VERSION 5.8 ;
BUSBITCHARS "[]" ;
DIVIDERCHAR "/" ;
UNITS
    DATABASE MICRONS 1000 ;
END UNITS

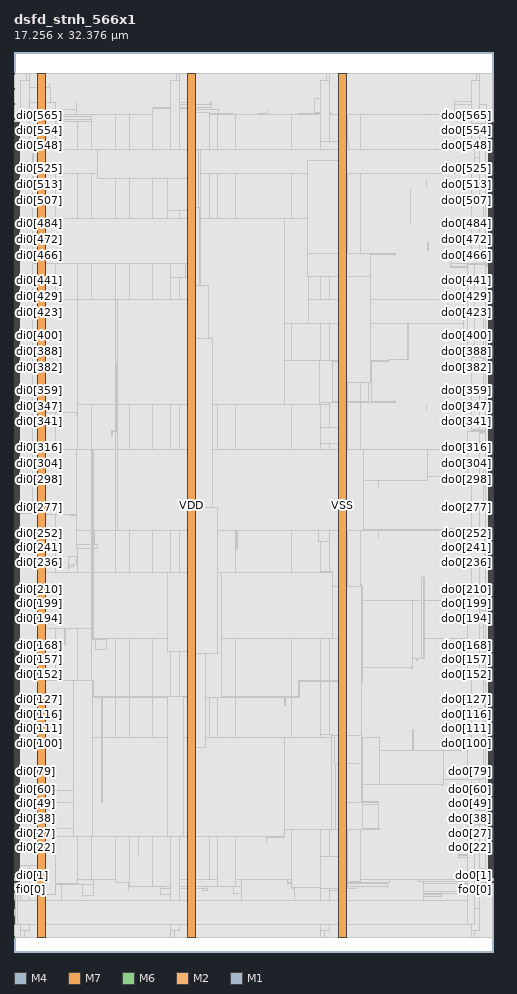
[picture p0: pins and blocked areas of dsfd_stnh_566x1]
MACRO dsfd_stnh_566x1
  FOREIGN dsfd_stnh_566x1 0 0 ;
  CLASS BLOCK ;
  SIZE 17.256 BY 32.376 ;
  PIN di0[0]
    DIRECTION INPUT ;
    USE SIGNAL ;
    PORT
      LAYER M4 ;
        RECT  0 2.688 0.192 2.712 ;
    END
  END di0[0]
  PIN di0[100]
    DIRECTION INPUT ;
    USE SIGNAL ;
    PORT
      LAYER M4 ;
        RECT  0 7.488 0.192 7.512 ;
    END
  END di0[100]
  PIN di0[101]
    DIRECTION INPUT ;
    USE SIGNAL ;
    PORT
      LAYER M4 ;
        RECT  0 7.536 0.192 7.56 ;
    END
  END di0[101]
  PIN di0[102]
    DIRECTION INPUT ;
    USE SIGNAL ;
    PORT
      LAYER M4 ;
        RECT  0 7.584 0.192 7.608 ;
    END
  END di0[102]
  PIN di0[103]
    DIRECTION INPUT ;
    USE SIGNAL ;
    PORT
      LAYER M4 ;
        RECT  0 7.632 0.192 7.656 ;
    END
  END di0[103]
  PIN di0[104]
    DIRECTION INPUT ;
    USE SIGNAL ;
    PORT
      LAYER M4 ;
        RECT  0 7.68 0.192 7.704 ;
    END
  END di0[104]
  PIN di0[105]
    DIRECTION INPUT ;
    USE SIGNAL ;
    PORT
      LAYER M4 ;
        RECT  0 7.728 0.192 7.752 ;
    END
  END di0[105]
  PIN di0[106]
    DIRECTION INPUT ;
    USE SIGNAL ;
    PORT
      LAYER M4 ;
        RECT  0 7.776 0.192 7.8 ;
    END
  END di0[106]
  PIN di0[107]
    DIRECTION INPUT ;
    USE SIGNAL ;
    PORT
      LAYER M4 ;
        RECT  0 7.824 0.192 7.848 ;
    END
  END di0[107]
  PIN di0[108]
    DIRECTION INPUT ;
    USE SIGNAL ;
    PORT
      LAYER M4 ;
        RECT  0 7.872 0.192 7.896 ;
    END
  END di0[108]
  PIN di0[109]
    DIRECTION INPUT ;
    USE SIGNAL ;
    PORT
      LAYER M4 ;
        RECT  0 7.92 0.192 7.944 ;
    END
  END di0[109]
  PIN di0[10]
    DIRECTION INPUT ;
    USE SIGNAL ;
    PORT
      LAYER M4 ;
        RECT  0 3.168 0.192 3.192 ;
    END
  END di0[10]
  PIN di0[110]
    DIRECTION INPUT ;
    USE SIGNAL ;
    PORT
      LAYER M4 ;
        RECT  0 7.968 0.192 7.992 ;
    END
  END di0[110]
  PIN di0[111]
    DIRECTION INPUT ;
    USE SIGNAL ;
    PORT
      LAYER M4 ;
        RECT  0 8.016 0.192 8.04 ;
    END
  END di0[111]
  PIN di0[112]
    DIRECTION INPUT ;
    USE SIGNAL ;
    PORT
      LAYER M4 ;
        RECT  0 8.064 0.192 8.088 ;
    END
  END di0[112]
  PIN di0[113]
    DIRECTION INPUT ;
    USE SIGNAL ;
    PORT
      LAYER M4 ;
        RECT  0 8.112 0.192 8.136 ;
    END
  END di0[113]
  PIN di0[114]
    DIRECTION INPUT ;
    USE SIGNAL ;
    PORT
      LAYER M4 ;
        RECT  0 8.16 0.192 8.184 ;
    END
  END di0[114]
  PIN di0[115]
    DIRECTION INPUT ;
    USE SIGNAL ;
    PORT
      LAYER M4 ;
        RECT  0 8.208 0.192 8.232 ;
    END
  END di0[115]
  PIN di0[116]
    DIRECTION INPUT ;
    USE SIGNAL ;
    PORT
      LAYER M4 ;
        RECT  0 8.256 0.192 8.28 ;
    END
  END di0[116]
  PIN di0[117]
    DIRECTION INPUT ;
    USE SIGNAL ;
    PORT
      LAYER M4 ;
        RECT  0 8.304 0.192 8.328 ;
    END
  END di0[117]
  PIN di0[118]
    DIRECTION INPUT ;
    USE SIGNAL ;
    PORT
      LAYER M4 ;
        RECT  0 8.352 0.192 8.376 ;
    END
  END di0[118]
  PIN di0[119]
    DIRECTION INPUT ;
    USE SIGNAL ;
    PORT
      LAYER M4 ;
        RECT  0 8.4 0.192 8.424 ;
    END
  END di0[119]
  PIN di0[11]
    DIRECTION INPUT ;
    USE SIGNAL ;
    PORT
      LAYER M4 ;
        RECT  0 3.216 0.192 3.24 ;
    END
  END di0[11]
  PIN di0[120]
    DIRECTION INPUT ;
    USE SIGNAL ;
    PORT
      LAYER M4 ;
        RECT  0 8.448 0.192 8.472 ;
    END
  END di0[120]
  PIN di0[121]
    DIRECTION INPUT ;
    USE SIGNAL ;
    PORT
      LAYER M4 ;
        RECT  0 8.496 0.192 8.52 ;
    END
  END di0[121]
  PIN di0[122]
    DIRECTION INPUT ;
    USE SIGNAL ;
    PORT
      LAYER M4 ;
        RECT  0 8.544 0.192 8.568 ;
    END
  END di0[122]
  PIN di0[123]
    DIRECTION INPUT ;
    USE SIGNAL ;
    PORT
      LAYER M4 ;
        RECT  0 8.592 0.192 8.616 ;
    END
  END di0[123]
  PIN di0[124]
    DIRECTION INPUT ;
    USE SIGNAL ;
    PORT
      LAYER M4 ;
        RECT  0 8.64 0.192 8.664 ;
    END
  END di0[124]
  PIN di0[125]
    DIRECTION INPUT ;
    USE SIGNAL ;
    PORT
      LAYER M4 ;
        RECT  0 8.688 0.192 8.712 ;
    END
  END di0[125]
  PIN di0[126]
    DIRECTION INPUT ;
    USE SIGNAL ;
    PORT
      LAYER M4 ;
        RECT  0 8.736 0.192 8.76 ;
    END
  END di0[126]
  PIN di0[127]
    DIRECTION INPUT ;
    USE SIGNAL ;
    PORT
      LAYER M4 ;
        RECT  0 8.784 0.192 8.808 ;
    END
  END di0[127]
  PIN di0[128]
    DIRECTION INPUT ;
    USE SIGNAL ;
    PORT
      LAYER M4 ;
        RECT  0 8.832 0.192 8.856 ;
    END
  END di0[128]
  PIN di0[129]
    DIRECTION INPUT ;
    USE SIGNAL ;
    PORT
      LAYER M4 ;
        RECT  0 8.88 0.192 8.904 ;
    END
  END di0[129]
  PIN di0[12]
    DIRECTION INPUT ;
    USE SIGNAL ;
    PORT
      LAYER M4 ;
        RECT  0 3.264 0.192 3.288 ;
    END
  END di0[12]
  PIN di0[130]
    DIRECTION INPUT ;
    USE SIGNAL ;
    PORT
      LAYER M4 ;
        RECT  0 8.928 0.192 8.952 ;
    END
  END di0[130]
  PIN di0[131]
    DIRECTION INPUT ;
    USE SIGNAL ;
    PORT
      LAYER M4 ;
        RECT  0 8.976 0.192 9 ;
    END
  END di0[131]
  PIN di0[132]
    DIRECTION INPUT ;
    USE SIGNAL ;
    PORT
      LAYER M4 ;
        RECT  0 9.024 0.192 9.048 ;
    END
  END di0[132]
  PIN di0[133]
    DIRECTION INPUT ;
    USE SIGNAL ;
    PORT
      LAYER M4 ;
        RECT  0 9.072 0.192 9.096 ;
    END
  END di0[133]
  PIN di0[134]
    DIRECTION INPUT ;
    USE SIGNAL ;
    PORT
      LAYER M4 ;
        RECT  0 9.12 0.192 9.144 ;
    END
  END di0[134]
  PIN di0[135]
    DIRECTION INPUT ;
    USE SIGNAL ;
    PORT
      LAYER M4 ;
        RECT  0 9.168 0.192 9.192 ;
    END
  END di0[135]
  PIN di0[136]
    DIRECTION INPUT ;
    USE SIGNAL ;
    PORT
      LAYER M4 ;
        RECT  0 9.216 0.192 9.24 ;
    END
  END di0[136]
  PIN di0[137]
    DIRECTION INPUT ;
    USE SIGNAL ;
    PORT
      LAYER M4 ;
        RECT  0 9.264 0.192 9.288 ;
    END
  END di0[137]
  PIN di0[138]
    DIRECTION INPUT ;
    USE SIGNAL ;
    PORT
      LAYER M4 ;
        RECT  0 9.312 0.192 9.336 ;
    END
  END di0[138]
  PIN di0[139]
    DIRECTION INPUT ;
    USE SIGNAL ;
    PORT
      LAYER M4 ;
        RECT  0 9.36 0.192 9.384 ;
    END
  END di0[139]
  PIN di0[13]
    DIRECTION INPUT ;
    USE SIGNAL ;
    PORT
      LAYER M4 ;
        RECT  0 3.312 0.192 3.336 ;
    END
  END di0[13]
  PIN di0[140]
    DIRECTION INPUT ;
    USE SIGNAL ;
    PORT
      LAYER M4 ;
        RECT  0 9.408 0.192 9.432 ;
    END
  END di0[140]
  PIN di0[141]
    DIRECTION INPUT ;
    USE SIGNAL ;
    PORT
      LAYER M4 ;
        RECT  0 9.456 0.192 9.48 ;
    END
  END di0[141]
  PIN di0[142]
    DIRECTION INPUT ;
    USE SIGNAL ;
    PORT
      LAYER M4 ;
        RECT  0 9.504 0.192 9.528 ;
    END
  END di0[142]
  PIN di0[143]
    DIRECTION INPUT ;
    USE SIGNAL ;
    PORT
      LAYER M4 ;
        RECT  0 9.552 0.192 9.576 ;
    END
  END di0[143]
  PIN di0[144]
    DIRECTION INPUT ;
    USE SIGNAL ;
    PORT
      LAYER M4 ;
        RECT  0 9.6 0.192 9.624 ;
    END
  END di0[144]
  PIN di0[145]
    DIRECTION INPUT ;
    USE SIGNAL ;
    PORT
      LAYER M4 ;
        RECT  0 9.648 0.192 9.672 ;
    END
  END di0[145]
  PIN di0[146]
    DIRECTION INPUT ;
    USE SIGNAL ;
    PORT
      LAYER M4 ;
        RECT  0 9.696 0.192 9.72 ;
    END
  END di0[146]
  PIN di0[147]
    DIRECTION INPUT ;
    USE SIGNAL ;
    PORT
      LAYER M4 ;
        RECT  0 9.744 0.192 9.768 ;
    END
  END di0[147]
  PIN di0[148]
    DIRECTION INPUT ;
    USE SIGNAL ;
    PORT
      LAYER M4 ;
        RECT  0 9.792 0.192 9.816 ;
    END
  END di0[148]
  PIN di0[149]
    DIRECTION INPUT ;
    USE SIGNAL ;
    PORT
      LAYER M4 ;
        RECT  0 9.84 0.192 9.864 ;
    END
  END di0[149]
  PIN di0[14]
    DIRECTION INPUT ;
    USE SIGNAL ;
    PORT
      LAYER M4 ;
        RECT  0 3.36 0.192 3.384 ;
    END
  END di0[14]
  PIN di0[150]
    DIRECTION INPUT ;
    USE SIGNAL ;
    PORT
      LAYER M4 ;
        RECT  0 9.888 0.192 9.912 ;
    END
  END di0[150]
  PIN di0[151]
    DIRECTION INPUT ;
    USE SIGNAL ;
    PORT
      LAYER M4 ;
        RECT  0 9.936 0.192 9.96 ;
    END
  END di0[151]
  PIN di0[152]
    DIRECTION INPUT ;
    USE SIGNAL ;
    PORT
      LAYER M4 ;
        RECT  0 9.984 0.192 10.008 ;
    END
  END di0[152]
  PIN di0[153]
    DIRECTION INPUT ;
    USE SIGNAL ;
    PORT
      LAYER M4 ;
        RECT  0 10.032 0.192 10.056 ;
    END
  END di0[153]
  PIN di0[154]
    DIRECTION INPUT ;
    USE SIGNAL ;
    PORT
      LAYER M4 ;
        RECT  0 10.08 0.192 10.104 ;
    END
  END di0[154]
  PIN di0[155]
    DIRECTION INPUT ;
    USE SIGNAL ;
    PORT
      LAYER M4 ;
        RECT  0 10.128 0.192 10.152 ;
    END
  END di0[155]
  PIN di0[156]
    DIRECTION INPUT ;
    USE SIGNAL ;
    PORT
      LAYER M4 ;
        RECT  0 10.176 0.192 10.2 ;
    END
  END di0[156]
  PIN di0[157]
    DIRECTION INPUT ;
    USE SIGNAL ;
    PORT
      LAYER M4 ;
        RECT  0 10.224 0.192 10.248 ;
    END
  END di0[157]
  PIN di0[158]
    DIRECTION INPUT ;
    USE SIGNAL ;
    PORT
      LAYER M4 ;
        RECT  0 10.272 0.192 10.296 ;
    END
  END di0[158]
  PIN di0[159]
    DIRECTION INPUT ;
    USE SIGNAL ;
    PORT
      LAYER M4 ;
        RECT  0 10.32 0.192 10.344 ;
    END
  END di0[159]
  PIN di0[15]
    DIRECTION INPUT ;
    USE SIGNAL ;
    PORT
      LAYER M4 ;
        RECT  0 3.408 0.192 3.432 ;
    END
  END di0[15]
  PIN di0[160]
    DIRECTION INPUT ;
    USE SIGNAL ;
    PORT
      LAYER M4 ;
        RECT  0 10.368 0.192 10.392 ;
    END
  END di0[160]
  PIN di0[161]
    DIRECTION INPUT ;
    USE SIGNAL ;
    PORT
      LAYER M4 ;
        RECT  0 10.416 0.192 10.44 ;
    END
  END di0[161]
  PIN di0[162]
    DIRECTION INPUT ;
    USE SIGNAL ;
    PORT
      LAYER M4 ;
        RECT  0 10.464 0.192 10.488 ;
    END
  END di0[162]
  PIN di0[163]
    DIRECTION INPUT ;
    USE SIGNAL ;
    PORT
      LAYER M4 ;
        RECT  0 10.512 0.192 10.536 ;
    END
  END di0[163]
  PIN di0[164]
    DIRECTION INPUT ;
    USE SIGNAL ;
    PORT
      LAYER M4 ;
        RECT  0 10.56 0.192 10.584 ;
    END
  END di0[164]
  PIN di0[165]
    DIRECTION INPUT ;
    USE SIGNAL ;
    PORT
      LAYER M4 ;
        RECT  0 10.608 0.192 10.632 ;
    END
  END di0[165]
  PIN di0[166]
    DIRECTION INPUT ;
    USE SIGNAL ;
    PORT
      LAYER M4 ;
        RECT  0 10.656 0.192 10.68 ;
    END
  END di0[166]
  PIN di0[167]
    DIRECTION INPUT ;
    USE SIGNAL ;
    PORT
      LAYER M4 ;
        RECT  0 10.704 0.192 10.728 ;
    END
  END di0[167]
  PIN di0[168]
    DIRECTION INPUT ;
    USE SIGNAL ;
    PORT
      LAYER M4 ;
        RECT  0 10.752 0.192 10.776 ;
    END
  END di0[168]
  PIN di0[169]
    DIRECTION INPUT ;
    USE SIGNAL ;
    PORT
      LAYER M4 ;
        RECT  0 10.8 0.192 10.824 ;
    END
  END di0[169]
  PIN di0[16]
    DIRECTION INPUT ;
    USE SIGNAL ;
    PORT
      LAYER M4 ;
        RECT  0 3.456 0.192 3.48 ;
    END
  END di0[16]
  PIN di0[170]
    DIRECTION INPUT ;
    USE SIGNAL ;
    PORT
      LAYER M4 ;
        RECT  0 10.848 0.192 10.872 ;
    END
  END di0[170]
  PIN di0[171]
    DIRECTION INPUT ;
    USE SIGNAL ;
    PORT
      LAYER M4 ;
        RECT  0 10.896 0.192 10.92 ;
    END
  END di0[171]
  PIN di0[172]
    DIRECTION INPUT ;
    USE SIGNAL ;
    PORT
      LAYER M4 ;
        RECT  0 10.944 0.192 10.968 ;
    END
  END di0[172]
  PIN di0[173]
    DIRECTION INPUT ;
    USE SIGNAL ;
    PORT
      LAYER M4 ;
        RECT  0 10.992 0.192 11.016 ;
    END
  END di0[173]
  PIN di0[174]
    DIRECTION INPUT ;
    USE SIGNAL ;
    PORT
      LAYER M4 ;
        RECT  0 11.04 0.192 11.064 ;
    END
  END di0[174]
  PIN di0[175]
    DIRECTION INPUT ;
    USE SIGNAL ;
    PORT
      LAYER M4 ;
        RECT  0 11.088 0.192 11.112 ;
    END
  END di0[175]
  PIN di0[176]
    DIRECTION INPUT ;
    USE SIGNAL ;
    PORT
      LAYER M4 ;
        RECT  0 11.136 0.192 11.16 ;
    END
  END di0[176]
  PIN di0[177]
    DIRECTION INPUT ;
    USE SIGNAL ;
    PORT
      LAYER M4 ;
        RECT  0 11.184 0.192 11.208 ;
    END
  END di0[177]
  PIN di0[178]
    DIRECTION INPUT ;
    USE SIGNAL ;
    PORT
      LAYER M4 ;
        RECT  0 11.232 0.192 11.256 ;
    END
  END di0[178]
  PIN di0[179]
    DIRECTION INPUT ;
    USE SIGNAL ;
    PORT
      LAYER M4 ;
        RECT  0 11.28 0.192 11.304 ;
    END
  END di0[179]
  PIN di0[17]
    DIRECTION INPUT ;
    USE SIGNAL ;
    PORT
      LAYER M4 ;
        RECT  0 3.504 0.192 3.528 ;
    END
  END di0[17]
  PIN di0[180]
    DIRECTION INPUT ;
    USE SIGNAL ;
    PORT
      LAYER M4 ;
        RECT  0 11.328 0.192 11.352 ;
    END
  END di0[180]
  PIN di0[181]
    DIRECTION INPUT ;
    USE SIGNAL ;
    PORT
      LAYER M4 ;
        RECT  0 11.376 0.192 11.4 ;
    END
  END di0[181]
  PIN di0[182]
    DIRECTION INPUT ;
    USE SIGNAL ;
    PORT
      LAYER M4 ;
        RECT  0 11.424 0.192 11.448 ;
    END
  END di0[182]
  PIN di0[183]
    DIRECTION INPUT ;
    USE SIGNAL ;
    PORT
      LAYER M4 ;
        RECT  0 11.472 0.192 11.496 ;
    END
  END di0[183]
  PIN di0[184]
    DIRECTION INPUT ;
    USE SIGNAL ;
    PORT
      LAYER M4 ;
        RECT  0 11.52 0.192 11.544 ;
    END
  END di0[184]
  PIN di0[185]
    DIRECTION INPUT ;
    USE SIGNAL ;
    PORT
      LAYER M4 ;
        RECT  0 11.568 0.192 11.592 ;
    END
  END di0[185]
  PIN di0[186]
    DIRECTION INPUT ;
    USE SIGNAL ;
    PORT
      LAYER M4 ;
        RECT  0 11.616 0.192 11.64 ;
    END
  END di0[186]
  PIN di0[187]
    DIRECTION INPUT ;
    USE SIGNAL ;
    PORT
      LAYER M4 ;
        RECT  0 11.664 0.192 11.688 ;
    END
  END di0[187]
  PIN di0[188]
    DIRECTION INPUT ;
    USE SIGNAL ;
    PORT
      LAYER M4 ;
        RECT  0 11.712 0.192 11.736 ;
    END
  END di0[188]
  PIN di0[189]
    DIRECTION INPUT ;
    USE SIGNAL ;
    PORT
      LAYER M4 ;
        RECT  0 11.76 0.192 11.784 ;
    END
  END di0[189]
  PIN di0[18]
    DIRECTION INPUT ;
    USE SIGNAL ;
    PORT
      LAYER M4 ;
        RECT  0 3.552 0.192 3.576 ;
    END
  END di0[18]
  PIN di0[190]
    DIRECTION INPUT ;
    USE SIGNAL ;
    PORT
      LAYER M4 ;
        RECT  0 11.808 0.192 11.832 ;
    END
  END di0[190]
  PIN di0[191]
    DIRECTION INPUT ;
    USE SIGNAL ;
    PORT
      LAYER M4 ;
        RECT  0 11.856 0.192 11.88 ;
    END
  END di0[191]
  PIN di0[192]
    DIRECTION INPUT ;
    USE SIGNAL ;
    PORT
      LAYER M4 ;
        RECT  0 11.904 0.192 11.928 ;
    END
  END di0[192]
  PIN di0[193]
    DIRECTION INPUT ;
    USE SIGNAL ;
    PORT
      LAYER M4 ;
        RECT  0 11.952 0.192 11.976 ;
    END
  END di0[193]
  PIN di0[194]
    DIRECTION INPUT ;
    USE SIGNAL ;
    PORT
      LAYER M4 ;
        RECT  0 12 0.192 12.024 ;
    END
  END di0[194]
  PIN di0[195]
    DIRECTION INPUT ;
    USE SIGNAL ;
    PORT
      LAYER M4 ;
        RECT  0 12.048 0.192 12.072 ;
    END
  END di0[195]
  PIN di0[196]
    DIRECTION INPUT ;
    USE SIGNAL ;
    PORT
      LAYER M4 ;
        RECT  0 12.096 0.192 12.12 ;
    END
  END di0[196]
  PIN di0[197]
    DIRECTION INPUT ;
    USE SIGNAL ;
    PORT
      LAYER M4 ;
        RECT  0 12.144 0.192 12.168 ;
    END
  END di0[197]
  PIN di0[198]
    DIRECTION INPUT ;
    USE SIGNAL ;
    PORT
      LAYER M4 ;
        RECT  0 12.192 0.192 12.216 ;
    END
  END di0[198]
  PIN di0[199]
    DIRECTION INPUT ;
    USE SIGNAL ;
    PORT
      LAYER M4 ;
        RECT  0 12.24 0.192 12.264 ;
    END
  END di0[199]
  PIN di0[19]
    DIRECTION INPUT ;
    USE SIGNAL ;
    PORT
      LAYER M4 ;
        RECT  0 3.6 0.192 3.624 ;
    END
  END di0[19]
  PIN di0[1]
    DIRECTION INPUT ;
    USE SIGNAL ;
    PORT
      LAYER M4 ;
        RECT  0 2.736 0.192 2.76 ;
    END
  END di0[1]
  PIN di0[200]
    DIRECTION INPUT ;
    USE SIGNAL ;
    PORT
      LAYER M4 ;
        RECT  0 12.288 0.192 12.312 ;
    END
  END di0[200]
  PIN di0[201]
    DIRECTION INPUT ;
    USE SIGNAL ;
    PORT
      LAYER M4 ;
        RECT  0 12.336 0.192 12.36 ;
    END
  END di0[201]
  PIN di0[202]
    DIRECTION INPUT ;
    USE SIGNAL ;
    PORT
      LAYER M4 ;
        RECT  0 12.384 0.192 12.408 ;
    END
  END di0[202]
  PIN di0[203]
    DIRECTION INPUT ;
    USE SIGNAL ;
    PORT
      LAYER M4 ;
        RECT  0 12.432 0.192 12.456 ;
    END
  END di0[203]
  PIN di0[204]
    DIRECTION INPUT ;
    USE SIGNAL ;
    PORT
      LAYER M4 ;
        RECT  0 12.48 0.192 12.504 ;
    END
  END di0[204]
  PIN di0[205]
    DIRECTION INPUT ;
    USE SIGNAL ;
    PORT
      LAYER M4 ;
        RECT  0 12.528 0.192 12.552 ;
    END
  END di0[205]
  PIN di0[206]
    DIRECTION INPUT ;
    USE SIGNAL ;
    PORT
      LAYER M4 ;
        RECT  0 12.576 0.192 12.6 ;
    END
  END di0[206]
  PIN di0[207]
    DIRECTION INPUT ;
    USE SIGNAL ;
    PORT
      LAYER M4 ;
        RECT  0 12.624 0.192 12.648 ;
    END
  END di0[207]
  PIN di0[208]
    DIRECTION INPUT ;
    USE SIGNAL ;
    PORT
      LAYER M4 ;
        RECT  0 12.672 0.192 12.696 ;
    END
  END di0[208]
  PIN di0[209]
    DIRECTION INPUT ;
    USE SIGNAL ;
    PORT
      LAYER M4 ;
        RECT  0 12.72 0.192 12.744 ;
    END
  END di0[209]
  PIN di0[20]
    DIRECTION INPUT ;
    USE SIGNAL ;
    PORT
      LAYER M4 ;
        RECT  0 3.648 0.192 3.672 ;
    END
  END di0[20]
  PIN di0[210]
    DIRECTION INPUT ;
    USE SIGNAL ;
    PORT
      LAYER M4 ;
        RECT  0 12.768 0.192 12.792 ;
    END
  END di0[210]
  PIN di0[211]
    DIRECTION INPUT ;
    USE SIGNAL ;
    PORT
      LAYER M4 ;
        RECT  0 12.816 0.192 12.84 ;
    END
  END di0[211]
  PIN di0[212]
    DIRECTION INPUT ;
    USE SIGNAL ;
    PORT
      LAYER M4 ;
        RECT  0 12.864 0.192 12.888 ;
    END
  END di0[212]
  PIN di0[213]
    DIRECTION INPUT ;
    USE SIGNAL ;
    PORT
      LAYER M4 ;
        RECT  0 12.912 0.192 12.936 ;
    END
  END di0[213]
  PIN di0[214]
    DIRECTION INPUT ;
    USE SIGNAL ;
    PORT
      LAYER M4 ;
        RECT  0 12.96 0.192 12.984 ;
    END
  END di0[214]
  PIN di0[215]
    DIRECTION INPUT ;
    USE SIGNAL ;
    PORT
      LAYER M4 ;
        RECT  0 13.008 0.192 13.032 ;
    END
  END di0[215]
  PIN di0[216]
    DIRECTION INPUT ;
    USE SIGNAL ;
    PORT
      LAYER M4 ;
        RECT  0 13.056 0.192 13.08 ;
    END
  END di0[216]
  PIN di0[217]
    DIRECTION INPUT ;
    USE SIGNAL ;
    PORT
      LAYER M4 ;
        RECT  0 13.104 0.192 13.128 ;
    END
  END di0[217]
  PIN di0[218]
    DIRECTION INPUT ;
    USE SIGNAL ;
    PORT
      LAYER M4 ;
        RECT  0 13.152 0.192 13.176 ;
    END
  END di0[218]
  PIN di0[219]
    DIRECTION INPUT ;
    USE SIGNAL ;
    PORT
      LAYER M4 ;
        RECT  0 13.2 0.192 13.224 ;
    END
  END di0[219]
  PIN di0[21]
    DIRECTION INPUT ;
    USE SIGNAL ;
    PORT
      LAYER M4 ;
        RECT  0 3.696 0.192 3.72 ;
    END
  END di0[21]
  PIN di0[220]
    DIRECTION INPUT ;
    USE SIGNAL ;
    PORT
      LAYER M4 ;
        RECT  0 13.248 0.192 13.272 ;
    END
  END di0[220]
  PIN di0[221]
    DIRECTION INPUT ;
    USE SIGNAL ;
    PORT
      LAYER M4 ;
        RECT  0 13.296 0.192 13.32 ;
    END
  END di0[221]
  PIN di0[222]
    DIRECTION INPUT ;
    USE SIGNAL ;
    PORT
      LAYER M4 ;
        RECT  0 13.344 0.192 13.368 ;
    END
  END di0[222]
  PIN di0[223]
    DIRECTION INPUT ;
    USE SIGNAL ;
    PORT
      LAYER M4 ;
        RECT  0 13.392 0.192 13.416 ;
    END
  END di0[223]
  PIN di0[224]
    DIRECTION INPUT ;
    USE SIGNAL ;
    PORT
      LAYER M4 ;
        RECT  0 13.44 0.192 13.464 ;
    END
  END di0[224]
  PIN di0[225]
    DIRECTION INPUT ;
    USE SIGNAL ;
    PORT
      LAYER M4 ;
        RECT  0 13.488 0.192 13.512 ;
    END
  END di0[225]
  PIN di0[226]
    DIRECTION INPUT ;
    USE SIGNAL ;
    PORT
      LAYER M4 ;
        RECT  0 13.536 0.192 13.56 ;
    END
  END di0[226]
  PIN di0[227]
    DIRECTION INPUT ;
    USE SIGNAL ;
    PORT
      LAYER M4 ;
        RECT  0 13.584 0.192 13.608 ;
    END
  END di0[227]
  PIN di0[228]
    DIRECTION INPUT ;
    USE SIGNAL ;
    PORT
      LAYER M4 ;
        RECT  0 13.632 0.192 13.656 ;
    END
  END di0[228]
  PIN di0[229]
    DIRECTION INPUT ;
    USE SIGNAL ;
    PORT
      LAYER M4 ;
        RECT  0 13.68 0.192 13.704 ;
    END
  END di0[229]
  PIN di0[22]
    DIRECTION INPUT ;
    USE SIGNAL ;
    PORT
      LAYER M4 ;
        RECT  0 3.744 0.192 3.768 ;
    END
  END di0[22]
  PIN di0[230]
    DIRECTION INPUT ;
    USE SIGNAL ;
    PORT
      LAYER M4 ;
        RECT  0 13.728 0.192 13.752 ;
    END
  END di0[230]
  PIN di0[231]
    DIRECTION INPUT ;
    USE SIGNAL ;
    PORT
      LAYER M4 ;
        RECT  0 13.776 0.192 13.8 ;
    END
  END di0[231]
  PIN di0[232]
    DIRECTION INPUT ;
    USE SIGNAL ;
    PORT
      LAYER M4 ;
        RECT  0 13.824 0.192 13.848 ;
    END
  END di0[232]
  PIN di0[233]
    DIRECTION INPUT ;
    USE SIGNAL ;
    PORT
      LAYER M4 ;
        RECT  0 13.872 0.192 13.896 ;
    END
  END di0[233]
  PIN di0[234]
    DIRECTION INPUT ;
    USE SIGNAL ;
    PORT
      LAYER M4 ;
        RECT  0 13.92 0.192 13.944 ;
    END
  END di0[234]
  PIN di0[235]
    DIRECTION INPUT ;
    USE SIGNAL ;
    PORT
      LAYER M4 ;
        RECT  0 13.968 0.192 13.992 ;
    END
  END di0[235]
  PIN di0[236]
    DIRECTION INPUT ;
    USE SIGNAL ;
    PORT
      LAYER M4 ;
        RECT  0 14.016 0.192 14.04 ;
    END
  END di0[236]
  PIN di0[237]
    DIRECTION INPUT ;
    USE SIGNAL ;
    PORT
      LAYER M4 ;
        RECT  0 14.064 0.192 14.088 ;
    END
  END di0[237]
  PIN di0[238]
    DIRECTION INPUT ;
    USE SIGNAL ;
    PORT
      LAYER M4 ;
        RECT  0 14.112 0.192 14.136 ;
    END
  END di0[238]
  PIN di0[239]
    DIRECTION INPUT ;
    USE SIGNAL ;
    PORT
      LAYER M4 ;
        RECT  0 14.16 0.192 14.184 ;
    END
  END di0[239]
  PIN di0[23]
    DIRECTION INPUT ;
    USE SIGNAL ;
    PORT
      LAYER M4 ;
        RECT  0 3.792 0.192 3.816 ;
    END
  END di0[23]
  PIN di0[240]
    DIRECTION INPUT ;
    USE SIGNAL ;
    PORT
      LAYER M4 ;
        RECT  0 14.208 0.192 14.232 ;
    END
  END di0[240]
  PIN di0[241]
    DIRECTION INPUT ;
    USE SIGNAL ;
    PORT
      LAYER M4 ;
        RECT  0 14.256 0.192 14.28 ;
    END
  END di0[241]
  PIN di0[242]
    DIRECTION INPUT ;
    USE SIGNAL ;
    PORT
      LAYER M4 ;
        RECT  0 14.304 0.192 14.328 ;
    END
  END di0[242]
  PIN di0[243]
    DIRECTION INPUT ;
    USE SIGNAL ;
    PORT
      LAYER M4 ;
        RECT  0 14.352 0.192 14.376 ;
    END
  END di0[243]
  PIN di0[244]
    DIRECTION INPUT ;
    USE SIGNAL ;
    PORT
      LAYER M4 ;
        RECT  0 14.4 0.192 14.424 ;
    END
  END di0[244]
  PIN di0[245]
    DIRECTION INPUT ;
    USE SIGNAL ;
    PORT
      LAYER M4 ;
        RECT  0 14.448 0.192 14.472 ;
    END
  END di0[245]
  PIN di0[246]
    DIRECTION INPUT ;
    USE SIGNAL ;
    PORT
      LAYER M4 ;
        RECT  0 14.496 0.192 14.52 ;
    END
  END di0[246]
  PIN di0[247]
    DIRECTION INPUT ;
    USE SIGNAL ;
    PORT
      LAYER M4 ;
        RECT  0 14.544 0.192 14.568 ;
    END
  END di0[247]
  PIN di0[248]
    DIRECTION INPUT ;
    USE SIGNAL ;
    PORT
      LAYER M4 ;
        RECT  0 14.592 0.192 14.616 ;
    END
  END di0[248]
  PIN di0[249]
    DIRECTION INPUT ;
    USE SIGNAL ;
    PORT
      LAYER M4 ;
        RECT  0 14.64 0.192 14.664 ;
    END
  END di0[249]
  PIN di0[24]
    DIRECTION INPUT ;
    USE SIGNAL ;
    PORT
      LAYER M4 ;
        RECT  0 3.84 0.192 3.864 ;
    END
  END di0[24]
  PIN di0[250]
    DIRECTION INPUT ;
    USE SIGNAL ;
    PORT
      LAYER M4 ;
        RECT  0 14.688 0.192 14.712 ;
    END
  END di0[250]
  PIN di0[251]
    DIRECTION INPUT ;
    USE SIGNAL ;
    PORT
      LAYER M4 ;
        RECT  0 14.736 0.192 14.76 ;
    END
  END di0[251]
  PIN di0[252]
    DIRECTION INPUT ;
    USE SIGNAL ;
    PORT
      LAYER M4 ;
        RECT  0 14.784 0.192 14.808 ;
    END
  END di0[252]
  PIN di0[253]
    DIRECTION INPUT ;
    USE SIGNAL ;
    PORT
      LAYER M4 ;
        RECT  0 14.832 0.192 14.856 ;
    END
  END di0[253]
  PIN di0[254]
    DIRECTION INPUT ;
    USE SIGNAL ;
    PORT
      LAYER M4 ;
        RECT  0 14.88 0.192 14.904 ;
    END
  END di0[254]
  PIN di0[255]
    DIRECTION INPUT ;
    USE SIGNAL ;
    PORT
      LAYER M4 ;
        RECT  0 14.928 0.192 14.952 ;
    END
  END di0[255]
  PIN di0[256]
    DIRECTION INPUT ;
    USE SIGNAL ;
    PORT
      LAYER M4 ;
        RECT  0 14.976 0.192 15 ;
    END
  END di0[256]
  PIN di0[257]
    DIRECTION INPUT ;
    USE SIGNAL ;
    PORT
      LAYER M4 ;
        RECT  0 15.024 0.192 15.048 ;
    END
  END di0[257]
  PIN di0[258]
    DIRECTION INPUT ;
    USE SIGNAL ;
    PORT
      LAYER M4 ;
        RECT  0 15.072 0.192 15.096 ;
    END
  END di0[258]
  PIN di0[259]
    DIRECTION INPUT ;
    USE SIGNAL ;
    PORT
      LAYER M4 ;
        RECT  0 15.12 0.192 15.144 ;
    END
  END di0[259]
  PIN di0[25]
    DIRECTION INPUT ;
    USE SIGNAL ;
    PORT
      LAYER M4 ;
        RECT  0 3.888 0.192 3.912 ;
    END
  END di0[25]
  PIN di0[260]
    DIRECTION INPUT ;
    USE SIGNAL ;
    PORT
      LAYER M4 ;
        RECT  0 15.168 0.192 15.192 ;
    END
  END di0[260]
  PIN di0[261]
    DIRECTION INPUT ;
    USE SIGNAL ;
    PORT
      LAYER M4 ;
        RECT  0 15.216 0.192 15.24 ;
    END
  END di0[261]
  PIN di0[262]
    DIRECTION INPUT ;
    USE SIGNAL ;
    PORT
      LAYER M4 ;
        RECT  0 15.264 0.192 15.288 ;
    END
  END di0[262]
  PIN di0[263]
    DIRECTION INPUT ;
    USE SIGNAL ;
    PORT
      LAYER M4 ;
        RECT  0 15.312 0.192 15.336 ;
    END
  END di0[263]
  PIN di0[264]
    DIRECTION INPUT ;
    USE SIGNAL ;
    PORT
      LAYER M4 ;
        RECT  0 15.36 0.192 15.384 ;
    END
  END di0[264]
  PIN di0[265]
    DIRECTION INPUT ;
    USE SIGNAL ;
    PORT
      LAYER M4 ;
        RECT  0 15.408 0.192 15.432 ;
    END
  END di0[265]
  PIN di0[266]
    DIRECTION INPUT ;
    USE SIGNAL ;
    PORT
      LAYER M4 ;
        RECT  0 15.456 0.192 15.48 ;
    END
  END di0[266]
  PIN di0[267]
    DIRECTION INPUT ;
    USE SIGNAL ;
    PORT
      LAYER M4 ;
        RECT  0 15.504 0.192 15.528 ;
    END
  END di0[267]
  PIN di0[268]
    DIRECTION INPUT ;
    USE SIGNAL ;
    PORT
      LAYER M4 ;
        RECT  0 15.552 0.192 15.576 ;
    END
  END di0[268]
  PIN di0[269]
    DIRECTION INPUT ;
    USE SIGNAL ;
    PORT
      LAYER M4 ;
        RECT  0 15.6 0.192 15.624 ;
    END
  END di0[269]
  PIN di0[26]
    DIRECTION INPUT ;
    USE SIGNAL ;
    PORT
      LAYER M4 ;
        RECT  0 3.936 0.192 3.96 ;
    END
  END di0[26]
  PIN di0[270]
    DIRECTION INPUT ;
    USE SIGNAL ;
    PORT
      LAYER M4 ;
        RECT  0 15.648 0.192 15.672 ;
    END
  END di0[270]
  PIN di0[271]
    DIRECTION INPUT ;
    USE SIGNAL ;
    PORT
      LAYER M4 ;
        RECT  0 15.696 0.192 15.72 ;
    END
  END di0[271]
  PIN di0[272]
    DIRECTION INPUT ;
    USE SIGNAL ;
    PORT
      LAYER M4 ;
        RECT  0 15.744 0.192 15.768 ;
    END
  END di0[272]
  PIN di0[273]
    DIRECTION INPUT ;
    USE SIGNAL ;
    PORT
      LAYER M4 ;
        RECT  0 15.792 0.192 15.816 ;
    END
  END di0[273]
  PIN di0[274]
    DIRECTION INPUT ;
    USE SIGNAL ;
    PORT
      LAYER M4 ;
        RECT  0 15.84 0.192 15.864 ;
    END
  END di0[274]
  PIN di0[275]
    DIRECTION INPUT ;
    USE SIGNAL ;
    PORT
      LAYER M4 ;
        RECT  0 15.888 0.192 15.912 ;
    END
  END di0[275]
  PIN di0[276]
    DIRECTION INPUT ;
    USE SIGNAL ;
    PORT
      LAYER M4 ;
        RECT  0 15.936 0.192 15.96 ;
    END
  END di0[276]
  PIN di0[277]
    DIRECTION INPUT ;
    USE SIGNAL ;
    PORT
      LAYER M4 ;
        RECT  0 15.984 0.192 16.008 ;
    END
  END di0[277]
  PIN di0[278]
    DIRECTION INPUT ;
    USE SIGNAL ;
    PORT
      LAYER M4 ;
        RECT  0 16.032 0.192 16.056 ;
    END
  END di0[278]
  PIN di0[279]
    DIRECTION INPUT ;
    USE SIGNAL ;
    PORT
      LAYER M4 ;
        RECT  0 16.08 0.192 16.104 ;
    END
  END di0[279]
  PIN di0[27]
    DIRECTION INPUT ;
    USE SIGNAL ;
    PORT
      LAYER M4 ;
        RECT  0 3.984 0.192 4.008 ;
    END
  END di0[27]
  PIN di0[280]
    DIRECTION INPUT ;
    USE SIGNAL ;
    PORT
      LAYER M4 ;
        RECT  0 16.128 0.192 16.152 ;
    END
  END di0[280]
  PIN di0[281]
    DIRECTION INPUT ;
    USE SIGNAL ;
    PORT
      LAYER M4 ;
        RECT  0 16.176 0.192 16.2 ;
    END
  END di0[281]
  PIN di0[282]
    DIRECTION INPUT ;
    USE SIGNAL ;
    PORT
      LAYER M4 ;
        RECT  0 16.224 0.192 16.248 ;
    END
  END di0[282]
  PIN di0[283]
    DIRECTION INPUT ;
    USE SIGNAL ;
    PORT
      LAYER M4 ;
        RECT  0 16.272 0.192 16.296 ;
    END
  END di0[283]
  PIN di0[284]
    DIRECTION INPUT ;
    USE SIGNAL ;
    PORT
      LAYER M4 ;
        RECT  0 16.32 0.192 16.344 ;
    END
  END di0[284]
  PIN di0[285]
    DIRECTION INPUT ;
    USE SIGNAL ;
    PORT
      LAYER M4 ;
        RECT  0 16.368 0.192 16.392 ;
    END
  END di0[285]
  PIN di0[286]
    DIRECTION INPUT ;
    USE SIGNAL ;
    PORT
      LAYER M4 ;
        RECT  0 16.416 0.192 16.44 ;
    END
  END di0[286]
  PIN di0[287]
    DIRECTION INPUT ;
    USE SIGNAL ;
    PORT
      LAYER M4 ;
        RECT  0 16.464 0.192 16.488 ;
    END
  END di0[287]
  PIN di0[288]
    DIRECTION INPUT ;
    USE SIGNAL ;
    PORT
      LAYER M4 ;
        RECT  0 16.512 0.192 16.536 ;
    END
  END di0[288]
  PIN di0[289]
    DIRECTION INPUT ;
    USE SIGNAL ;
    PORT
      LAYER M4 ;
        RECT  0 16.56 0.192 16.584 ;
    END
  END di0[289]
  PIN di0[28]
    DIRECTION INPUT ;
    USE SIGNAL ;
    PORT
      LAYER M4 ;
        RECT  0 4.032 0.192 4.056 ;
    END
  END di0[28]
  PIN di0[290]
    DIRECTION INPUT ;
    USE SIGNAL ;
    PORT
      LAYER M4 ;
        RECT  0 16.608 0.192 16.632 ;
    END
  END di0[290]
  PIN di0[291]
    DIRECTION INPUT ;
    USE SIGNAL ;
    PORT
      LAYER M4 ;
        RECT  0 16.656 0.192 16.68 ;
    END
  END di0[291]
  PIN di0[292]
    DIRECTION INPUT ;
    USE SIGNAL ;
    PORT
      LAYER M4 ;
        RECT  0 16.704 0.192 16.728 ;
    END
  END di0[292]
  PIN di0[293]
    DIRECTION INPUT ;
    USE SIGNAL ;
    PORT
      LAYER M4 ;
        RECT  0 16.752 0.192 16.776 ;
    END
  END di0[293]
  PIN di0[294]
    DIRECTION INPUT ;
    USE SIGNAL ;
    PORT
      LAYER M4 ;
        RECT  0 16.8 0.192 16.824 ;
    END
  END di0[294]
  PIN di0[295]
    DIRECTION INPUT ;
    USE SIGNAL ;
    PORT
      LAYER M4 ;
        RECT  0 16.848 0.192 16.872 ;
    END
  END di0[295]
  PIN di0[296]
    DIRECTION INPUT ;
    USE SIGNAL ;
    PORT
      LAYER M4 ;
        RECT  0 16.896 0.192 16.92 ;
    END
  END di0[296]
  PIN di0[297]
    DIRECTION INPUT ;
    USE SIGNAL ;
    PORT
      LAYER M4 ;
        RECT  0 16.944 0.192 16.968 ;
    END
  END di0[297]
  PIN di0[298]
    DIRECTION INPUT ;
    USE SIGNAL ;
    PORT
      LAYER M4 ;
        RECT  0 16.992 0.192 17.016 ;
    END
  END di0[298]
  PIN di0[299]
    DIRECTION INPUT ;
    USE SIGNAL ;
    PORT
      LAYER M4 ;
        RECT  0 17.04 0.192 17.064 ;
    END
  END di0[299]
  PIN di0[29]
    DIRECTION INPUT ;
    USE SIGNAL ;
    PORT
      LAYER M4 ;
        RECT  0 4.08 0.192 4.104 ;
    END
  END di0[29]
  PIN di0[2]
    DIRECTION INPUT ;
    USE SIGNAL ;
    PORT
      LAYER M4 ;
        RECT  0 2.784 0.192 2.808 ;
    END
  END di0[2]
  PIN di0[300]
    DIRECTION INPUT ;
    USE SIGNAL ;
    PORT
      LAYER M4 ;
        RECT  0 17.088 0.192 17.112 ;
    END
  END di0[300]
  PIN di0[301]
    DIRECTION INPUT ;
    USE SIGNAL ;
    PORT
      LAYER M4 ;
        RECT  0 17.136 0.192 17.16 ;
    END
  END di0[301]
  PIN di0[302]
    DIRECTION INPUT ;
    USE SIGNAL ;
    PORT
      LAYER M4 ;
        RECT  0 17.184 0.192 17.208 ;
    END
  END di0[302]
  PIN di0[303]
    DIRECTION INPUT ;
    USE SIGNAL ;
    PORT
      LAYER M4 ;
        RECT  0 17.232 0.192 17.256 ;
    END
  END di0[303]
  PIN di0[304]
    DIRECTION INPUT ;
    USE SIGNAL ;
    PORT
      LAYER M4 ;
        RECT  0 17.28 0.192 17.304 ;
    END
  END di0[304]
  PIN di0[305]
    DIRECTION INPUT ;
    USE SIGNAL ;
    PORT
      LAYER M4 ;
        RECT  0 17.328 0.192 17.352 ;
    END
  END di0[305]
  PIN di0[306]
    DIRECTION INPUT ;
    USE SIGNAL ;
    PORT
      LAYER M4 ;
        RECT  0 17.376 0.192 17.4 ;
    END
  END di0[306]
  PIN di0[307]
    DIRECTION INPUT ;
    USE SIGNAL ;
    PORT
      LAYER M4 ;
        RECT  0 17.424 0.192 17.448 ;
    END
  END di0[307]
  PIN di0[308]
    DIRECTION INPUT ;
    USE SIGNAL ;
    PORT
      LAYER M4 ;
        RECT  0 17.472 0.192 17.496 ;
    END
  END di0[308]
  PIN di0[309]
    DIRECTION INPUT ;
    USE SIGNAL ;
    PORT
      LAYER M4 ;
        RECT  0 17.52 0.192 17.544 ;
    END
  END di0[309]
  PIN di0[30]
    DIRECTION INPUT ;
    USE SIGNAL ;
    PORT
      LAYER M4 ;
        RECT  0 4.128 0.192 4.152 ;
    END
  END di0[30]
  PIN di0[310]
    DIRECTION INPUT ;
    USE SIGNAL ;
    PORT
      LAYER M4 ;
        RECT  0 17.568 0.192 17.592 ;
    END
  END di0[310]
  PIN di0[311]
    DIRECTION INPUT ;
    USE SIGNAL ;
    PORT
      LAYER M4 ;
        RECT  0 17.616 0.192 17.64 ;
    END
  END di0[311]
  PIN di0[312]
    DIRECTION INPUT ;
    USE SIGNAL ;
    PORT
      LAYER M4 ;
        RECT  0 17.664 0.192 17.688 ;
    END
  END di0[312]
  PIN di0[313]
    DIRECTION INPUT ;
    USE SIGNAL ;
    PORT
      LAYER M4 ;
        RECT  0 17.712 0.192 17.736 ;
    END
  END di0[313]
  PIN di0[314]
    DIRECTION INPUT ;
    USE SIGNAL ;
    PORT
      LAYER M4 ;
        RECT  0 17.76 0.192 17.784 ;
    END
  END di0[314]
  PIN di0[315]
    DIRECTION INPUT ;
    USE SIGNAL ;
    PORT
      LAYER M4 ;
        RECT  0 17.808 0.192 17.832 ;
    END
  END di0[315]
  PIN di0[316]
    DIRECTION INPUT ;
    USE SIGNAL ;
    PORT
      LAYER M4 ;
        RECT  0 17.856 0.192 17.88 ;
    END
  END di0[316]
  PIN di0[317]
    DIRECTION INPUT ;
    USE SIGNAL ;
    PORT
      LAYER M4 ;
        RECT  0 17.904 0.192 17.928 ;
    END
  END di0[317]
  PIN di0[318]
    DIRECTION INPUT ;
    USE SIGNAL ;
    PORT
      LAYER M4 ;
        RECT  0 17.952 0.192 17.976 ;
    END
  END di0[318]
  PIN di0[319]
    DIRECTION INPUT ;
    USE SIGNAL ;
    PORT
      LAYER M4 ;
        RECT  0 18 0.192 18.024 ;
    END
  END di0[319]
  PIN di0[31]
    DIRECTION INPUT ;
    USE SIGNAL ;
    PORT
      LAYER M4 ;
        RECT  0 4.176 0.192 4.2 ;
    END
  END di0[31]
  PIN di0[320]
    DIRECTION INPUT ;
    USE SIGNAL ;
    PORT
      LAYER M4 ;
        RECT  0 18.048 0.192 18.072 ;
    END
  END di0[320]
  PIN di0[321]
    DIRECTION INPUT ;
    USE SIGNAL ;
    PORT
      LAYER M4 ;
        RECT  0 18.096 0.192 18.12 ;
    END
  END di0[321]
  PIN di0[322]
    DIRECTION INPUT ;
    USE SIGNAL ;
    PORT
      LAYER M4 ;
        RECT  0 18.144 0.192 18.168 ;
    END
  END di0[322]
  PIN di0[323]
    DIRECTION INPUT ;
    USE SIGNAL ;
    PORT
      LAYER M4 ;
        RECT  0 18.192 0.192 18.216 ;
    END
  END di0[323]
  PIN di0[324]
    DIRECTION INPUT ;
    USE SIGNAL ;
    PORT
      LAYER M4 ;
        RECT  0 18.24 0.192 18.264 ;
    END
  END di0[324]
  PIN di0[325]
    DIRECTION INPUT ;
    USE SIGNAL ;
    PORT
      LAYER M4 ;
        RECT  0 18.288 0.192 18.312 ;
    END
  END di0[325]
  PIN di0[326]
    DIRECTION INPUT ;
    USE SIGNAL ;
    PORT
      LAYER M4 ;
        RECT  0 18.336 0.192 18.36 ;
    END
  END di0[326]
  PIN di0[327]
    DIRECTION INPUT ;
    USE SIGNAL ;
    PORT
      LAYER M4 ;
        RECT  0 18.384 0.192 18.408 ;
    END
  END di0[327]
  PIN di0[328]
    DIRECTION INPUT ;
    USE SIGNAL ;
    PORT
      LAYER M4 ;
        RECT  0 18.432 0.192 18.456 ;
    END
  END di0[328]
  PIN di0[329]
    DIRECTION INPUT ;
    USE SIGNAL ;
    PORT
      LAYER M4 ;
        RECT  0 18.48 0.192 18.504 ;
    END
  END di0[329]
  PIN di0[32]
    DIRECTION INPUT ;
    USE SIGNAL ;
    PORT
      LAYER M4 ;
        RECT  0 4.224 0.192 4.248 ;
    END
  END di0[32]
  PIN di0[330]
    DIRECTION INPUT ;
    USE SIGNAL ;
    PORT
      LAYER M4 ;
        RECT  0 18.528 0.192 18.552 ;
    END
  END di0[330]
  PIN di0[331]
    DIRECTION INPUT ;
    USE SIGNAL ;
    PORT
      LAYER M4 ;
        RECT  0 18.576 0.192 18.6 ;
    END
  END di0[331]
  PIN di0[332]
    DIRECTION INPUT ;
    USE SIGNAL ;
    PORT
      LAYER M4 ;
        RECT  0 18.624 0.192 18.648 ;
    END
  END di0[332]
  PIN di0[333]
    DIRECTION INPUT ;
    USE SIGNAL ;
    PORT
      LAYER M4 ;
        RECT  0 18.672 0.192 18.696 ;
    END
  END di0[333]
  PIN di0[334]
    DIRECTION INPUT ;
    USE SIGNAL ;
    PORT
      LAYER M4 ;
        RECT  0 18.72 0.192 18.744 ;
    END
  END di0[334]
  PIN di0[335]
    DIRECTION INPUT ;
    USE SIGNAL ;
    PORT
      LAYER M4 ;
        RECT  0 18.768 0.192 18.792 ;
    END
  END di0[335]
  PIN di0[336]
    DIRECTION INPUT ;
    USE SIGNAL ;
    PORT
      LAYER M4 ;
        RECT  0 18.816 0.192 18.84 ;
    END
  END di0[336]
  PIN di0[337]
    DIRECTION INPUT ;
    USE SIGNAL ;
    PORT
      LAYER M4 ;
        RECT  0 18.864 0.192 18.888 ;
    END
  END di0[337]
  PIN di0[338]
    DIRECTION INPUT ;
    USE SIGNAL ;
    PORT
      LAYER M4 ;
        RECT  0 18.912 0.192 18.936 ;
    END
  END di0[338]
  PIN di0[339]
    DIRECTION INPUT ;
    USE SIGNAL ;
    PORT
      LAYER M4 ;
        RECT  0 18.96 0.192 18.984 ;
    END
  END di0[339]
  PIN di0[33]
    DIRECTION INPUT ;
    USE SIGNAL ;
    PORT
      LAYER M4 ;
        RECT  0 4.272 0.192 4.296 ;
    END
  END di0[33]
  PIN di0[340]
    DIRECTION INPUT ;
    USE SIGNAL ;
    PORT
      LAYER M4 ;
        RECT  0 19.008 0.192 19.032 ;
    END
  END di0[340]
  PIN di0[341]
    DIRECTION INPUT ;
    USE SIGNAL ;
    PORT
      LAYER M4 ;
        RECT  0 19.056 0.192 19.08 ;
    END
  END di0[341]
  PIN di0[342]
    DIRECTION INPUT ;
    USE SIGNAL ;
    PORT
      LAYER M4 ;
        RECT  0 19.104 0.192 19.128 ;
    END
  END di0[342]
  PIN di0[343]
    DIRECTION INPUT ;
    USE SIGNAL ;
    PORT
      LAYER M4 ;
        RECT  0 19.152 0.192 19.176 ;
    END
  END di0[343]
  PIN di0[344]
    DIRECTION INPUT ;
    USE SIGNAL ;
    PORT
      LAYER M4 ;
        RECT  0 19.2 0.192 19.224 ;
    END
  END di0[344]
  PIN di0[345]
    DIRECTION INPUT ;
    USE SIGNAL ;
    PORT
      LAYER M4 ;
        RECT  0 19.248 0.192 19.272 ;
    END
  END di0[345]
  PIN di0[346]
    DIRECTION INPUT ;
    USE SIGNAL ;
    PORT
      LAYER M4 ;
        RECT  0 19.296 0.192 19.32 ;
    END
  END di0[346]
  PIN di0[347]
    DIRECTION INPUT ;
    USE SIGNAL ;
    PORT
      LAYER M4 ;
        RECT  0 19.344 0.192 19.368 ;
    END
  END di0[347]
  PIN di0[348]
    DIRECTION INPUT ;
    USE SIGNAL ;
    PORT
      LAYER M4 ;
        RECT  0 19.392 0.192 19.416 ;
    END
  END di0[348]
  PIN di0[349]
    DIRECTION INPUT ;
    USE SIGNAL ;
    PORT
      LAYER M4 ;
        RECT  0 19.44 0.192 19.464 ;
    END
  END di0[349]
  PIN di0[34]
    DIRECTION INPUT ;
    USE SIGNAL ;
    PORT
      LAYER M4 ;
        RECT  0 4.32 0.192 4.344 ;
    END
  END di0[34]
  PIN di0[350]
    DIRECTION INPUT ;
    USE SIGNAL ;
    PORT
      LAYER M4 ;
        RECT  0 19.488 0.192 19.512 ;
    END
  END di0[350]
  PIN di0[351]
    DIRECTION INPUT ;
    USE SIGNAL ;
    PORT
      LAYER M4 ;
        RECT  0 19.536 0.192 19.56 ;
    END
  END di0[351]
  PIN di0[352]
    DIRECTION INPUT ;
    USE SIGNAL ;
    PORT
      LAYER M4 ;
        RECT  0 19.584 0.192 19.608 ;
    END
  END di0[352]
  PIN di0[353]
    DIRECTION INPUT ;
    USE SIGNAL ;
    PORT
      LAYER M4 ;
        RECT  0 19.632 0.192 19.656 ;
    END
  END di0[353]
  PIN di0[354]
    DIRECTION INPUT ;
    USE SIGNAL ;
    PORT
      LAYER M4 ;
        RECT  0 19.68 0.192 19.704 ;
    END
  END di0[354]
  PIN di0[355]
    DIRECTION INPUT ;
    USE SIGNAL ;
    PORT
      LAYER M4 ;
        RECT  0 19.728 0.192 19.752 ;
    END
  END di0[355]
  PIN di0[356]
    DIRECTION INPUT ;
    USE SIGNAL ;
    PORT
      LAYER M4 ;
        RECT  0 19.776 0.192 19.8 ;
    END
  END di0[356]
  PIN di0[357]
    DIRECTION INPUT ;
    USE SIGNAL ;
    PORT
      LAYER M4 ;
        RECT  0 19.824 0.192 19.848 ;
    END
  END di0[357]
  PIN di0[358]
    DIRECTION INPUT ;
    USE SIGNAL ;
    PORT
      LAYER M4 ;
        RECT  0 19.872 0.192 19.896 ;
    END
  END di0[358]
  PIN di0[359]
    DIRECTION INPUT ;
    USE SIGNAL ;
    PORT
      LAYER M4 ;
        RECT  0 19.92 0.192 19.944 ;
    END
  END di0[359]
  PIN di0[35]
    DIRECTION INPUT ;
    USE SIGNAL ;
    PORT
      LAYER M4 ;
        RECT  0 4.368 0.192 4.392 ;
    END
  END di0[35]
  PIN di0[360]
    DIRECTION INPUT ;
    USE SIGNAL ;
    PORT
      LAYER M4 ;
        RECT  0 19.968 0.192 19.992 ;
    END
  END di0[360]
  PIN di0[361]
    DIRECTION INPUT ;
    USE SIGNAL ;
    PORT
      LAYER M4 ;
        RECT  0 20.016 0.192 20.04 ;
    END
  END di0[361]
  PIN di0[362]
    DIRECTION INPUT ;
    USE SIGNAL ;
    PORT
      LAYER M4 ;
        RECT  0 20.064 0.192 20.088 ;
    END
  END di0[362]
  PIN di0[363]
    DIRECTION INPUT ;
    USE SIGNAL ;
    PORT
      LAYER M4 ;
        RECT  0 20.112 0.192 20.136 ;
    END
  END di0[363]
  PIN di0[364]
    DIRECTION INPUT ;
    USE SIGNAL ;
    PORT
      LAYER M4 ;
        RECT  0 20.16 0.192 20.184 ;
    END
  END di0[364]
  PIN di0[365]
    DIRECTION INPUT ;
    USE SIGNAL ;
    PORT
      LAYER M4 ;
        RECT  0 20.208 0.192 20.232 ;
    END
  END di0[365]
  PIN di0[366]
    DIRECTION INPUT ;
    USE SIGNAL ;
    PORT
      LAYER M4 ;
        RECT  0 20.256 0.192 20.28 ;
    END
  END di0[366]
  PIN di0[367]
    DIRECTION INPUT ;
    USE SIGNAL ;
    PORT
      LAYER M4 ;
        RECT  0 20.304 0.192 20.328 ;
    END
  END di0[367]
  PIN di0[368]
    DIRECTION INPUT ;
    USE SIGNAL ;
    PORT
      LAYER M4 ;
        RECT  0 20.352 0.192 20.376 ;
    END
  END di0[368]
  PIN di0[369]
    DIRECTION INPUT ;
    USE SIGNAL ;
    PORT
      LAYER M4 ;
        RECT  0 20.4 0.192 20.424 ;
    END
  END di0[369]
  PIN di0[36]
    DIRECTION INPUT ;
    USE SIGNAL ;
    PORT
      LAYER M4 ;
        RECT  0 4.416 0.192 4.44 ;
    END
  END di0[36]
  PIN di0[370]
    DIRECTION INPUT ;
    USE SIGNAL ;
    PORT
      LAYER M4 ;
        RECT  0 20.448 0.192 20.472 ;
    END
  END di0[370]
  PIN di0[371]
    DIRECTION INPUT ;
    USE SIGNAL ;
    PORT
      LAYER M4 ;
        RECT  0 20.496 0.192 20.52 ;
    END
  END di0[371]
  PIN di0[372]
    DIRECTION INPUT ;
    USE SIGNAL ;
    PORT
      LAYER M4 ;
        RECT  0 20.544 0.192 20.568 ;
    END
  END di0[372]
  PIN di0[373]
    DIRECTION INPUT ;
    USE SIGNAL ;
    PORT
      LAYER M4 ;
        RECT  0 20.592 0.192 20.616 ;
    END
  END di0[373]
  PIN di0[374]
    DIRECTION INPUT ;
    USE SIGNAL ;
    PORT
      LAYER M4 ;
        RECT  0 20.64 0.192 20.664 ;
    END
  END di0[374]
  PIN di0[375]
    DIRECTION INPUT ;
    USE SIGNAL ;
    PORT
      LAYER M4 ;
        RECT  0 20.688 0.192 20.712 ;
    END
  END di0[375]
  PIN di0[376]
    DIRECTION INPUT ;
    USE SIGNAL ;
    PORT
      LAYER M4 ;
        RECT  0 20.736 0.192 20.76 ;
    END
  END di0[376]
  PIN di0[377]
    DIRECTION INPUT ;
    USE SIGNAL ;
    PORT
      LAYER M4 ;
        RECT  0 20.784 0.192 20.808 ;
    END
  END di0[377]
  PIN di0[378]
    DIRECTION INPUT ;
    USE SIGNAL ;
    PORT
      LAYER M4 ;
        RECT  0 20.832 0.192 20.856 ;
    END
  END di0[378]
  PIN di0[379]
    DIRECTION INPUT ;
    USE SIGNAL ;
    PORT
      LAYER M4 ;
        RECT  0 20.88 0.192 20.904 ;
    END
  END di0[379]
  PIN di0[37]
    DIRECTION INPUT ;
    USE SIGNAL ;
    PORT
      LAYER M4 ;
        RECT  0 4.464 0.192 4.488 ;
    END
  END di0[37]
  PIN di0[380]
    DIRECTION INPUT ;
    USE SIGNAL ;
    PORT
      LAYER M4 ;
        RECT  0 20.928 0.192 20.952 ;
    END
  END di0[380]
  PIN di0[381]
    DIRECTION INPUT ;
    USE SIGNAL ;
    PORT
      LAYER M4 ;
        RECT  0 20.976 0.192 21 ;
    END
  END di0[381]
  PIN di0[382]
    DIRECTION INPUT ;
    USE SIGNAL ;
    PORT
      LAYER M4 ;
        RECT  0 21.024 0.192 21.048 ;
    END
  END di0[382]
  PIN di0[383]
    DIRECTION INPUT ;
    USE SIGNAL ;
    PORT
      LAYER M4 ;
        RECT  0 21.072 0.192 21.096 ;
    END
  END di0[383]
  PIN di0[384]
    DIRECTION INPUT ;
    USE SIGNAL ;
    PORT
      LAYER M4 ;
        RECT  0 21.12 0.192 21.144 ;
    END
  END di0[384]
  PIN di0[385]
    DIRECTION INPUT ;
    USE SIGNAL ;
    PORT
      LAYER M4 ;
        RECT  0 21.168 0.192 21.192 ;
    END
  END di0[385]
  PIN di0[386]
    DIRECTION INPUT ;
    USE SIGNAL ;
    PORT
      LAYER M4 ;
        RECT  0 21.216 0.192 21.24 ;
    END
  END di0[386]
  PIN di0[387]
    DIRECTION INPUT ;
    USE SIGNAL ;
    PORT
      LAYER M4 ;
        RECT  0 21.264 0.192 21.288 ;
    END
  END di0[387]
  PIN di0[388]
    DIRECTION INPUT ;
    USE SIGNAL ;
    PORT
      LAYER M4 ;
        RECT  0 21.312 0.192 21.336 ;
    END
  END di0[388]
  PIN di0[389]
    DIRECTION INPUT ;
    USE SIGNAL ;
    PORT
      LAYER M4 ;
        RECT  0 21.36 0.192 21.384 ;
    END
  END di0[389]
  PIN di0[38]
    DIRECTION INPUT ;
    USE SIGNAL ;
    PORT
      LAYER M4 ;
        RECT  0 4.512 0.192 4.536 ;
    END
  END di0[38]
  PIN di0[390]
    DIRECTION INPUT ;
    USE SIGNAL ;
    PORT
      LAYER M4 ;
        RECT  0 21.408 0.192 21.432 ;
    END
  END di0[390]
  PIN di0[391]
    DIRECTION INPUT ;
    USE SIGNAL ;
    PORT
      LAYER M4 ;
        RECT  0 21.456 0.192 21.48 ;
    END
  END di0[391]
  PIN di0[392]
    DIRECTION INPUT ;
    USE SIGNAL ;
    PORT
      LAYER M4 ;
        RECT  0 21.504 0.192 21.528 ;
    END
  END di0[392]
  PIN di0[393]
    DIRECTION INPUT ;
    USE SIGNAL ;
    PORT
      LAYER M4 ;
        RECT  0 21.552 0.192 21.576 ;
    END
  END di0[393]
  PIN di0[394]
    DIRECTION INPUT ;
    USE SIGNAL ;
    PORT
      LAYER M4 ;
        RECT  0 21.6 0.192 21.624 ;
    END
  END di0[394]
  PIN di0[395]
    DIRECTION INPUT ;
    USE SIGNAL ;
    PORT
      LAYER M4 ;
        RECT  0 21.648 0.192 21.672 ;
    END
  END di0[395]
  PIN di0[396]
    DIRECTION INPUT ;
    USE SIGNAL ;
    PORT
      LAYER M4 ;
        RECT  0 21.696 0.192 21.72 ;
    END
  END di0[396]
  PIN di0[397]
    DIRECTION INPUT ;
    USE SIGNAL ;
    PORT
      LAYER M4 ;
        RECT  0 21.744 0.192 21.768 ;
    END
  END di0[397]
  PIN di0[398]
    DIRECTION INPUT ;
    USE SIGNAL ;
    PORT
      LAYER M4 ;
        RECT  0 21.792 0.192 21.816 ;
    END
  END di0[398]
  PIN di0[399]
    DIRECTION INPUT ;
    USE SIGNAL ;
    PORT
      LAYER M4 ;
        RECT  0 21.84 0.192 21.864 ;
    END
  END di0[399]
  PIN di0[39]
    DIRECTION INPUT ;
    USE SIGNAL ;
    PORT
      LAYER M4 ;
        RECT  0 4.56 0.192 4.584 ;
    END
  END di0[39]
  PIN di0[3]
    DIRECTION INPUT ;
    USE SIGNAL ;
    PORT
      LAYER M4 ;
        RECT  0 2.832 0.192 2.856 ;
    END
  END di0[3]
  PIN di0[400]
    DIRECTION INPUT ;
    USE SIGNAL ;
    PORT
      LAYER M4 ;
        RECT  0 21.888 0.192 21.912 ;
    END
  END di0[400]
  PIN di0[401]
    DIRECTION INPUT ;
    USE SIGNAL ;
    PORT
      LAYER M4 ;
        RECT  0 21.936 0.192 21.96 ;
    END
  END di0[401]
  PIN di0[402]
    DIRECTION INPUT ;
    USE SIGNAL ;
    PORT
      LAYER M4 ;
        RECT  0 21.984 0.192 22.008 ;
    END
  END di0[402]
  PIN di0[403]
    DIRECTION INPUT ;
    USE SIGNAL ;
    PORT
      LAYER M4 ;
        RECT  0 22.032 0.192 22.056 ;
    END
  END di0[403]
  PIN di0[404]
    DIRECTION INPUT ;
    USE SIGNAL ;
    PORT
      LAYER M4 ;
        RECT  0 22.08 0.192 22.104 ;
    END
  END di0[404]
  PIN di0[405]
    DIRECTION INPUT ;
    USE SIGNAL ;
    PORT
      LAYER M4 ;
        RECT  0 22.128 0.192 22.152 ;
    END
  END di0[405]
  PIN di0[406]
    DIRECTION INPUT ;
    USE SIGNAL ;
    PORT
      LAYER M4 ;
        RECT  0 22.176 0.192 22.2 ;
    END
  END di0[406]
  PIN di0[407]
    DIRECTION INPUT ;
    USE SIGNAL ;
    PORT
      LAYER M4 ;
        RECT  0 22.224 0.192 22.248 ;
    END
  END di0[407]
  PIN di0[408]
    DIRECTION INPUT ;
    USE SIGNAL ;
    PORT
      LAYER M4 ;
        RECT  0 22.272 0.192 22.296 ;
    END
  END di0[408]
  PIN di0[409]
    DIRECTION INPUT ;
    USE SIGNAL ;
    PORT
      LAYER M4 ;
        RECT  0 22.32 0.192 22.344 ;
    END
  END di0[409]
  PIN di0[40]
    DIRECTION INPUT ;
    USE SIGNAL ;
    PORT
      LAYER M4 ;
        RECT  0 4.608 0.192 4.632 ;
    END
  END di0[40]
  PIN di0[410]
    DIRECTION INPUT ;
    USE SIGNAL ;
    PORT
      LAYER M4 ;
        RECT  0 22.368 0.192 22.392 ;
    END
  END di0[410]
  PIN di0[411]
    DIRECTION INPUT ;
    USE SIGNAL ;
    PORT
      LAYER M4 ;
        RECT  0 22.416 0.192 22.44 ;
    END
  END di0[411]
  PIN di0[412]
    DIRECTION INPUT ;
    USE SIGNAL ;
    PORT
      LAYER M4 ;
        RECT  0 22.464 0.192 22.488 ;
    END
  END di0[412]
  PIN di0[413]
    DIRECTION INPUT ;
    USE SIGNAL ;
    PORT
      LAYER M4 ;
        RECT  0 22.512 0.192 22.536 ;
    END
  END di0[413]
  PIN di0[414]
    DIRECTION INPUT ;
    USE SIGNAL ;
    PORT
      LAYER M4 ;
        RECT  0 22.56 0.192 22.584 ;
    END
  END di0[414]
  PIN di0[415]
    DIRECTION INPUT ;
    USE SIGNAL ;
    PORT
      LAYER M4 ;
        RECT  0 22.608 0.192 22.632 ;
    END
  END di0[415]
  PIN di0[416]
    DIRECTION INPUT ;
    USE SIGNAL ;
    PORT
      LAYER M4 ;
        RECT  0 22.656 0.192 22.68 ;
    END
  END di0[416]
  PIN di0[417]
    DIRECTION INPUT ;
    USE SIGNAL ;
    PORT
      LAYER M4 ;
        RECT  0 22.704 0.192 22.728 ;
    END
  END di0[417]
  PIN di0[418]
    DIRECTION INPUT ;
    USE SIGNAL ;
    PORT
      LAYER M4 ;
        RECT  0 22.752 0.192 22.776 ;
    END
  END di0[418]
  PIN di0[419]
    DIRECTION INPUT ;
    USE SIGNAL ;
    PORT
      LAYER M4 ;
        RECT  0 22.8 0.192 22.824 ;
    END
  END di0[419]
  PIN di0[41]
    DIRECTION INPUT ;
    USE SIGNAL ;
    PORT
      LAYER M4 ;
        RECT  0 4.656 0.192 4.68 ;
    END
  END di0[41]
  PIN di0[420]
    DIRECTION INPUT ;
    USE SIGNAL ;
    PORT
      LAYER M4 ;
        RECT  0 22.848 0.192 22.872 ;
    END
  END di0[420]
  PIN di0[421]
    DIRECTION INPUT ;
    USE SIGNAL ;
    PORT
      LAYER M4 ;
        RECT  0 22.896 0.192 22.92 ;
    END
  END di0[421]
  PIN di0[422]
    DIRECTION INPUT ;
    USE SIGNAL ;
    PORT
      LAYER M4 ;
        RECT  0 22.944 0.192 22.968 ;
    END
  END di0[422]
  PIN di0[423]
    DIRECTION INPUT ;
    USE SIGNAL ;
    PORT
      LAYER M4 ;
        RECT  0 22.992 0.192 23.016 ;
    END
  END di0[423]
  PIN di0[424]
    DIRECTION INPUT ;
    USE SIGNAL ;
    PORT
      LAYER M4 ;
        RECT  0 23.04 0.192 23.064 ;
    END
  END di0[424]
  PIN di0[425]
    DIRECTION INPUT ;
    USE SIGNAL ;
    PORT
      LAYER M4 ;
        RECT  0 23.088 0.192 23.112 ;
    END
  END di0[425]
  PIN di0[426]
    DIRECTION INPUT ;
    USE SIGNAL ;
    PORT
      LAYER M4 ;
        RECT  0 23.136 0.192 23.16 ;
    END
  END di0[426]
  PIN di0[427]
    DIRECTION INPUT ;
    USE SIGNAL ;
    PORT
      LAYER M4 ;
        RECT  0 23.184 0.192 23.208 ;
    END
  END di0[427]
  PIN di0[428]
    DIRECTION INPUT ;
    USE SIGNAL ;
    PORT
      LAYER M4 ;
        RECT  0 23.232 0.192 23.256 ;
    END
  END di0[428]
  PIN di0[429]
    DIRECTION INPUT ;
    USE SIGNAL ;
    PORT
      LAYER M4 ;
        RECT  0 23.28 0.192 23.304 ;
    END
  END di0[429]
  PIN di0[42]
    DIRECTION INPUT ;
    USE SIGNAL ;
    PORT
      LAYER M4 ;
        RECT  0 4.704 0.192 4.728 ;
    END
  END di0[42]
  PIN di0[430]
    DIRECTION INPUT ;
    USE SIGNAL ;
    PORT
      LAYER M4 ;
        RECT  0 23.328 0.192 23.352 ;
    END
  END di0[430]
  PIN di0[431]
    DIRECTION INPUT ;
    USE SIGNAL ;
    PORT
      LAYER M4 ;
        RECT  0 23.376 0.192 23.4 ;
    END
  END di0[431]
  PIN di0[432]
    DIRECTION INPUT ;
    USE SIGNAL ;
    PORT
      LAYER M4 ;
        RECT  0 23.424 0.192 23.448 ;
    END
  END di0[432]
  PIN di0[433]
    DIRECTION INPUT ;
    USE SIGNAL ;
    PORT
      LAYER M4 ;
        RECT  0 23.472 0.192 23.496 ;
    END
  END di0[433]
  PIN di0[434]
    DIRECTION INPUT ;
    USE SIGNAL ;
    PORT
      LAYER M4 ;
        RECT  0 23.52 0.192 23.544 ;
    END
  END di0[434]
  PIN di0[435]
    DIRECTION INPUT ;
    USE SIGNAL ;
    PORT
      LAYER M4 ;
        RECT  0 23.568 0.192 23.592 ;
    END
  END di0[435]
  PIN di0[436]
    DIRECTION INPUT ;
    USE SIGNAL ;
    PORT
      LAYER M4 ;
        RECT  0 23.616 0.192 23.64 ;
    END
  END di0[436]
  PIN di0[437]
    DIRECTION INPUT ;
    USE SIGNAL ;
    PORT
      LAYER M4 ;
        RECT  0 23.664 0.192 23.688 ;
    END
  END di0[437]
  PIN di0[438]
    DIRECTION INPUT ;
    USE SIGNAL ;
    PORT
      LAYER M4 ;
        RECT  0 23.712 0.192 23.736 ;
    END
  END di0[438]
  PIN di0[439]
    DIRECTION INPUT ;
    USE SIGNAL ;
    PORT
      LAYER M4 ;
        RECT  0 23.76 0.192 23.784 ;
    END
  END di0[439]
  PIN di0[43]
    DIRECTION INPUT ;
    USE SIGNAL ;
    PORT
      LAYER M4 ;
        RECT  0 4.752 0.192 4.776 ;
    END
  END di0[43]
  PIN di0[440]
    DIRECTION INPUT ;
    USE SIGNAL ;
    PORT
      LAYER M4 ;
        RECT  0 23.808 0.192 23.832 ;
    END
  END di0[440]
  PIN di0[441]
    DIRECTION INPUT ;
    USE SIGNAL ;
    PORT
      LAYER M4 ;
        RECT  0 23.856 0.192 23.88 ;
    END
  END di0[441]
  PIN di0[442]
    DIRECTION INPUT ;
    USE SIGNAL ;
    PORT
      LAYER M4 ;
        RECT  0 23.904 0.192 23.928 ;
    END
  END di0[442]
  PIN di0[443]
    DIRECTION INPUT ;
    USE SIGNAL ;
    PORT
      LAYER M4 ;
        RECT  0 23.952 0.192 23.976 ;
    END
  END di0[443]
  PIN di0[444]
    DIRECTION INPUT ;
    USE SIGNAL ;
    PORT
      LAYER M4 ;
        RECT  0 24 0.192 24.024 ;
    END
  END di0[444]
  PIN di0[445]
    DIRECTION INPUT ;
    USE SIGNAL ;
    PORT
      LAYER M4 ;
        RECT  0 24.048 0.192 24.072 ;
    END
  END di0[445]
  PIN di0[446]
    DIRECTION INPUT ;
    USE SIGNAL ;
    PORT
      LAYER M4 ;
        RECT  0 24.096 0.192 24.12 ;
    END
  END di0[446]
  PIN di0[447]
    DIRECTION INPUT ;
    USE SIGNAL ;
    PORT
      LAYER M4 ;
        RECT  0 24.144 0.192 24.168 ;
    END
  END di0[447]
  PIN di0[448]
    DIRECTION INPUT ;
    USE SIGNAL ;
    PORT
      LAYER M4 ;
        RECT  0 24.192 0.192 24.216 ;
    END
  END di0[448]
  PIN di0[449]
    DIRECTION INPUT ;
    USE SIGNAL ;
    PORT
      LAYER M4 ;
        RECT  0 24.24 0.192 24.264 ;
    END
  END di0[449]
  PIN di0[44]
    DIRECTION INPUT ;
    USE SIGNAL ;
    PORT
      LAYER M4 ;
        RECT  0 4.8 0.192 4.824 ;
    END
  END di0[44]
  PIN di0[450]
    DIRECTION INPUT ;
    USE SIGNAL ;
    PORT
      LAYER M4 ;
        RECT  0 24.288 0.192 24.312 ;
    END
  END di0[450]
  PIN di0[451]
    DIRECTION INPUT ;
    USE SIGNAL ;
    PORT
      LAYER M4 ;
        RECT  0 24.336 0.192 24.36 ;
    END
  END di0[451]
  PIN di0[452]
    DIRECTION INPUT ;
    USE SIGNAL ;
    PORT
      LAYER M4 ;
        RECT  0 24.384 0.192 24.408 ;
    END
  END di0[452]
  PIN di0[453]
    DIRECTION INPUT ;
    USE SIGNAL ;
    PORT
      LAYER M4 ;
        RECT  0 24.432 0.192 24.456 ;
    END
  END di0[453]
  PIN di0[454]
    DIRECTION INPUT ;
    USE SIGNAL ;
    PORT
      LAYER M4 ;
        RECT  0 24.48 0.192 24.504 ;
    END
  END di0[454]
  PIN di0[455]
    DIRECTION INPUT ;
    USE SIGNAL ;
    PORT
      LAYER M4 ;
        RECT  0 24.528 0.192 24.552 ;
    END
  END di0[455]
  PIN di0[456]
    DIRECTION INPUT ;
    USE SIGNAL ;
    PORT
      LAYER M4 ;
        RECT  0 24.576 0.192 24.6 ;
    END
  END di0[456]
  PIN di0[457]
    DIRECTION INPUT ;
    USE SIGNAL ;
    PORT
      LAYER M4 ;
        RECT  0 24.624 0.192 24.648 ;
    END
  END di0[457]
  PIN di0[458]
    DIRECTION INPUT ;
    USE SIGNAL ;
    PORT
      LAYER M4 ;
        RECT  0 24.672 0.192 24.696 ;
    END
  END di0[458]
  PIN di0[459]
    DIRECTION INPUT ;
    USE SIGNAL ;
    PORT
      LAYER M4 ;
        RECT  0 24.72 0.192 24.744 ;
    END
  END di0[459]
  PIN di0[45]
    DIRECTION INPUT ;
    USE SIGNAL ;
    PORT
      LAYER M4 ;
        RECT  0 4.848 0.192 4.872 ;
    END
  END di0[45]
  PIN di0[460]
    DIRECTION INPUT ;
    USE SIGNAL ;
    PORT
      LAYER M4 ;
        RECT  0 24.768 0.192 24.792 ;
    END
  END di0[460]
  PIN di0[461]
    DIRECTION INPUT ;
    USE SIGNAL ;
    PORT
      LAYER M4 ;
        RECT  0 24.816 0.192 24.84 ;
    END
  END di0[461]
  PIN di0[462]
    DIRECTION INPUT ;
    USE SIGNAL ;
    PORT
      LAYER M4 ;
        RECT  0 24.864 0.192 24.888 ;
    END
  END di0[462]
  PIN di0[463]
    DIRECTION INPUT ;
    USE SIGNAL ;
    PORT
      LAYER M4 ;
        RECT  0 24.912 0.192 24.936 ;
    END
  END di0[463]
  PIN di0[464]
    DIRECTION INPUT ;
    USE SIGNAL ;
    PORT
      LAYER M4 ;
        RECT  0 24.96 0.192 24.984 ;
    END
  END di0[464]
  PIN di0[465]
    DIRECTION INPUT ;
    USE SIGNAL ;
    PORT
      LAYER M4 ;
        RECT  0 25.008 0.192 25.032 ;
    END
  END di0[465]
  PIN di0[466]
    DIRECTION INPUT ;
    USE SIGNAL ;
    PORT
      LAYER M4 ;
        RECT  0 25.056 0.192 25.08 ;
    END
  END di0[466]
  PIN di0[467]
    DIRECTION INPUT ;
    USE SIGNAL ;
    PORT
      LAYER M4 ;
        RECT  0 25.104 0.192 25.128 ;
    END
  END di0[467]
  PIN di0[468]
    DIRECTION INPUT ;
    USE SIGNAL ;
    PORT
      LAYER M4 ;
        RECT  0 25.152 0.192 25.176 ;
    END
  END di0[468]
  PIN di0[469]
    DIRECTION INPUT ;
    USE SIGNAL ;
    PORT
      LAYER M4 ;
        RECT  0 25.2 0.192 25.224 ;
    END
  END di0[469]
  PIN di0[46]
    DIRECTION INPUT ;
    USE SIGNAL ;
    PORT
      LAYER M4 ;
        RECT  0 4.896 0.192 4.92 ;
    END
  END di0[46]
  PIN di0[470]
    DIRECTION INPUT ;
    USE SIGNAL ;
    PORT
      LAYER M4 ;
        RECT  0 25.248 0.192 25.272 ;
    END
  END di0[470]
  PIN di0[471]
    DIRECTION INPUT ;
    USE SIGNAL ;
    PORT
      LAYER M4 ;
        RECT  0 25.296 0.192 25.32 ;
    END
  END di0[471]
  PIN di0[472]
    DIRECTION INPUT ;
    USE SIGNAL ;
    PORT
      LAYER M4 ;
        RECT  0 25.344 0.192 25.368 ;
    END
  END di0[472]
  PIN di0[473]
    DIRECTION INPUT ;
    USE SIGNAL ;
    PORT
      LAYER M4 ;
        RECT  0 25.392 0.192 25.416 ;
    END
  END di0[473]
  PIN di0[474]
    DIRECTION INPUT ;
    USE SIGNAL ;
    PORT
      LAYER M4 ;
        RECT  0 25.44 0.192 25.464 ;
    END
  END di0[474]
  PIN di0[475]
    DIRECTION INPUT ;
    USE SIGNAL ;
    PORT
      LAYER M4 ;
        RECT  0 25.488 0.192 25.512 ;
    END
  END di0[475]
  PIN di0[476]
    DIRECTION INPUT ;
    USE SIGNAL ;
    PORT
      LAYER M4 ;
        RECT  0 25.536 0.192 25.56 ;
    END
  END di0[476]
  PIN di0[477]
    DIRECTION INPUT ;
    USE SIGNAL ;
    PORT
      LAYER M4 ;
        RECT  0 25.584 0.192 25.608 ;
    END
  END di0[477]
  PIN di0[478]
    DIRECTION INPUT ;
    USE SIGNAL ;
    PORT
      LAYER M4 ;
        RECT  0 25.632 0.192 25.656 ;
    END
  END di0[478]
  PIN di0[479]
    DIRECTION INPUT ;
    USE SIGNAL ;
    PORT
      LAYER M4 ;
        RECT  0 25.68 0.192 25.704 ;
    END
  END di0[479]
  PIN di0[47]
    DIRECTION INPUT ;
    USE SIGNAL ;
    PORT
      LAYER M4 ;
        RECT  0 4.944 0.192 4.968 ;
    END
  END di0[47]
  PIN di0[480]
    DIRECTION INPUT ;
    USE SIGNAL ;
    PORT
      LAYER M4 ;
        RECT  0 25.728 0.192 25.752 ;
    END
  END di0[480]
  PIN di0[481]
    DIRECTION INPUT ;
    USE SIGNAL ;
    PORT
      LAYER M4 ;
        RECT  0 25.776 0.192 25.8 ;
    END
  END di0[481]
  PIN di0[482]
    DIRECTION INPUT ;
    USE SIGNAL ;
    PORT
      LAYER M4 ;
        RECT  0 25.824 0.192 25.848 ;
    END
  END di0[482]
  PIN di0[483]
    DIRECTION INPUT ;
    USE SIGNAL ;
    PORT
      LAYER M4 ;
        RECT  0 25.872 0.192 25.896 ;
    END
  END di0[483]
  PIN di0[484]
    DIRECTION INPUT ;
    USE SIGNAL ;
    PORT
      LAYER M4 ;
        RECT  0 25.92 0.192 25.944 ;
    END
  END di0[484]
  PIN di0[485]
    DIRECTION INPUT ;
    USE SIGNAL ;
    PORT
      LAYER M4 ;
        RECT  0 25.968 0.192 25.992 ;
    END
  END di0[485]
  PIN di0[486]
    DIRECTION INPUT ;
    USE SIGNAL ;
    PORT
      LAYER M4 ;
        RECT  0 26.016 0.192 26.04 ;
    END
  END di0[486]
  PIN di0[487]
    DIRECTION INPUT ;
    USE SIGNAL ;
    PORT
      LAYER M4 ;
        RECT  0 26.064 0.192 26.088 ;
    END
  END di0[487]
  PIN di0[488]
    DIRECTION INPUT ;
    USE SIGNAL ;
    PORT
      LAYER M4 ;
        RECT  0 26.112 0.192 26.136 ;
    END
  END di0[488]
  PIN di0[489]
    DIRECTION INPUT ;
    USE SIGNAL ;
    PORT
      LAYER M4 ;
        RECT  0 26.16 0.192 26.184 ;
    END
  END di0[489]
  PIN di0[48]
    DIRECTION INPUT ;
    USE SIGNAL ;
    PORT
      LAYER M4 ;
        RECT  0 4.992 0.192 5.016 ;
    END
  END di0[48]
  PIN di0[490]
    DIRECTION INPUT ;
    USE SIGNAL ;
    PORT
      LAYER M4 ;
        RECT  0 26.208 0.192 26.232 ;
    END
  END di0[490]
  PIN di0[491]
    DIRECTION INPUT ;
    USE SIGNAL ;
    PORT
      LAYER M4 ;
        RECT  0 26.256 0.192 26.28 ;
    END
  END di0[491]
  PIN di0[492]
    DIRECTION INPUT ;
    USE SIGNAL ;
    PORT
      LAYER M4 ;
        RECT  0 26.304 0.192 26.328 ;
    END
  END di0[492]
  PIN di0[493]
    DIRECTION INPUT ;
    USE SIGNAL ;
    PORT
      LAYER M4 ;
        RECT  0 26.352 0.192 26.376 ;
    END
  END di0[493]
  PIN di0[494]
    DIRECTION INPUT ;
    USE SIGNAL ;
    PORT
      LAYER M4 ;
        RECT  0 26.4 0.192 26.424 ;
    END
  END di0[494]
  PIN di0[495]
    DIRECTION INPUT ;
    USE SIGNAL ;
    PORT
      LAYER M4 ;
        RECT  0 26.448 0.192 26.472 ;
    END
  END di0[495]
  PIN di0[496]
    DIRECTION INPUT ;
    USE SIGNAL ;
    PORT
      LAYER M4 ;
        RECT  0 26.496 0.192 26.52 ;
    END
  END di0[496]
  PIN di0[497]
    DIRECTION INPUT ;
    USE SIGNAL ;
    PORT
      LAYER M4 ;
        RECT  0 26.544 0.192 26.568 ;
    END
  END di0[497]
  PIN di0[498]
    DIRECTION INPUT ;
    USE SIGNAL ;
    PORT
      LAYER M4 ;
        RECT  0 26.592 0.192 26.616 ;
    END
  END di0[498]
  PIN di0[499]
    DIRECTION INPUT ;
    USE SIGNAL ;
    PORT
      LAYER M4 ;
        RECT  0 26.64 0.192 26.664 ;
    END
  END di0[499]
  PIN di0[49]
    DIRECTION INPUT ;
    USE SIGNAL ;
    PORT
      LAYER M4 ;
        RECT  0 5.04 0.192 5.064 ;
    END
  END di0[49]
  PIN di0[4]
    DIRECTION INPUT ;
    USE SIGNAL ;
    PORT
      LAYER M4 ;
        RECT  0 2.88 0.192 2.904 ;
    END
  END di0[4]
  PIN di0[500]
    DIRECTION INPUT ;
    USE SIGNAL ;
    PORT
      LAYER M4 ;
        RECT  0 26.688 0.192 26.712 ;
    END
  END di0[500]
  PIN di0[501]
    DIRECTION INPUT ;
    USE SIGNAL ;
    PORT
      LAYER M4 ;
        RECT  0 26.736 0.192 26.76 ;
    END
  END di0[501]
  PIN di0[502]
    DIRECTION INPUT ;
    USE SIGNAL ;
    PORT
      LAYER M4 ;
        RECT  0 26.784 0.192 26.808 ;
    END
  END di0[502]
  PIN di0[503]
    DIRECTION INPUT ;
    USE SIGNAL ;
    PORT
      LAYER M4 ;
        RECT  0 26.832 0.192 26.856 ;
    END
  END di0[503]
  PIN di0[504]
    DIRECTION INPUT ;
    USE SIGNAL ;
    PORT
      LAYER M4 ;
        RECT  0 26.88 0.192 26.904 ;
    END
  END di0[504]
  PIN di0[505]
    DIRECTION INPUT ;
    USE SIGNAL ;
    PORT
      LAYER M4 ;
        RECT  0 26.928 0.192 26.952 ;
    END
  END di0[505]
  PIN di0[506]
    DIRECTION INPUT ;
    USE SIGNAL ;
    PORT
      LAYER M4 ;
        RECT  0 26.976 0.192 27 ;
    END
  END di0[506]
  PIN di0[507]
    DIRECTION INPUT ;
    USE SIGNAL ;
    PORT
      LAYER M4 ;
        RECT  0 27.024 0.192 27.048 ;
    END
  END di0[507]
  PIN di0[508]
    DIRECTION INPUT ;
    USE SIGNAL ;
    PORT
      LAYER M4 ;
        RECT  0 27.072 0.192 27.096 ;
    END
  END di0[508]
  PIN di0[509]
    DIRECTION INPUT ;
    USE SIGNAL ;
    PORT
      LAYER M4 ;
        RECT  0 27.12 0.192 27.144 ;
    END
  END di0[509]
  PIN di0[50]
    DIRECTION INPUT ;
    USE SIGNAL ;
    PORT
      LAYER M4 ;
        RECT  0 5.088 0.192 5.112 ;
    END
  END di0[50]
  PIN di0[510]
    DIRECTION INPUT ;
    USE SIGNAL ;
    PORT
      LAYER M4 ;
        RECT  0 27.168 0.192 27.192 ;
    END
  END di0[510]
  PIN di0[511]
    DIRECTION INPUT ;
    USE SIGNAL ;
    PORT
      LAYER M4 ;
        RECT  0 27.216 0.192 27.24 ;
    END
  END di0[511]
  PIN di0[512]
    DIRECTION INPUT ;
    USE SIGNAL ;
    PORT
      LAYER M4 ;
        RECT  0 27.264 0.192 27.288 ;
    END
  END di0[512]
  PIN di0[513]
    DIRECTION INPUT ;
    USE SIGNAL ;
    PORT
      LAYER M4 ;
        RECT  0 27.312 0.192 27.336 ;
    END
  END di0[513]
  PIN di0[514]
    DIRECTION INPUT ;
    USE SIGNAL ;
    PORT
      LAYER M4 ;
        RECT  0 27.36 0.192 27.384 ;
    END
  END di0[514]
  PIN di0[515]
    DIRECTION INPUT ;
    USE SIGNAL ;
    PORT
      LAYER M4 ;
        RECT  0 27.408 0.192 27.432 ;
    END
  END di0[515]
  PIN di0[516]
    DIRECTION INPUT ;
    USE SIGNAL ;
    PORT
      LAYER M4 ;
        RECT  0 27.456 0.192 27.48 ;
    END
  END di0[516]
  PIN di0[517]
    DIRECTION INPUT ;
    USE SIGNAL ;
    PORT
      LAYER M4 ;
        RECT  0 27.504 0.192 27.528 ;
    END
  END di0[517]
  PIN di0[518]
    DIRECTION INPUT ;
    USE SIGNAL ;
    PORT
      LAYER M4 ;
        RECT  0 27.552 0.192 27.576 ;
    END
  END di0[518]
  PIN di0[519]
    DIRECTION INPUT ;
    USE SIGNAL ;
    PORT
      LAYER M4 ;
        RECT  0 27.6 0.192 27.624 ;
    END
  END di0[519]
  PIN di0[51]
    DIRECTION INPUT ;
    USE SIGNAL ;
    PORT
      LAYER M4 ;
        RECT  0 5.136 0.192 5.16 ;
    END
  END di0[51]
  PIN di0[520]
    DIRECTION INPUT ;
    USE SIGNAL ;
    PORT
      LAYER M4 ;
        RECT  0 27.648 0.192 27.672 ;
    END
  END di0[520]
  PIN di0[521]
    DIRECTION INPUT ;
    USE SIGNAL ;
    PORT
      LAYER M4 ;
        RECT  0 27.696 0.192 27.72 ;
    END
  END di0[521]
  PIN di0[522]
    DIRECTION INPUT ;
    USE SIGNAL ;
    PORT
      LAYER M4 ;
        RECT  0 27.744 0.192 27.768 ;
    END
  END di0[522]
  PIN di0[523]
    DIRECTION INPUT ;
    USE SIGNAL ;
    PORT
      LAYER M4 ;
        RECT  0 27.792 0.192 27.816 ;
    END
  END di0[523]
  PIN di0[524]
    DIRECTION INPUT ;
    USE SIGNAL ;
    PORT
      LAYER M4 ;
        RECT  0 27.84 0.192 27.864 ;
    END
  END di0[524]
  PIN di0[525]
    DIRECTION INPUT ;
    USE SIGNAL ;
    PORT
      LAYER M4 ;
        RECT  0 27.888 0.192 27.912 ;
    END
  END di0[525]
  PIN di0[526]
    DIRECTION INPUT ;
    USE SIGNAL ;
    PORT
      LAYER M4 ;
        RECT  0 27.936 0.192 27.96 ;
    END
  END di0[526]
  PIN di0[527]
    DIRECTION INPUT ;
    USE SIGNAL ;
    PORT
      LAYER M4 ;
        RECT  0 27.984 0.192 28.008 ;
    END
  END di0[527]
  PIN di0[528]
    DIRECTION INPUT ;
    USE SIGNAL ;
    PORT
      LAYER M4 ;
        RECT  0 28.032 0.192 28.056 ;
    END
  END di0[528]
  PIN di0[529]
    DIRECTION INPUT ;
    USE SIGNAL ;
    PORT
      LAYER M4 ;
        RECT  0 28.08 0.192 28.104 ;
    END
  END di0[529]
  PIN di0[52]
    DIRECTION INPUT ;
    USE SIGNAL ;
    PORT
      LAYER M4 ;
        RECT  0 5.184 0.192 5.208 ;
    END
  END di0[52]
  PIN di0[530]
    DIRECTION INPUT ;
    USE SIGNAL ;
    PORT
      LAYER M4 ;
        RECT  0 28.128 0.192 28.152 ;
    END
  END di0[530]
  PIN di0[531]
    DIRECTION INPUT ;
    USE SIGNAL ;
    PORT
      LAYER M4 ;
        RECT  0 28.176 0.192 28.2 ;
    END
  END di0[531]
  PIN di0[532]
    DIRECTION INPUT ;
    USE SIGNAL ;
    PORT
      LAYER M4 ;
        RECT  0 28.224 0.192 28.248 ;
    END
  END di0[532]
  PIN di0[533]
    DIRECTION INPUT ;
    USE SIGNAL ;
    PORT
      LAYER M4 ;
        RECT  0 28.272 0.192 28.296 ;
    END
  END di0[533]
  PIN di0[534]
    DIRECTION INPUT ;
    USE SIGNAL ;
    PORT
      LAYER M4 ;
        RECT  0 28.32 0.192 28.344 ;
    END
  END di0[534]
  PIN di0[535]
    DIRECTION INPUT ;
    USE SIGNAL ;
    PORT
      LAYER M4 ;
        RECT  0 28.368 0.192 28.392 ;
    END
  END di0[535]
  PIN di0[536]
    DIRECTION INPUT ;
    USE SIGNAL ;
    PORT
      LAYER M4 ;
        RECT  0 28.416 0.192 28.44 ;
    END
  END di0[536]
  PIN di0[537]
    DIRECTION INPUT ;
    USE SIGNAL ;
    PORT
      LAYER M4 ;
        RECT  0 28.464 0.192 28.488 ;
    END
  END di0[537]
  PIN di0[538]
    DIRECTION INPUT ;
    USE SIGNAL ;
    PORT
      LAYER M4 ;
        RECT  0 28.512 0.192 28.536 ;
    END
  END di0[538]
  PIN di0[539]
    DIRECTION INPUT ;
    USE SIGNAL ;
    PORT
      LAYER M4 ;
        RECT  0 28.56 0.192 28.584 ;
    END
  END di0[539]
  PIN di0[53]
    DIRECTION INPUT ;
    USE SIGNAL ;
    PORT
      LAYER M4 ;
        RECT  0 5.232 0.192 5.256 ;
    END
  END di0[53]
  PIN di0[540]
    DIRECTION INPUT ;
    USE SIGNAL ;
    PORT
      LAYER M4 ;
        RECT  0 28.608 0.192 28.632 ;
    END
  END di0[540]
  PIN di0[541]
    DIRECTION INPUT ;
    USE SIGNAL ;
    PORT
      LAYER M4 ;
        RECT  0 28.656 0.192 28.68 ;
    END
  END di0[541]
  PIN di0[542]
    DIRECTION INPUT ;
    USE SIGNAL ;
    PORT
      LAYER M4 ;
        RECT  0 28.704 0.192 28.728 ;
    END
  END di0[542]
  PIN di0[543]
    DIRECTION INPUT ;
    USE SIGNAL ;
    PORT
      LAYER M4 ;
        RECT  0 28.752 0.192 28.776 ;
    END
  END di0[543]
  PIN di0[544]
    DIRECTION INPUT ;
    USE SIGNAL ;
    PORT
      LAYER M4 ;
        RECT  0 28.8 0.192 28.824 ;
    END
  END di0[544]
  PIN di0[545]
    DIRECTION INPUT ;
    USE SIGNAL ;
    PORT
      LAYER M4 ;
        RECT  0 28.848 0.192 28.872 ;
    END
  END di0[545]
  PIN di0[546]
    DIRECTION INPUT ;
    USE SIGNAL ;
    PORT
      LAYER M4 ;
        RECT  0 28.896 0.192 28.92 ;
    END
  END di0[546]
  PIN di0[547]
    DIRECTION INPUT ;
    USE SIGNAL ;
    PORT
      LAYER M4 ;
        RECT  0 28.944 0.192 28.968 ;
    END
  END di0[547]
  PIN di0[548]
    DIRECTION INPUT ;
    USE SIGNAL ;
    PORT
      LAYER M4 ;
        RECT  0 28.992 0.192 29.016 ;
    END
  END di0[548]
  PIN di0[549]
    DIRECTION INPUT ;
    USE SIGNAL ;
    PORT
      LAYER M4 ;
        RECT  0 29.04 0.192 29.064 ;
    END
  END di0[549]
  PIN di0[54]
    DIRECTION INPUT ;
    USE SIGNAL ;
    PORT
      LAYER M4 ;
        RECT  0 5.28 0.192 5.304 ;
    END
  END di0[54]
  PIN di0[550]
    DIRECTION INPUT ;
    USE SIGNAL ;
    PORT
      LAYER M4 ;
        RECT  0 29.088 0.192 29.112 ;
    END
  END di0[550]
  PIN di0[551]
    DIRECTION INPUT ;
    USE SIGNAL ;
    PORT
      LAYER M4 ;
        RECT  0 29.136 0.192 29.16 ;
    END
  END di0[551]
  PIN di0[552]
    DIRECTION INPUT ;
    USE SIGNAL ;
    PORT
      LAYER M4 ;
        RECT  0 29.184 0.192 29.208 ;
    END
  END di0[552]
  PIN di0[553]
    DIRECTION INPUT ;
    USE SIGNAL ;
    PORT
      LAYER M4 ;
        RECT  0 29.232 0.192 29.256 ;
    END
  END di0[553]
  PIN di0[554]
    DIRECTION INPUT ;
    USE SIGNAL ;
    PORT
      LAYER M4 ;
        RECT  0 29.28 0.192 29.304 ;
    END
  END di0[554]
  PIN di0[555]
    DIRECTION INPUT ;
    USE SIGNAL ;
    PORT
      LAYER M4 ;
        RECT  0 29.328 0.192 29.352 ;
    END
  END di0[555]
  PIN di0[556]
    DIRECTION INPUT ;
    USE SIGNAL ;
    PORT
      LAYER M4 ;
        RECT  0 29.376 0.192 29.4 ;
    END
  END di0[556]
  PIN di0[557]
    DIRECTION INPUT ;
    USE SIGNAL ;
    PORT
      LAYER M4 ;
        RECT  0 29.424 0.192 29.448 ;
    END
  END di0[557]
  PIN di0[558]
    DIRECTION INPUT ;
    USE SIGNAL ;
    PORT
      LAYER M4 ;
        RECT  0 29.472 0.192 29.496 ;
    END
  END di0[558]
  PIN di0[559]
    DIRECTION INPUT ;
    USE SIGNAL ;
    PORT
      LAYER M4 ;
        RECT  0 29.52 0.192 29.544 ;
    END
  END di0[559]
  PIN di0[55]
    DIRECTION INPUT ;
    USE SIGNAL ;
    PORT
      LAYER M4 ;
        RECT  0 5.328 0.192 5.352 ;
    END
  END di0[55]
  PIN di0[560]
    DIRECTION INPUT ;
    USE SIGNAL ;
    PORT
      LAYER M4 ;
        RECT  0 29.568 0.192 29.592 ;
    END
  END di0[560]
  PIN di0[561]
    DIRECTION INPUT ;
    USE SIGNAL ;
    PORT
      LAYER M4 ;
        RECT  0 29.616 0.192 29.64 ;
    END
  END di0[561]
  PIN di0[562]
    DIRECTION INPUT ;
    USE SIGNAL ;
    PORT
      LAYER M4 ;
        RECT  0 29.664 0.192 29.688 ;
    END
  END di0[562]
  PIN di0[563]
    DIRECTION INPUT ;
    USE SIGNAL ;
    PORT
      LAYER M4 ;
        RECT  0 29.712 0.192 29.736 ;
    END
  END di0[563]
  PIN di0[564]
    DIRECTION INPUT ;
    USE SIGNAL ;
    PORT
      LAYER M4 ;
        RECT  0 29.76 0.192 29.784 ;
    END
  END di0[564]
  PIN di0[565]
    DIRECTION INPUT ;
    USE SIGNAL ;
    PORT
      LAYER M4 ;
        RECT  0 29.808 0.192 29.832 ;
    END
  END di0[565]
  PIN di0[56]
    DIRECTION INPUT ;
    USE SIGNAL ;
    PORT
      LAYER M4 ;
        RECT  0 5.376 0.192 5.4 ;
    END
  END di0[56]
  PIN di0[57]
    DIRECTION INPUT ;
    USE SIGNAL ;
    PORT
      LAYER M4 ;
        RECT  0 5.424 0.192 5.448 ;
    END
  END di0[57]
  PIN di0[58]
    DIRECTION INPUT ;
    USE SIGNAL ;
    PORT
      LAYER M4 ;
        RECT  0 5.472 0.192 5.496 ;
    END
  END di0[58]
  PIN di0[59]
    DIRECTION INPUT ;
    USE SIGNAL ;
    PORT
      LAYER M4 ;
        RECT  0 5.52 0.192 5.544 ;
    END
  END di0[59]
  PIN di0[5]
    DIRECTION INPUT ;
    USE SIGNAL ;
    PORT
      LAYER M4 ;
        RECT  0 2.928 0.192 2.952 ;
    END
  END di0[5]
  PIN di0[60]
    DIRECTION INPUT ;
    USE SIGNAL ;
    PORT
      LAYER M4 ;
        RECT  0 5.568 0.192 5.592 ;
    END
  END di0[60]
  PIN di0[61]
    DIRECTION INPUT ;
    USE SIGNAL ;
    PORT
      LAYER M4 ;
        RECT  0 5.616 0.192 5.64 ;
    END
  END di0[61]
  PIN di0[62]
    DIRECTION INPUT ;
    USE SIGNAL ;
    PORT
      LAYER M4 ;
        RECT  0 5.664 0.192 5.688 ;
    END
  END di0[62]
  PIN di0[63]
    DIRECTION INPUT ;
    USE SIGNAL ;
    PORT
      LAYER M4 ;
        RECT  0 5.712 0.192 5.736 ;
    END
  END di0[63]
  PIN di0[64]
    DIRECTION INPUT ;
    USE SIGNAL ;
    PORT
      LAYER M4 ;
        RECT  0 5.76 0.192 5.784 ;
    END
  END di0[64]
  PIN di0[65]
    DIRECTION INPUT ;
    USE SIGNAL ;
    PORT
      LAYER M4 ;
        RECT  0 5.808 0.192 5.832 ;
    END
  END di0[65]
  PIN di0[66]
    DIRECTION INPUT ;
    USE SIGNAL ;
    PORT
      LAYER M4 ;
        RECT  0 5.856 0.192 5.88 ;
    END
  END di0[66]
  PIN di0[67]
    DIRECTION INPUT ;
    USE SIGNAL ;
    PORT
      LAYER M4 ;
        RECT  0 5.904 0.192 5.928 ;
    END
  END di0[67]
  PIN di0[68]
    DIRECTION INPUT ;
    USE SIGNAL ;
    PORT
      LAYER M4 ;
        RECT  0 5.952 0.192 5.976 ;
    END
  END di0[68]
  PIN di0[69]
    DIRECTION INPUT ;
    USE SIGNAL ;
    PORT
      LAYER M4 ;
        RECT  0 6 0.192 6.024 ;
    END
  END di0[69]
  PIN di0[6]
    DIRECTION INPUT ;
    USE SIGNAL ;
    PORT
      LAYER M4 ;
        RECT  0 2.976 0.192 3 ;
    END
  END di0[6]
  PIN di0[70]
    DIRECTION INPUT ;
    USE SIGNAL ;
    PORT
      LAYER M4 ;
        RECT  0 6.048 0.192 6.072 ;
    END
  END di0[70]
  PIN di0[71]
    DIRECTION INPUT ;
    USE SIGNAL ;
    PORT
      LAYER M4 ;
        RECT  0 6.096 0.192 6.12 ;
    END
  END di0[71]
  PIN di0[72]
    DIRECTION INPUT ;
    USE SIGNAL ;
    PORT
      LAYER M4 ;
        RECT  0 6.144 0.192 6.168 ;
    END
  END di0[72]
  PIN di0[73]
    DIRECTION INPUT ;
    USE SIGNAL ;
    PORT
      LAYER M4 ;
        RECT  0 6.192 0.192 6.216 ;
    END
  END di0[73]
  PIN di0[74]
    DIRECTION INPUT ;
    USE SIGNAL ;
    PORT
      LAYER M4 ;
        RECT  0 6.24 0.192 6.264 ;
    END
  END di0[74]
  PIN di0[75]
    DIRECTION INPUT ;
    USE SIGNAL ;
    PORT
      LAYER M4 ;
        RECT  0 6.288 0.192 6.312 ;
    END
  END di0[75]
  PIN di0[76]
    DIRECTION INPUT ;
    USE SIGNAL ;
    PORT
      LAYER M4 ;
        RECT  0 6.336 0.192 6.36 ;
    END
  END di0[76]
  PIN di0[77]
    DIRECTION INPUT ;
    USE SIGNAL ;
    PORT
      LAYER M4 ;
        RECT  0 6.384 0.192 6.408 ;
    END
  END di0[77]
  PIN di0[78]
    DIRECTION INPUT ;
    USE SIGNAL ;
    PORT
      LAYER M4 ;
        RECT  0 6.432 0.192 6.456 ;
    END
  END di0[78]
  PIN di0[79]
    DIRECTION INPUT ;
    USE SIGNAL ;
    PORT
      LAYER M4 ;
        RECT  0 6.48 0.192 6.504 ;
    END
  END di0[79]
  PIN di0[7]
    DIRECTION INPUT ;
    USE SIGNAL ;
    PORT
      LAYER M4 ;
        RECT  0 3.024 0.192 3.048 ;
    END
  END di0[7]
  PIN di0[80]
    DIRECTION INPUT ;
    USE SIGNAL ;
    PORT
      LAYER M4 ;
        RECT  0 6.528 0.192 6.552 ;
    END
  END di0[80]
  PIN di0[81]
    DIRECTION INPUT ;
    USE SIGNAL ;
    PORT
      LAYER M4 ;
        RECT  0 6.576 0.192 6.6 ;
    END
  END di0[81]
  PIN di0[82]
    DIRECTION INPUT ;
    USE SIGNAL ;
    PORT
      LAYER M4 ;
        RECT  0 6.624 0.192 6.648 ;
    END
  END di0[82]
  PIN di0[83]
    DIRECTION INPUT ;
    USE SIGNAL ;
    PORT
      LAYER M4 ;
        RECT  0 6.672 0.192 6.696 ;
    END
  END di0[83]
  PIN di0[84]
    DIRECTION INPUT ;
    USE SIGNAL ;
    PORT
      LAYER M4 ;
        RECT  0 6.72 0.192 6.744 ;
    END
  END di0[84]
  PIN di0[85]
    DIRECTION INPUT ;
    USE SIGNAL ;
    PORT
      LAYER M4 ;
        RECT  0 6.768 0.192 6.792 ;
    END
  END di0[85]
  PIN di0[86]
    DIRECTION INPUT ;
    USE SIGNAL ;
    PORT
      LAYER M4 ;
        RECT  0 6.816 0.192 6.84 ;
    END
  END di0[86]
  PIN di0[87]
    DIRECTION INPUT ;
    USE SIGNAL ;
    PORT
      LAYER M4 ;
        RECT  0 6.864 0.192 6.888 ;
    END
  END di0[87]
  PIN di0[88]
    DIRECTION INPUT ;
    USE SIGNAL ;
    PORT
      LAYER M4 ;
        RECT  0 6.912 0.192 6.936 ;
    END
  END di0[88]
  PIN di0[89]
    DIRECTION INPUT ;
    USE SIGNAL ;
    PORT
      LAYER M4 ;
        RECT  0 6.96 0.192 6.984 ;
    END
  END di0[89]
  PIN di0[8]
    DIRECTION INPUT ;
    USE SIGNAL ;
    PORT
      LAYER M4 ;
        RECT  0 3.072 0.192 3.096 ;
    END
  END di0[8]
  PIN di0[90]
    DIRECTION INPUT ;
    USE SIGNAL ;
    PORT
      LAYER M4 ;
        RECT  0 7.008 0.192 7.032 ;
    END
  END di0[90]
  PIN di0[91]
    DIRECTION INPUT ;
    USE SIGNAL ;
    PORT
      LAYER M4 ;
        RECT  0 7.056 0.192 7.08 ;
    END
  END di0[91]
  PIN di0[92]
    DIRECTION INPUT ;
    USE SIGNAL ;
    PORT
      LAYER M4 ;
        RECT  0 7.104 0.192 7.128 ;
    END
  END di0[92]
  PIN di0[93]
    DIRECTION INPUT ;
    USE SIGNAL ;
    PORT
      LAYER M4 ;
        RECT  0 7.152 0.192 7.176 ;
    END
  END di0[93]
  PIN di0[94]
    DIRECTION INPUT ;
    USE SIGNAL ;
    PORT
      LAYER M4 ;
        RECT  0 7.2 0.192 7.224 ;
    END
  END di0[94]
  PIN di0[95]
    DIRECTION INPUT ;
    USE SIGNAL ;
    PORT
      LAYER M4 ;
        RECT  0 7.248 0.192 7.272 ;
    END
  END di0[95]
  PIN di0[96]
    DIRECTION INPUT ;
    USE SIGNAL ;
    PORT
      LAYER M4 ;
        RECT  0 7.296 0.192 7.32 ;
    END
  END di0[96]
  PIN di0[97]
    DIRECTION INPUT ;
    USE SIGNAL ;
    PORT
      LAYER M4 ;
        RECT  0 7.344 0.192 7.368 ;
    END
  END di0[97]
  PIN di0[98]
    DIRECTION INPUT ;
    USE SIGNAL ;
    PORT
      LAYER M4 ;
        RECT  0 7.392 0.192 7.416 ;
    END
  END di0[98]
  PIN di0[99]
    DIRECTION INPUT ;
    USE SIGNAL ;
    PORT
      LAYER M4 ;
        RECT  0 7.44 0.192 7.464 ;
    END
  END di0[99]
  PIN di0[9]
    DIRECTION INPUT ;
    USE SIGNAL ;
    PORT
      LAYER M4 ;
        RECT  0 3.12 0.192 3.144 ;
    END
  END di0[9]
  PIN do0[0]
    DIRECTION OUTPUT ;
    USE SIGNAL ;
    PORT
      LAYER M4 ;
        RECT  17.064 2.688 17.256 2.712 ;
    END
  END do0[0]
  PIN do0[100]
    DIRECTION OUTPUT ;
    USE SIGNAL ;
    PORT
      LAYER M4 ;
        RECT  17.064 7.488 17.256 7.512 ;
    END
  END do0[100]
  PIN do0[101]
    DIRECTION OUTPUT ;
    USE SIGNAL ;
    PORT
      LAYER M4 ;
        RECT  17.064 7.536 17.256 7.56 ;
    END
  END do0[101]
  PIN do0[102]
    DIRECTION OUTPUT ;
    USE SIGNAL ;
    PORT
      LAYER M4 ;
        RECT  17.064 7.584 17.256 7.608 ;
    END
  END do0[102]
  PIN do0[103]
    DIRECTION OUTPUT ;
    USE SIGNAL ;
    PORT
      LAYER M4 ;
        RECT  17.064 7.632 17.256 7.656 ;
    END
  END do0[103]
  PIN do0[104]
    DIRECTION OUTPUT ;
    USE SIGNAL ;
    PORT
      LAYER M4 ;
        RECT  17.064 7.68 17.256 7.704 ;
    END
  END do0[104]
  PIN do0[105]
    DIRECTION OUTPUT ;
    USE SIGNAL ;
    PORT
      LAYER M4 ;
        RECT  17.064 7.728 17.256 7.752 ;
    END
  END do0[105]
  PIN do0[106]
    DIRECTION OUTPUT ;
    USE SIGNAL ;
    PORT
      LAYER M4 ;
        RECT  17.064 7.776 17.256 7.8 ;
    END
  END do0[106]
  PIN do0[107]
    DIRECTION OUTPUT ;
    USE SIGNAL ;
    PORT
      LAYER M4 ;
        RECT  17.064 7.824 17.256 7.848 ;
    END
  END do0[107]
  PIN do0[108]
    DIRECTION OUTPUT ;
    USE SIGNAL ;
    PORT
      LAYER M4 ;
        RECT  17.064 7.872 17.256 7.896 ;
    END
  END do0[108]
  PIN do0[109]
    DIRECTION OUTPUT ;
    USE SIGNAL ;
    PORT
      LAYER M4 ;
        RECT  17.064 7.92 17.256 7.944 ;
    END
  END do0[109]
  PIN do0[10]
    DIRECTION OUTPUT ;
    USE SIGNAL ;
    PORT
      LAYER M4 ;
        RECT  17.064 3.168 17.256 3.192 ;
    END
  END do0[10]
  PIN do0[110]
    DIRECTION OUTPUT ;
    USE SIGNAL ;
    PORT
      LAYER M4 ;
        RECT  17.064 7.968 17.256 7.992 ;
    END
  END do0[110]
  PIN do0[111]
    DIRECTION OUTPUT ;
    USE SIGNAL ;
    PORT
      LAYER M4 ;
        RECT  17.064 8.016 17.256 8.04 ;
    END
  END do0[111]
  PIN do0[112]
    DIRECTION OUTPUT ;
    USE SIGNAL ;
    PORT
      LAYER M4 ;
        RECT  17.064 8.064 17.256 8.088 ;
    END
  END do0[112]
  PIN do0[113]
    DIRECTION OUTPUT ;
    USE SIGNAL ;
    PORT
      LAYER M4 ;
        RECT  17.064 8.112 17.256 8.136 ;
    END
  END do0[113]
  PIN do0[114]
    DIRECTION OUTPUT ;
    USE SIGNAL ;
    PORT
      LAYER M4 ;
        RECT  17.064 8.16 17.256 8.184 ;
    END
  END do0[114]
  PIN do0[115]
    DIRECTION OUTPUT ;
    USE SIGNAL ;
    PORT
      LAYER M4 ;
        RECT  17.064 8.208 17.256 8.232 ;
    END
  END do0[115]
  PIN do0[116]
    DIRECTION OUTPUT ;
    USE SIGNAL ;
    PORT
      LAYER M4 ;
        RECT  17.064 8.256 17.256 8.28 ;
    END
  END do0[116]
  PIN do0[117]
    DIRECTION OUTPUT ;
    USE SIGNAL ;
    PORT
      LAYER M4 ;
        RECT  17.064 8.304 17.256 8.328 ;
    END
  END do0[117]
  PIN do0[118]
    DIRECTION OUTPUT ;
    USE SIGNAL ;
    PORT
      LAYER M4 ;
        RECT  17.064 8.352 17.256 8.376 ;
    END
  END do0[118]
  PIN do0[119]
    DIRECTION OUTPUT ;
    USE SIGNAL ;
    PORT
      LAYER M4 ;
        RECT  17.064 8.4 17.256 8.424 ;
    END
  END do0[119]
  PIN do0[11]
    DIRECTION OUTPUT ;
    USE SIGNAL ;
    PORT
      LAYER M4 ;
        RECT  17.064 3.216 17.256 3.24 ;
    END
  END do0[11]
  PIN do0[120]
    DIRECTION OUTPUT ;
    USE SIGNAL ;
    PORT
      LAYER M4 ;
        RECT  17.064 8.448 17.256 8.472 ;
    END
  END do0[120]
  PIN do0[121]
    DIRECTION OUTPUT ;
    USE SIGNAL ;
    PORT
      LAYER M4 ;
        RECT  17.064 8.496 17.256 8.52 ;
    END
  END do0[121]
  PIN do0[122]
    DIRECTION OUTPUT ;
    USE SIGNAL ;
    PORT
      LAYER M4 ;
        RECT  17.064 8.544 17.256 8.568 ;
    END
  END do0[122]
  PIN do0[123]
    DIRECTION OUTPUT ;
    USE SIGNAL ;
    PORT
      LAYER M4 ;
        RECT  17.064 8.592 17.256 8.616 ;
    END
  END do0[123]
  PIN do0[124]
    DIRECTION OUTPUT ;
    USE SIGNAL ;
    PORT
      LAYER M4 ;
        RECT  17.064 8.64 17.256 8.664 ;
    END
  END do0[124]
  PIN do0[125]
    DIRECTION OUTPUT ;
    USE SIGNAL ;
    PORT
      LAYER M4 ;
        RECT  17.064 8.688 17.256 8.712 ;
    END
  END do0[125]
  PIN do0[126]
    DIRECTION OUTPUT ;
    USE SIGNAL ;
    PORT
      LAYER M4 ;
        RECT  17.064 8.736 17.256 8.76 ;
    END
  END do0[126]
  PIN do0[127]
    DIRECTION OUTPUT ;
    USE SIGNAL ;
    PORT
      LAYER M4 ;
        RECT  17.064 8.784 17.256 8.808 ;
    END
  END do0[127]
  PIN do0[128]
    DIRECTION OUTPUT ;
    USE SIGNAL ;
    PORT
      LAYER M4 ;
        RECT  17.064 8.832 17.256 8.856 ;
    END
  END do0[128]
  PIN do0[129]
    DIRECTION OUTPUT ;
    USE SIGNAL ;
    PORT
      LAYER M4 ;
        RECT  17.064 8.88 17.256 8.904 ;
    END
  END do0[129]
  PIN do0[12]
    DIRECTION OUTPUT ;
    USE SIGNAL ;
    PORT
      LAYER M4 ;
        RECT  17.064 3.264 17.256 3.288 ;
    END
  END do0[12]
  PIN do0[130]
    DIRECTION OUTPUT ;
    USE SIGNAL ;
    PORT
      LAYER M4 ;
        RECT  17.064 8.928 17.256 8.952 ;
    END
  END do0[130]
  PIN do0[131]
    DIRECTION OUTPUT ;
    USE SIGNAL ;
    PORT
      LAYER M4 ;
        RECT  17.064 8.976 17.256 9 ;
    END
  END do0[131]
  PIN do0[132]
    DIRECTION OUTPUT ;
    USE SIGNAL ;
    PORT
      LAYER M4 ;
        RECT  17.064 9.024 17.256 9.048 ;
    END
  END do0[132]
  PIN do0[133]
    DIRECTION OUTPUT ;
    USE SIGNAL ;
    PORT
      LAYER M4 ;
        RECT  17.064 9.072 17.256 9.096 ;
    END
  END do0[133]
  PIN do0[134]
    DIRECTION OUTPUT ;
    USE SIGNAL ;
    PORT
      LAYER M4 ;
        RECT  17.064 9.12 17.256 9.144 ;
    END
  END do0[134]
  PIN do0[135]
    DIRECTION OUTPUT ;
    USE SIGNAL ;
    PORT
      LAYER M4 ;
        RECT  17.064 9.168 17.256 9.192 ;
    END
  END do0[135]
  PIN do0[136]
    DIRECTION OUTPUT ;
    USE SIGNAL ;
    PORT
      LAYER M4 ;
        RECT  17.064 9.216 17.256 9.24 ;
    END
  END do0[136]
  PIN do0[137]
    DIRECTION OUTPUT ;
    USE SIGNAL ;
    PORT
      LAYER M4 ;
        RECT  17.064 9.264 17.256 9.288 ;
    END
  END do0[137]
  PIN do0[138]
    DIRECTION OUTPUT ;
    USE SIGNAL ;
    PORT
      LAYER M4 ;
        RECT  17.064 9.312 17.256 9.336 ;
    END
  END do0[138]
  PIN do0[139]
    DIRECTION OUTPUT ;
    USE SIGNAL ;
    PORT
      LAYER M4 ;
        RECT  17.064 9.36 17.256 9.384 ;
    END
  END do0[139]
  PIN do0[13]
    DIRECTION OUTPUT ;
    USE SIGNAL ;
    PORT
      LAYER M4 ;
        RECT  17.064 3.312 17.256 3.336 ;
    END
  END do0[13]
  PIN do0[140]
    DIRECTION OUTPUT ;
    USE SIGNAL ;
    PORT
      LAYER M4 ;
        RECT  17.064 9.408 17.256 9.432 ;
    END
  END do0[140]
  PIN do0[141]
    DIRECTION OUTPUT ;
    USE SIGNAL ;
    PORT
      LAYER M4 ;
        RECT  17.064 9.456 17.256 9.48 ;
    END
  END do0[141]
  PIN do0[142]
    DIRECTION OUTPUT ;
    USE SIGNAL ;
    PORT
      LAYER M4 ;
        RECT  17.064 9.504 17.256 9.528 ;
    END
  END do0[142]
  PIN do0[143]
    DIRECTION OUTPUT ;
    USE SIGNAL ;
    PORT
      LAYER M4 ;
        RECT  17.064 9.552 17.256 9.576 ;
    END
  END do0[143]
  PIN do0[144]
    DIRECTION OUTPUT ;
    USE SIGNAL ;
    PORT
      LAYER M4 ;
        RECT  17.064 9.6 17.256 9.624 ;
    END
  END do0[144]
  PIN do0[145]
    DIRECTION OUTPUT ;
    USE SIGNAL ;
    PORT
      LAYER M4 ;
        RECT  17.064 9.648 17.256 9.672 ;
    END
  END do0[145]
  PIN do0[146]
    DIRECTION OUTPUT ;
    USE SIGNAL ;
    PORT
      LAYER M4 ;
        RECT  17.064 9.696 17.256 9.72 ;
    END
  END do0[146]
  PIN do0[147]
    DIRECTION OUTPUT ;
    USE SIGNAL ;
    PORT
      LAYER M4 ;
        RECT  17.064 9.744 17.256 9.768 ;
    END
  END do0[147]
  PIN do0[148]
    DIRECTION OUTPUT ;
    USE SIGNAL ;
    PORT
      LAYER M4 ;
        RECT  17.064 9.792 17.256 9.816 ;
    END
  END do0[148]
  PIN do0[149]
    DIRECTION OUTPUT ;
    USE SIGNAL ;
    PORT
      LAYER M4 ;
        RECT  17.064 9.84 17.256 9.864 ;
    END
  END do0[149]
  PIN do0[14]
    DIRECTION OUTPUT ;
    USE SIGNAL ;
    PORT
      LAYER M4 ;
        RECT  17.064 3.36 17.256 3.384 ;
    END
  END do0[14]
  PIN do0[150]
    DIRECTION OUTPUT ;
    USE SIGNAL ;
    PORT
      LAYER M4 ;
        RECT  17.064 9.888 17.256 9.912 ;
    END
  END do0[150]
  PIN do0[151]
    DIRECTION OUTPUT ;
    USE SIGNAL ;
    PORT
      LAYER M4 ;
        RECT  17.064 9.936 17.256 9.96 ;
    END
  END do0[151]
  PIN do0[152]
    DIRECTION OUTPUT ;
    USE SIGNAL ;
    PORT
      LAYER M4 ;
        RECT  17.064 9.984 17.256 10.008 ;
    END
  END do0[152]
  PIN do0[153]
    DIRECTION OUTPUT ;
    USE SIGNAL ;
    PORT
      LAYER M4 ;
        RECT  17.064 10.032 17.256 10.056 ;
    END
  END do0[153]
  PIN do0[154]
    DIRECTION OUTPUT ;
    USE SIGNAL ;
    PORT
      LAYER M4 ;
        RECT  17.064 10.08 17.256 10.104 ;
    END
  END do0[154]
  PIN do0[155]
    DIRECTION OUTPUT ;
    USE SIGNAL ;
    PORT
      LAYER M4 ;
        RECT  17.064 10.128 17.256 10.152 ;
    END
  END do0[155]
  PIN do0[156]
    DIRECTION OUTPUT ;
    USE SIGNAL ;
    PORT
      LAYER M4 ;
        RECT  17.064 10.176 17.256 10.2 ;
    END
  END do0[156]
  PIN do0[157]
    DIRECTION OUTPUT ;
    USE SIGNAL ;
    PORT
      LAYER M4 ;
        RECT  17.064 10.224 17.256 10.248 ;
    END
  END do0[157]
  PIN do0[158]
    DIRECTION OUTPUT ;
    USE SIGNAL ;
    PORT
      LAYER M4 ;
        RECT  17.064 10.272 17.256 10.296 ;
    END
  END do0[158]
  PIN do0[159]
    DIRECTION OUTPUT ;
    USE SIGNAL ;
    PORT
      LAYER M4 ;
        RECT  17.064 10.32 17.256 10.344 ;
    END
  END do0[159]
  PIN do0[15]
    DIRECTION OUTPUT ;
    USE SIGNAL ;
    PORT
      LAYER M4 ;
        RECT  17.064 3.408 17.256 3.432 ;
    END
  END do0[15]
  PIN do0[160]
    DIRECTION OUTPUT ;
    USE SIGNAL ;
    PORT
      LAYER M4 ;
        RECT  17.064 10.368 17.256 10.392 ;
    END
  END do0[160]
  PIN do0[161]
    DIRECTION OUTPUT ;
    USE SIGNAL ;
    PORT
      LAYER M4 ;
        RECT  17.064 10.416 17.256 10.44 ;
    END
  END do0[161]
  PIN do0[162]
    DIRECTION OUTPUT ;
    USE SIGNAL ;
    PORT
      LAYER M4 ;
        RECT  17.064 10.464 17.256 10.488 ;
    END
  END do0[162]
  PIN do0[163]
    DIRECTION OUTPUT ;
    USE SIGNAL ;
    PORT
      LAYER M4 ;
        RECT  17.064 10.512 17.256 10.536 ;
    END
  END do0[163]
  PIN do0[164]
    DIRECTION OUTPUT ;
    USE SIGNAL ;
    PORT
      LAYER M4 ;
        RECT  17.064 10.56 17.256 10.584 ;
    END
  END do0[164]
  PIN do0[165]
    DIRECTION OUTPUT ;
    USE SIGNAL ;
    PORT
      LAYER M4 ;
        RECT  17.064 10.608 17.256 10.632 ;
    END
  END do0[165]
  PIN do0[166]
    DIRECTION OUTPUT ;
    USE SIGNAL ;
    PORT
      LAYER M4 ;
        RECT  17.064 10.656 17.256 10.68 ;
    END
  END do0[166]
  PIN do0[167]
    DIRECTION OUTPUT ;
    USE SIGNAL ;
    PORT
      LAYER M4 ;
        RECT  17.064 10.704 17.256 10.728 ;
    END
  END do0[167]
  PIN do0[168]
    DIRECTION OUTPUT ;
    USE SIGNAL ;
    PORT
      LAYER M4 ;
        RECT  17.064 10.752 17.256 10.776 ;
    END
  END do0[168]
  PIN do0[169]
    DIRECTION OUTPUT ;
    USE SIGNAL ;
    PORT
      LAYER M4 ;
        RECT  17.064 10.8 17.256 10.824 ;
    END
  END do0[169]
  PIN do0[16]
    DIRECTION OUTPUT ;
    USE SIGNAL ;
    PORT
      LAYER M4 ;
        RECT  17.064 3.456 17.256 3.48 ;
    END
  END do0[16]
  PIN do0[170]
    DIRECTION OUTPUT ;
    USE SIGNAL ;
    PORT
      LAYER M4 ;
        RECT  17.064 10.848 17.256 10.872 ;
    END
  END do0[170]
  PIN do0[171]
    DIRECTION OUTPUT ;
    USE SIGNAL ;
    PORT
      LAYER M4 ;
        RECT  17.064 10.896 17.256 10.92 ;
    END
  END do0[171]
  PIN do0[172]
    DIRECTION OUTPUT ;
    USE SIGNAL ;
    PORT
      LAYER M4 ;
        RECT  17.064 10.944 17.256 10.968 ;
    END
  END do0[172]
  PIN do0[173]
    DIRECTION OUTPUT ;
    USE SIGNAL ;
    PORT
      LAYER M4 ;
        RECT  17.064 10.992 17.256 11.016 ;
    END
  END do0[173]
  PIN do0[174]
    DIRECTION OUTPUT ;
    USE SIGNAL ;
    PORT
      LAYER M4 ;
        RECT  17.064 11.04 17.256 11.064 ;
    END
  END do0[174]
  PIN do0[175]
    DIRECTION OUTPUT ;
    USE SIGNAL ;
    PORT
      LAYER M4 ;
        RECT  17.064 11.088 17.256 11.112 ;
    END
  END do0[175]
  PIN do0[176]
    DIRECTION OUTPUT ;
    USE SIGNAL ;
    PORT
      LAYER M4 ;
        RECT  17.064 11.136 17.256 11.16 ;
    END
  END do0[176]
  PIN do0[177]
    DIRECTION OUTPUT ;
    USE SIGNAL ;
    PORT
      LAYER M4 ;
        RECT  17.064 11.184 17.256 11.208 ;
    END
  END do0[177]
  PIN do0[178]
    DIRECTION OUTPUT ;
    USE SIGNAL ;
    PORT
      LAYER M4 ;
        RECT  17.064 11.232 17.256 11.256 ;
    END
  END do0[178]
  PIN do0[179]
    DIRECTION OUTPUT ;
    USE SIGNAL ;
    PORT
      LAYER M4 ;
        RECT  17.064 11.28 17.256 11.304 ;
    END
  END do0[179]
  PIN do0[17]
    DIRECTION OUTPUT ;
    USE SIGNAL ;
    PORT
      LAYER M4 ;
        RECT  17.064 3.504 17.256 3.528 ;
    END
  END do0[17]
  PIN do0[180]
    DIRECTION OUTPUT ;
    USE SIGNAL ;
    PORT
      LAYER M4 ;
        RECT  17.064 11.328 17.256 11.352 ;
    END
  END do0[180]
  PIN do0[181]
    DIRECTION OUTPUT ;
    USE SIGNAL ;
    PORT
      LAYER M4 ;
        RECT  17.064 11.376 17.256 11.4 ;
    END
  END do0[181]
  PIN do0[182]
    DIRECTION OUTPUT ;
    USE SIGNAL ;
    PORT
      LAYER M4 ;
        RECT  17.064 11.424 17.256 11.448 ;
    END
  END do0[182]
  PIN do0[183]
    DIRECTION OUTPUT ;
    USE SIGNAL ;
    PORT
      LAYER M4 ;
        RECT  17.064 11.472 17.256 11.496 ;
    END
  END do0[183]
  PIN do0[184]
    DIRECTION OUTPUT ;
    USE SIGNAL ;
    PORT
      LAYER M4 ;
        RECT  17.064 11.52 17.256 11.544 ;
    END
  END do0[184]
  PIN do0[185]
    DIRECTION OUTPUT ;
    USE SIGNAL ;
    PORT
      LAYER M4 ;
        RECT  17.064 11.568 17.256 11.592 ;
    END
  END do0[185]
  PIN do0[186]
    DIRECTION OUTPUT ;
    USE SIGNAL ;
    PORT
      LAYER M4 ;
        RECT  17.064 11.616 17.256 11.64 ;
    END
  END do0[186]
  PIN do0[187]
    DIRECTION OUTPUT ;
    USE SIGNAL ;
    PORT
      LAYER M4 ;
        RECT  17.064 11.664 17.256 11.688 ;
    END
  END do0[187]
  PIN do0[188]
    DIRECTION OUTPUT ;
    USE SIGNAL ;
    PORT
      LAYER M4 ;
        RECT  17.064 11.712 17.256 11.736 ;
    END
  END do0[188]
  PIN do0[189]
    DIRECTION OUTPUT ;
    USE SIGNAL ;
    PORT
      LAYER M4 ;
        RECT  17.064 11.76 17.256 11.784 ;
    END
  END do0[189]
  PIN do0[18]
    DIRECTION OUTPUT ;
    USE SIGNAL ;
    PORT
      LAYER M4 ;
        RECT  17.064 3.552 17.256 3.576 ;
    END
  END do0[18]
  PIN do0[190]
    DIRECTION OUTPUT ;
    USE SIGNAL ;
    PORT
      LAYER M4 ;
        RECT  17.064 11.808 17.256 11.832 ;
    END
  END do0[190]
  PIN do0[191]
    DIRECTION OUTPUT ;
    USE SIGNAL ;
    PORT
      LAYER M4 ;
        RECT  17.064 11.856 17.256 11.88 ;
    END
  END do0[191]
  PIN do0[192]
    DIRECTION OUTPUT ;
    USE SIGNAL ;
    PORT
      LAYER M4 ;
        RECT  17.064 11.904 17.256 11.928 ;
    END
  END do0[192]
  PIN do0[193]
    DIRECTION OUTPUT ;
    USE SIGNAL ;
    PORT
      LAYER M4 ;
        RECT  17.064 11.952 17.256 11.976 ;
    END
  END do0[193]
  PIN do0[194]
    DIRECTION OUTPUT ;
    USE SIGNAL ;
    PORT
      LAYER M4 ;
        RECT  17.064 12 17.256 12.024 ;
    END
  END do0[194]
  PIN do0[195]
    DIRECTION OUTPUT ;
    USE SIGNAL ;
    PORT
      LAYER M4 ;
        RECT  17.064 12.048 17.256 12.072 ;
    END
  END do0[195]
  PIN do0[196]
    DIRECTION OUTPUT ;
    USE SIGNAL ;
    PORT
      LAYER M4 ;
        RECT  17.064 12.096 17.256 12.12 ;
    END
  END do0[196]
  PIN do0[197]
    DIRECTION OUTPUT ;
    USE SIGNAL ;
    PORT
      LAYER M4 ;
        RECT  17.064 12.144 17.256 12.168 ;
    END
  END do0[197]
  PIN do0[198]
    DIRECTION OUTPUT ;
    USE SIGNAL ;
    PORT
      LAYER M4 ;
        RECT  17.064 12.192 17.256 12.216 ;
    END
  END do0[198]
  PIN do0[199]
    DIRECTION OUTPUT ;
    USE SIGNAL ;
    PORT
      LAYER M4 ;
        RECT  17.064 12.24 17.256 12.264 ;
    END
  END do0[199]
  PIN do0[19]
    DIRECTION OUTPUT ;
    USE SIGNAL ;
    PORT
      LAYER M4 ;
        RECT  17.064 3.6 17.256 3.624 ;
    END
  END do0[19]
  PIN do0[1]
    DIRECTION OUTPUT ;
    USE SIGNAL ;
    PORT
      LAYER M4 ;
        RECT  17.064 2.736 17.256 2.76 ;
    END
  END do0[1]
  PIN do0[200]
    DIRECTION OUTPUT ;
    USE SIGNAL ;
    PORT
      LAYER M4 ;
        RECT  17.064 12.288 17.256 12.312 ;
    END
  END do0[200]
  PIN do0[201]
    DIRECTION OUTPUT ;
    USE SIGNAL ;
    PORT
      LAYER M4 ;
        RECT  17.064 12.336 17.256 12.36 ;
    END
  END do0[201]
  PIN do0[202]
    DIRECTION OUTPUT ;
    USE SIGNAL ;
    PORT
      LAYER M4 ;
        RECT  17.064 12.384 17.256 12.408 ;
    END
  END do0[202]
  PIN do0[203]
    DIRECTION OUTPUT ;
    USE SIGNAL ;
    PORT
      LAYER M4 ;
        RECT  17.064 12.432 17.256 12.456 ;
    END
  END do0[203]
  PIN do0[204]
    DIRECTION OUTPUT ;
    USE SIGNAL ;
    PORT
      LAYER M4 ;
        RECT  17.064 12.48 17.256 12.504 ;
    END
  END do0[204]
  PIN do0[205]
    DIRECTION OUTPUT ;
    USE SIGNAL ;
    PORT
      LAYER M4 ;
        RECT  17.064 12.528 17.256 12.552 ;
    END
  END do0[205]
  PIN do0[206]
    DIRECTION OUTPUT ;
    USE SIGNAL ;
    PORT
      LAYER M4 ;
        RECT  17.064 12.576 17.256 12.6 ;
    END
  END do0[206]
  PIN do0[207]
    DIRECTION OUTPUT ;
    USE SIGNAL ;
    PORT
      LAYER M4 ;
        RECT  17.064 12.624 17.256 12.648 ;
    END
  END do0[207]
  PIN do0[208]
    DIRECTION OUTPUT ;
    USE SIGNAL ;
    PORT
      LAYER M4 ;
        RECT  17.064 12.672 17.256 12.696 ;
    END
  END do0[208]
  PIN do0[209]
    DIRECTION OUTPUT ;
    USE SIGNAL ;
    PORT
      LAYER M4 ;
        RECT  17.064 12.72 17.256 12.744 ;
    END
  END do0[209]
  PIN do0[20]
    DIRECTION OUTPUT ;
    USE SIGNAL ;
    PORT
      LAYER M4 ;
        RECT  17.064 3.648 17.256 3.672 ;
    END
  END do0[20]
  PIN do0[210]
    DIRECTION OUTPUT ;
    USE SIGNAL ;
    PORT
      LAYER M4 ;
        RECT  17.064 12.768 17.256 12.792 ;
    END
  END do0[210]
  PIN do0[211]
    DIRECTION OUTPUT ;
    USE SIGNAL ;
    PORT
      LAYER M4 ;
        RECT  17.064 12.816 17.256 12.84 ;
    END
  END do0[211]
  PIN do0[212]
    DIRECTION OUTPUT ;
    USE SIGNAL ;
    PORT
      LAYER M4 ;
        RECT  17.064 12.864 17.256 12.888 ;
    END
  END do0[212]
  PIN do0[213]
    DIRECTION OUTPUT ;
    USE SIGNAL ;
    PORT
      LAYER M4 ;
        RECT  17.064 12.912 17.256 12.936 ;
    END
  END do0[213]
  PIN do0[214]
    DIRECTION OUTPUT ;
    USE SIGNAL ;
    PORT
      LAYER M4 ;
        RECT  17.064 12.96 17.256 12.984 ;
    END
  END do0[214]
  PIN do0[215]
    DIRECTION OUTPUT ;
    USE SIGNAL ;
    PORT
      LAYER M4 ;
        RECT  17.064 13.008 17.256 13.032 ;
    END
  END do0[215]
  PIN do0[216]
    DIRECTION OUTPUT ;
    USE SIGNAL ;
    PORT
      LAYER M4 ;
        RECT  17.064 13.056 17.256 13.08 ;
    END
  END do0[216]
  PIN do0[217]
    DIRECTION OUTPUT ;
    USE SIGNAL ;
    PORT
      LAYER M4 ;
        RECT  17.064 13.104 17.256 13.128 ;
    END
  END do0[217]
  PIN do0[218]
    DIRECTION OUTPUT ;
    USE SIGNAL ;
    PORT
      LAYER M4 ;
        RECT  17.064 13.152 17.256 13.176 ;
    END
  END do0[218]
  PIN do0[219]
    DIRECTION OUTPUT ;
    USE SIGNAL ;
    PORT
      LAYER M4 ;
        RECT  17.064 13.2 17.256 13.224 ;
    END
  END do0[219]
  PIN do0[21]
    DIRECTION OUTPUT ;
    USE SIGNAL ;
    PORT
      LAYER M4 ;
        RECT  17.064 3.696 17.256 3.72 ;
    END
  END do0[21]
  PIN do0[220]
    DIRECTION OUTPUT ;
    USE SIGNAL ;
    PORT
      LAYER M4 ;
        RECT  17.064 13.248 17.256 13.272 ;
    END
  END do0[220]
  PIN do0[221]
    DIRECTION OUTPUT ;
    USE SIGNAL ;
    PORT
      LAYER M4 ;
        RECT  17.064 13.296 17.256 13.32 ;
    END
  END do0[221]
  PIN do0[222]
    DIRECTION OUTPUT ;
    USE SIGNAL ;
    PORT
      LAYER M4 ;
        RECT  17.064 13.344 17.256 13.368 ;
    END
  END do0[222]
  PIN do0[223]
    DIRECTION OUTPUT ;
    USE SIGNAL ;
    PORT
      LAYER M4 ;
        RECT  17.064 13.392 17.256 13.416 ;
    END
  END do0[223]
  PIN do0[224]
    DIRECTION OUTPUT ;
    USE SIGNAL ;
    PORT
      LAYER M4 ;
        RECT  17.064 13.44 17.256 13.464 ;
    END
  END do0[224]
  PIN do0[225]
    DIRECTION OUTPUT ;
    USE SIGNAL ;
    PORT
      LAYER M4 ;
        RECT  17.064 13.488 17.256 13.512 ;
    END
  END do0[225]
  PIN do0[226]
    DIRECTION OUTPUT ;
    USE SIGNAL ;
    PORT
      LAYER M4 ;
        RECT  17.064 13.536 17.256 13.56 ;
    END
  END do0[226]
  PIN do0[227]
    DIRECTION OUTPUT ;
    USE SIGNAL ;
    PORT
      LAYER M4 ;
        RECT  17.064 13.584 17.256 13.608 ;
    END
  END do0[227]
  PIN do0[228]
    DIRECTION OUTPUT ;
    USE SIGNAL ;
    PORT
      LAYER M4 ;
        RECT  17.064 13.632 17.256 13.656 ;
    END
  END do0[228]
  PIN do0[229]
    DIRECTION OUTPUT ;
    USE SIGNAL ;
    PORT
      LAYER M4 ;
        RECT  17.064 13.68 17.256 13.704 ;
    END
  END do0[229]
  PIN do0[22]
    DIRECTION OUTPUT ;
    USE SIGNAL ;
    PORT
      LAYER M4 ;
        RECT  17.064 3.744 17.256 3.768 ;
    END
  END do0[22]
  PIN do0[230]
    DIRECTION OUTPUT ;
    USE SIGNAL ;
    PORT
      LAYER M4 ;
        RECT  17.064 13.728 17.256 13.752 ;
    END
  END do0[230]
  PIN do0[231]
    DIRECTION OUTPUT ;
    USE SIGNAL ;
    PORT
      LAYER M4 ;
        RECT  17.064 13.776 17.256 13.8 ;
    END
  END do0[231]
  PIN do0[232]
    DIRECTION OUTPUT ;
    USE SIGNAL ;
    PORT
      LAYER M4 ;
        RECT  17.064 13.824 17.256 13.848 ;
    END
  END do0[232]
  PIN do0[233]
    DIRECTION OUTPUT ;
    USE SIGNAL ;
    PORT
      LAYER M4 ;
        RECT  17.064 13.872 17.256 13.896 ;
    END
  END do0[233]
  PIN do0[234]
    DIRECTION OUTPUT ;
    USE SIGNAL ;
    PORT
      LAYER M4 ;
        RECT  17.064 13.92 17.256 13.944 ;
    END
  END do0[234]
  PIN do0[235]
    DIRECTION OUTPUT ;
    USE SIGNAL ;
    PORT
      LAYER M4 ;
        RECT  17.064 13.968 17.256 13.992 ;
    END
  END do0[235]
  PIN do0[236]
    DIRECTION OUTPUT ;
    USE SIGNAL ;
    PORT
      LAYER M4 ;
        RECT  17.064 14.016 17.256 14.04 ;
    END
  END do0[236]
  PIN do0[237]
    DIRECTION OUTPUT ;
    USE SIGNAL ;
    PORT
      LAYER M4 ;
        RECT  17.064 14.064 17.256 14.088 ;
    END
  END do0[237]
  PIN do0[238]
    DIRECTION OUTPUT ;
    USE SIGNAL ;
    PORT
      LAYER M4 ;
        RECT  17.064 14.112 17.256 14.136 ;
    END
  END do0[238]
  PIN do0[239]
    DIRECTION OUTPUT ;
    USE SIGNAL ;
    PORT
      LAYER M4 ;
        RECT  17.064 14.16 17.256 14.184 ;
    END
  END do0[239]
  PIN do0[23]
    DIRECTION OUTPUT ;
    USE SIGNAL ;
    PORT
      LAYER M4 ;
        RECT  17.064 3.792 17.256 3.816 ;
    END
  END do0[23]
  PIN do0[240]
    DIRECTION OUTPUT ;
    USE SIGNAL ;
    PORT
      LAYER M4 ;
        RECT  17.064 14.208 17.256 14.232 ;
    END
  END do0[240]
  PIN do0[241]
    DIRECTION OUTPUT ;
    USE SIGNAL ;
    PORT
      LAYER M4 ;
        RECT  17.064 14.256 17.256 14.28 ;
    END
  END do0[241]
  PIN do0[242]
    DIRECTION OUTPUT ;
    USE SIGNAL ;
    PORT
      LAYER M4 ;
        RECT  17.064 14.304 17.256 14.328 ;
    END
  END do0[242]
  PIN do0[243]
    DIRECTION OUTPUT ;
    USE SIGNAL ;
    PORT
      LAYER M4 ;
        RECT  17.064 14.352 17.256 14.376 ;
    END
  END do0[243]
  PIN do0[244]
    DIRECTION OUTPUT ;
    USE SIGNAL ;
    PORT
      LAYER M4 ;
        RECT  17.064 14.4 17.256 14.424 ;
    END
  END do0[244]
  PIN do0[245]
    DIRECTION OUTPUT ;
    USE SIGNAL ;
    PORT
      LAYER M4 ;
        RECT  17.064 14.448 17.256 14.472 ;
    END
  END do0[245]
  PIN do0[246]
    DIRECTION OUTPUT ;
    USE SIGNAL ;
    PORT
      LAYER M4 ;
        RECT  17.064 14.496 17.256 14.52 ;
    END
  END do0[246]
  PIN do0[247]
    DIRECTION OUTPUT ;
    USE SIGNAL ;
    PORT
      LAYER M4 ;
        RECT  17.064 14.544 17.256 14.568 ;
    END
  END do0[247]
  PIN do0[248]
    DIRECTION OUTPUT ;
    USE SIGNAL ;
    PORT
      LAYER M4 ;
        RECT  17.064 14.592 17.256 14.616 ;
    END
  END do0[248]
  PIN do0[249]
    DIRECTION OUTPUT ;
    USE SIGNAL ;
    PORT
      LAYER M4 ;
        RECT  17.064 14.64 17.256 14.664 ;
    END
  END do0[249]
  PIN do0[24]
    DIRECTION OUTPUT ;
    USE SIGNAL ;
    PORT
      LAYER M4 ;
        RECT  17.064 3.84 17.256 3.864 ;
    END
  END do0[24]
  PIN do0[250]
    DIRECTION OUTPUT ;
    USE SIGNAL ;
    PORT
      LAYER M4 ;
        RECT  17.064 14.688 17.256 14.712 ;
    END
  END do0[250]
  PIN do0[251]
    DIRECTION OUTPUT ;
    USE SIGNAL ;
    PORT
      LAYER M4 ;
        RECT  17.064 14.736 17.256 14.76 ;
    END
  END do0[251]
  PIN do0[252]
    DIRECTION OUTPUT ;
    USE SIGNAL ;
    PORT
      LAYER M4 ;
        RECT  17.064 14.784 17.256 14.808 ;
    END
  END do0[252]
  PIN do0[253]
    DIRECTION OUTPUT ;
    USE SIGNAL ;
    PORT
      LAYER M4 ;
        RECT  17.064 14.832 17.256 14.856 ;
    END
  END do0[253]
  PIN do0[254]
    DIRECTION OUTPUT ;
    USE SIGNAL ;
    PORT
      LAYER M4 ;
        RECT  17.064 14.88 17.256 14.904 ;
    END
  END do0[254]
  PIN do0[255]
    DIRECTION OUTPUT ;
    USE SIGNAL ;
    PORT
      LAYER M4 ;
        RECT  17.064 14.928 17.256 14.952 ;
    END
  END do0[255]
  PIN do0[256]
    DIRECTION OUTPUT ;
    USE SIGNAL ;
    PORT
      LAYER M4 ;
        RECT  17.064 14.976 17.256 15 ;
    END
  END do0[256]
  PIN do0[257]
    DIRECTION OUTPUT ;
    USE SIGNAL ;
    PORT
      LAYER M4 ;
        RECT  17.064 15.024 17.256 15.048 ;
    END
  END do0[257]
  PIN do0[258]
    DIRECTION OUTPUT ;
    USE SIGNAL ;
    PORT
      LAYER M4 ;
        RECT  17.064 15.072 17.256 15.096 ;
    END
  END do0[258]
  PIN do0[259]
    DIRECTION OUTPUT ;
    USE SIGNAL ;
    PORT
      LAYER M4 ;
        RECT  17.064 15.12 17.256 15.144 ;
    END
  END do0[259]
  PIN do0[25]
    DIRECTION OUTPUT ;
    USE SIGNAL ;
    PORT
      LAYER M4 ;
        RECT  17.064 3.888 17.256 3.912 ;
    END
  END do0[25]
  PIN do0[260]
    DIRECTION OUTPUT ;
    USE SIGNAL ;
    PORT
      LAYER M4 ;
        RECT  17.064 15.168 17.256 15.192 ;
    END
  END do0[260]
  PIN do0[261]
    DIRECTION OUTPUT ;
    USE SIGNAL ;
    PORT
      LAYER M4 ;
        RECT  17.064 15.216 17.256 15.24 ;
    END
  END do0[261]
  PIN do0[262]
    DIRECTION OUTPUT ;
    USE SIGNAL ;
    PORT
      LAYER M4 ;
        RECT  17.064 15.264 17.256 15.288 ;
    END
  END do0[262]
  PIN do0[263]
    DIRECTION OUTPUT ;
    USE SIGNAL ;
    PORT
      LAYER M4 ;
        RECT  17.064 15.312 17.256 15.336 ;
    END
  END do0[263]
  PIN do0[264]
    DIRECTION OUTPUT ;
    USE SIGNAL ;
    PORT
      LAYER M4 ;
        RECT  17.064 15.36 17.256 15.384 ;
    END
  END do0[264]
  PIN do0[265]
    DIRECTION OUTPUT ;
    USE SIGNAL ;
    PORT
      LAYER M4 ;
        RECT  17.064 15.408 17.256 15.432 ;
    END
  END do0[265]
  PIN do0[266]
    DIRECTION OUTPUT ;
    USE SIGNAL ;
    PORT
      LAYER M4 ;
        RECT  17.064 15.456 17.256 15.48 ;
    END
  END do0[266]
  PIN do0[267]
    DIRECTION OUTPUT ;
    USE SIGNAL ;
    PORT
      LAYER M4 ;
        RECT  17.064 15.504 17.256 15.528 ;
    END
  END do0[267]
  PIN do0[268]
    DIRECTION OUTPUT ;
    USE SIGNAL ;
    PORT
      LAYER M4 ;
        RECT  17.064 15.552 17.256 15.576 ;
    END
  END do0[268]
  PIN do0[269]
    DIRECTION OUTPUT ;
    USE SIGNAL ;
    PORT
      LAYER M4 ;
        RECT  17.064 15.6 17.256 15.624 ;
    END
  END do0[269]
  PIN do0[26]
    DIRECTION OUTPUT ;
    USE SIGNAL ;
    PORT
      LAYER M4 ;
        RECT  17.064 3.936 17.256 3.96 ;
    END
  END do0[26]
  PIN do0[270]
    DIRECTION OUTPUT ;
    USE SIGNAL ;
    PORT
      LAYER M4 ;
        RECT  17.064 15.648 17.256 15.672 ;
    END
  END do0[270]
  PIN do0[271]
    DIRECTION OUTPUT ;
    USE SIGNAL ;
    PORT
      LAYER M4 ;
        RECT  17.064 15.696 17.256 15.72 ;
    END
  END do0[271]
  PIN do0[272]
    DIRECTION OUTPUT ;
    USE SIGNAL ;
    PORT
      LAYER M4 ;
        RECT  17.064 15.744 17.256 15.768 ;
    END
  END do0[272]
  PIN do0[273]
    DIRECTION OUTPUT ;
    USE SIGNAL ;
    PORT
      LAYER M4 ;
        RECT  17.064 15.792 17.256 15.816 ;
    END
  END do0[273]
  PIN do0[274]
    DIRECTION OUTPUT ;
    USE SIGNAL ;
    PORT
      LAYER M4 ;
        RECT  17.064 15.84 17.256 15.864 ;
    END
  END do0[274]
  PIN do0[275]
    DIRECTION OUTPUT ;
    USE SIGNAL ;
    PORT
      LAYER M4 ;
        RECT  17.064 15.888 17.256 15.912 ;
    END
  END do0[275]
  PIN do0[276]
    DIRECTION OUTPUT ;
    USE SIGNAL ;
    PORT
      LAYER M4 ;
        RECT  17.064 15.936 17.256 15.96 ;
    END
  END do0[276]
  PIN do0[277]
    DIRECTION OUTPUT ;
    USE SIGNAL ;
    PORT
      LAYER M4 ;
        RECT  17.064 15.984 17.256 16.008 ;
    END
  END do0[277]
  PIN do0[278]
    DIRECTION OUTPUT ;
    USE SIGNAL ;
    PORT
      LAYER M4 ;
        RECT  17.064 16.032 17.256 16.056 ;
    END
  END do0[278]
  PIN do0[279]
    DIRECTION OUTPUT ;
    USE SIGNAL ;
    PORT
      LAYER M4 ;
        RECT  17.064 16.08 17.256 16.104 ;
    END
  END do0[279]
  PIN do0[27]
    DIRECTION OUTPUT ;
    USE SIGNAL ;
    PORT
      LAYER M4 ;
        RECT  17.064 3.984 17.256 4.008 ;
    END
  END do0[27]
  PIN do0[280]
    DIRECTION OUTPUT ;
    USE SIGNAL ;
    PORT
      LAYER M4 ;
        RECT  17.064 16.128 17.256 16.152 ;
    END
  END do0[280]
  PIN do0[281]
    DIRECTION OUTPUT ;
    USE SIGNAL ;
    PORT
      LAYER M4 ;
        RECT  17.064 16.176 17.256 16.2 ;
    END
  END do0[281]
  PIN do0[282]
    DIRECTION OUTPUT ;
    USE SIGNAL ;
    PORT
      LAYER M4 ;
        RECT  17.064 16.224 17.256 16.248 ;
    END
  END do0[282]
  PIN do0[283]
    DIRECTION OUTPUT ;
    USE SIGNAL ;
    PORT
      LAYER M4 ;
        RECT  17.064 16.272 17.256 16.296 ;
    END
  END do0[283]
  PIN do0[284]
    DIRECTION OUTPUT ;
    USE SIGNAL ;
    PORT
      LAYER M4 ;
        RECT  17.064 16.32 17.256 16.344 ;
    END
  END do0[284]
  PIN do0[285]
    DIRECTION OUTPUT ;
    USE SIGNAL ;
    PORT
      LAYER M4 ;
        RECT  17.064 16.368 17.256 16.392 ;
    END
  END do0[285]
  PIN do0[286]
    DIRECTION OUTPUT ;
    USE SIGNAL ;
    PORT
      LAYER M4 ;
        RECT  17.064 16.416 17.256 16.44 ;
    END
  END do0[286]
  PIN do0[287]
    DIRECTION OUTPUT ;
    USE SIGNAL ;
    PORT
      LAYER M4 ;
        RECT  17.064 16.464 17.256 16.488 ;
    END
  END do0[287]
  PIN do0[288]
    DIRECTION OUTPUT ;
    USE SIGNAL ;
    PORT
      LAYER M4 ;
        RECT  17.064 16.512 17.256 16.536 ;
    END
  END do0[288]
  PIN do0[289]
    DIRECTION OUTPUT ;
    USE SIGNAL ;
    PORT
      LAYER M4 ;
        RECT  17.064 16.56 17.256 16.584 ;
    END
  END do0[289]
  PIN do0[28]
    DIRECTION OUTPUT ;
    USE SIGNAL ;
    PORT
      LAYER M4 ;
        RECT  17.064 4.032 17.256 4.056 ;
    END
  END do0[28]
  PIN do0[290]
    DIRECTION OUTPUT ;
    USE SIGNAL ;
    PORT
      LAYER M4 ;
        RECT  17.064 16.608 17.256 16.632 ;
    END
  END do0[290]
  PIN do0[291]
    DIRECTION OUTPUT ;
    USE SIGNAL ;
    PORT
      LAYER M4 ;
        RECT  17.064 16.656 17.256 16.68 ;
    END
  END do0[291]
  PIN do0[292]
    DIRECTION OUTPUT ;
    USE SIGNAL ;
    PORT
      LAYER M4 ;
        RECT  17.064 16.704 17.256 16.728 ;
    END
  END do0[292]
  PIN do0[293]
    DIRECTION OUTPUT ;
    USE SIGNAL ;
    PORT
      LAYER M4 ;
        RECT  17.064 16.752 17.256 16.776 ;
    END
  END do0[293]
  PIN do0[294]
    DIRECTION OUTPUT ;
    USE SIGNAL ;
    PORT
      LAYER M4 ;
        RECT  17.064 16.8 17.256 16.824 ;
    END
  END do0[294]
  PIN do0[295]
    DIRECTION OUTPUT ;
    USE SIGNAL ;
    PORT
      LAYER M4 ;
        RECT  17.064 16.848 17.256 16.872 ;
    END
  END do0[295]
  PIN do0[296]
    DIRECTION OUTPUT ;
    USE SIGNAL ;
    PORT
      LAYER M4 ;
        RECT  17.064 16.896 17.256 16.92 ;
    END
  END do0[296]
  PIN do0[297]
    DIRECTION OUTPUT ;
    USE SIGNAL ;
    PORT
      LAYER M4 ;
        RECT  17.064 16.944 17.256 16.968 ;
    END
  END do0[297]
  PIN do0[298]
    DIRECTION OUTPUT ;
    USE SIGNAL ;
    PORT
      LAYER M4 ;
        RECT  17.064 16.992 17.256 17.016 ;
    END
  END do0[298]
  PIN do0[299]
    DIRECTION OUTPUT ;
    USE SIGNAL ;
    PORT
      LAYER M4 ;
        RECT  17.064 17.04 17.256 17.064 ;
    END
  END do0[299]
  PIN do0[29]
    DIRECTION OUTPUT ;
    USE SIGNAL ;
    PORT
      LAYER M4 ;
        RECT  17.064 4.08 17.256 4.104 ;
    END
  END do0[29]
  PIN do0[2]
    DIRECTION OUTPUT ;
    USE SIGNAL ;
    PORT
      LAYER M4 ;
        RECT  17.064 2.784 17.256 2.808 ;
    END
  END do0[2]
  PIN do0[300]
    DIRECTION OUTPUT ;
    USE SIGNAL ;
    PORT
      LAYER M4 ;
        RECT  17.064 17.088 17.256 17.112 ;
    END
  END do0[300]
  PIN do0[301]
    DIRECTION OUTPUT ;
    USE SIGNAL ;
    PORT
      LAYER M4 ;
        RECT  17.064 17.136 17.256 17.16 ;
    END
  END do0[301]
  PIN do0[302]
    DIRECTION OUTPUT ;
    USE SIGNAL ;
    PORT
      LAYER M4 ;
        RECT  17.064 17.184 17.256 17.208 ;
    END
  END do0[302]
  PIN do0[303]
    DIRECTION OUTPUT ;
    USE SIGNAL ;
    PORT
      LAYER M4 ;
        RECT  17.064 17.232 17.256 17.256 ;
    END
  END do0[303]
  PIN do0[304]
    DIRECTION OUTPUT ;
    USE SIGNAL ;
    PORT
      LAYER M4 ;
        RECT  17.064 17.28 17.256 17.304 ;
    END
  END do0[304]
  PIN do0[305]
    DIRECTION OUTPUT ;
    USE SIGNAL ;
    PORT
      LAYER M4 ;
        RECT  17.064 17.328 17.256 17.352 ;
    END
  END do0[305]
  PIN do0[306]
    DIRECTION OUTPUT ;
    USE SIGNAL ;
    PORT
      LAYER M4 ;
        RECT  17.064 17.376 17.256 17.4 ;
    END
  END do0[306]
  PIN do0[307]
    DIRECTION OUTPUT ;
    USE SIGNAL ;
    PORT
      LAYER M4 ;
        RECT  17.064 17.424 17.256 17.448 ;
    END
  END do0[307]
  PIN do0[308]
    DIRECTION OUTPUT ;
    USE SIGNAL ;
    PORT
      LAYER M4 ;
        RECT  17.064 17.472 17.256 17.496 ;
    END
  END do0[308]
  PIN do0[309]
    DIRECTION OUTPUT ;
    USE SIGNAL ;
    PORT
      LAYER M4 ;
        RECT  17.064 17.52 17.256 17.544 ;
    END
  END do0[309]
  PIN do0[30]
    DIRECTION OUTPUT ;
    USE SIGNAL ;
    PORT
      LAYER M4 ;
        RECT  17.064 4.128 17.256 4.152 ;
    END
  END do0[30]
  PIN do0[310]
    DIRECTION OUTPUT ;
    USE SIGNAL ;
    PORT
      LAYER M4 ;
        RECT  17.064 17.568 17.256 17.592 ;
    END
  END do0[310]
  PIN do0[311]
    DIRECTION OUTPUT ;
    USE SIGNAL ;
    PORT
      LAYER M4 ;
        RECT  17.064 17.616 17.256 17.64 ;
    END
  END do0[311]
  PIN do0[312]
    DIRECTION OUTPUT ;
    USE SIGNAL ;
    PORT
      LAYER M4 ;
        RECT  17.064 17.664 17.256 17.688 ;
    END
  END do0[312]
  PIN do0[313]
    DIRECTION OUTPUT ;
    USE SIGNAL ;
    PORT
      LAYER M4 ;
        RECT  17.064 17.712 17.256 17.736 ;
    END
  END do0[313]
  PIN do0[314]
    DIRECTION OUTPUT ;
    USE SIGNAL ;
    PORT
      LAYER M4 ;
        RECT  17.064 17.76 17.256 17.784 ;
    END
  END do0[314]
  PIN do0[315]
    DIRECTION OUTPUT ;
    USE SIGNAL ;
    PORT
      LAYER M4 ;
        RECT  17.064 17.808 17.256 17.832 ;
    END
  END do0[315]
  PIN do0[316]
    DIRECTION OUTPUT ;
    USE SIGNAL ;
    PORT
      LAYER M4 ;
        RECT  17.064 17.856 17.256 17.88 ;
    END
  END do0[316]
  PIN do0[317]
    DIRECTION OUTPUT ;
    USE SIGNAL ;
    PORT
      LAYER M4 ;
        RECT  17.064 17.904 17.256 17.928 ;
    END
  END do0[317]
  PIN do0[318]
    DIRECTION OUTPUT ;
    USE SIGNAL ;
    PORT
      LAYER M4 ;
        RECT  17.064 17.952 17.256 17.976 ;
    END
  END do0[318]
  PIN do0[319]
    DIRECTION OUTPUT ;
    USE SIGNAL ;
    PORT
      LAYER M4 ;
        RECT  17.064 18 17.256 18.024 ;
    END
  END do0[319]
  PIN do0[31]
    DIRECTION OUTPUT ;
    USE SIGNAL ;
    PORT
      LAYER M4 ;
        RECT  17.064 4.176 17.256 4.2 ;
    END
  END do0[31]
  PIN do0[320]
    DIRECTION OUTPUT ;
    USE SIGNAL ;
    PORT
      LAYER M4 ;
        RECT  17.064 18.048 17.256 18.072 ;
    END
  END do0[320]
  PIN do0[321]
    DIRECTION OUTPUT ;
    USE SIGNAL ;
    PORT
      LAYER M4 ;
        RECT  17.064 18.096 17.256 18.12 ;
    END
  END do0[321]
  PIN do0[322]
    DIRECTION OUTPUT ;
    USE SIGNAL ;
    PORT
      LAYER M4 ;
        RECT  17.064 18.144 17.256 18.168 ;
    END
  END do0[322]
  PIN do0[323]
    DIRECTION OUTPUT ;
    USE SIGNAL ;
    PORT
      LAYER M4 ;
        RECT  17.064 18.192 17.256 18.216 ;
    END
  END do0[323]
  PIN do0[324]
    DIRECTION OUTPUT ;
    USE SIGNAL ;
    PORT
      LAYER M4 ;
        RECT  17.064 18.24 17.256 18.264 ;
    END
  END do0[324]
  PIN do0[325]
    DIRECTION OUTPUT ;
    USE SIGNAL ;
    PORT
      LAYER M4 ;
        RECT  17.064 18.288 17.256 18.312 ;
    END
  END do0[325]
  PIN do0[326]
    DIRECTION OUTPUT ;
    USE SIGNAL ;
    PORT
      LAYER M4 ;
        RECT  17.064 18.336 17.256 18.36 ;
    END
  END do0[326]
  PIN do0[327]
    DIRECTION OUTPUT ;
    USE SIGNAL ;
    PORT
      LAYER M4 ;
        RECT  17.064 18.384 17.256 18.408 ;
    END
  END do0[327]
  PIN do0[328]
    DIRECTION OUTPUT ;
    USE SIGNAL ;
    PORT
      LAYER M4 ;
        RECT  17.064 18.432 17.256 18.456 ;
    END
  END do0[328]
  PIN do0[329]
    DIRECTION OUTPUT ;
    USE SIGNAL ;
    PORT
      LAYER M4 ;
        RECT  17.064 18.48 17.256 18.504 ;
    END
  END do0[329]
  PIN do0[32]
    DIRECTION OUTPUT ;
    USE SIGNAL ;
    PORT
      LAYER M4 ;
        RECT  17.064 4.224 17.256 4.248 ;
    END
  END do0[32]
  PIN do0[330]
    DIRECTION OUTPUT ;
    USE SIGNAL ;
    PORT
      LAYER M4 ;
        RECT  17.064 18.528 17.256 18.552 ;
    END
  END do0[330]
  PIN do0[331]
    DIRECTION OUTPUT ;
    USE SIGNAL ;
    PORT
      LAYER M4 ;
        RECT  17.064 18.576 17.256 18.6 ;
    END
  END do0[331]
  PIN do0[332]
    DIRECTION OUTPUT ;
    USE SIGNAL ;
    PORT
      LAYER M4 ;
        RECT  17.064 18.624 17.256 18.648 ;
    END
  END do0[332]
  PIN do0[333]
    DIRECTION OUTPUT ;
    USE SIGNAL ;
    PORT
      LAYER M4 ;
        RECT  17.064 18.672 17.256 18.696 ;
    END
  END do0[333]
  PIN do0[334]
    DIRECTION OUTPUT ;
    USE SIGNAL ;
    PORT
      LAYER M4 ;
        RECT  17.064 18.72 17.256 18.744 ;
    END
  END do0[334]
  PIN do0[335]
    DIRECTION OUTPUT ;
    USE SIGNAL ;
    PORT
      LAYER M4 ;
        RECT  17.064 18.768 17.256 18.792 ;
    END
  END do0[335]
  PIN do0[336]
    DIRECTION OUTPUT ;
    USE SIGNAL ;
    PORT
      LAYER M4 ;
        RECT  17.064 18.816 17.256 18.84 ;
    END
  END do0[336]
  PIN do0[337]
    DIRECTION OUTPUT ;
    USE SIGNAL ;
    PORT
      LAYER M4 ;
        RECT  17.064 18.864 17.256 18.888 ;
    END
  END do0[337]
  PIN do0[338]
    DIRECTION OUTPUT ;
    USE SIGNAL ;
    PORT
      LAYER M4 ;
        RECT  17.064 18.912 17.256 18.936 ;
    END
  END do0[338]
  PIN do0[339]
    DIRECTION OUTPUT ;
    USE SIGNAL ;
    PORT
      LAYER M4 ;
        RECT  17.064 18.96 17.256 18.984 ;
    END
  END do0[339]
  PIN do0[33]
    DIRECTION OUTPUT ;
    USE SIGNAL ;
    PORT
      LAYER M4 ;
        RECT  17.064 4.272 17.256 4.296 ;
    END
  END do0[33]
  PIN do0[340]
    DIRECTION OUTPUT ;
    USE SIGNAL ;
    PORT
      LAYER M4 ;
        RECT  17.064 19.008 17.256 19.032 ;
    END
  END do0[340]
  PIN do0[341]
    DIRECTION OUTPUT ;
    USE SIGNAL ;
    PORT
      LAYER M4 ;
        RECT  17.064 19.056 17.256 19.08 ;
    END
  END do0[341]
  PIN do0[342]
    DIRECTION OUTPUT ;
    USE SIGNAL ;
    PORT
      LAYER M4 ;
        RECT  17.064 19.104 17.256 19.128 ;
    END
  END do0[342]
  PIN do0[343]
    DIRECTION OUTPUT ;
    USE SIGNAL ;
    PORT
      LAYER M4 ;
        RECT  17.064 19.152 17.256 19.176 ;
    END
  END do0[343]
  PIN do0[344]
    DIRECTION OUTPUT ;
    USE SIGNAL ;
    PORT
      LAYER M4 ;
        RECT  17.064 19.2 17.256 19.224 ;
    END
  END do0[344]
  PIN do0[345]
    DIRECTION OUTPUT ;
    USE SIGNAL ;
    PORT
      LAYER M4 ;
        RECT  17.064 19.248 17.256 19.272 ;
    END
  END do0[345]
  PIN do0[346]
    DIRECTION OUTPUT ;
    USE SIGNAL ;
    PORT
      LAYER M4 ;
        RECT  17.064 19.296 17.256 19.32 ;
    END
  END do0[346]
  PIN do0[347]
    DIRECTION OUTPUT ;
    USE SIGNAL ;
    PORT
      LAYER M4 ;
        RECT  17.064 19.344 17.256 19.368 ;
    END
  END do0[347]
  PIN do0[348]
    DIRECTION OUTPUT ;
    USE SIGNAL ;
    PORT
      LAYER M4 ;
        RECT  17.064 19.392 17.256 19.416 ;
    END
  END do0[348]
  PIN do0[349]
    DIRECTION OUTPUT ;
    USE SIGNAL ;
    PORT
      LAYER M4 ;
        RECT  17.064 19.44 17.256 19.464 ;
    END
  END do0[349]
  PIN do0[34]
    DIRECTION OUTPUT ;
    USE SIGNAL ;
    PORT
      LAYER M4 ;
        RECT  17.064 4.32 17.256 4.344 ;
    END
  END do0[34]
  PIN do0[350]
    DIRECTION OUTPUT ;
    USE SIGNAL ;
    PORT
      LAYER M4 ;
        RECT  17.064 19.488 17.256 19.512 ;
    END
  END do0[350]
  PIN do0[351]
    DIRECTION OUTPUT ;
    USE SIGNAL ;
    PORT
      LAYER M4 ;
        RECT  17.064 19.536 17.256 19.56 ;
    END
  END do0[351]
  PIN do0[352]
    DIRECTION OUTPUT ;
    USE SIGNAL ;
    PORT
      LAYER M4 ;
        RECT  17.064 19.584 17.256 19.608 ;
    END
  END do0[352]
  PIN do0[353]
    DIRECTION OUTPUT ;
    USE SIGNAL ;
    PORT
      LAYER M4 ;
        RECT  17.064 19.632 17.256 19.656 ;
    END
  END do0[353]
  PIN do0[354]
    DIRECTION OUTPUT ;
    USE SIGNAL ;
    PORT
      LAYER M4 ;
        RECT  17.064 19.68 17.256 19.704 ;
    END
  END do0[354]
  PIN do0[355]
    DIRECTION OUTPUT ;
    USE SIGNAL ;
    PORT
      LAYER M4 ;
        RECT  17.064 19.728 17.256 19.752 ;
    END
  END do0[355]
  PIN do0[356]
    DIRECTION OUTPUT ;
    USE SIGNAL ;
    PORT
      LAYER M4 ;
        RECT  17.064 19.776 17.256 19.8 ;
    END
  END do0[356]
  PIN do0[357]
    DIRECTION OUTPUT ;
    USE SIGNAL ;
    PORT
      LAYER M4 ;
        RECT  17.064 19.824 17.256 19.848 ;
    END
  END do0[357]
  PIN do0[358]
    DIRECTION OUTPUT ;
    USE SIGNAL ;
    PORT
      LAYER M4 ;
        RECT  17.064 19.872 17.256 19.896 ;
    END
  END do0[358]
  PIN do0[359]
    DIRECTION OUTPUT ;
    USE SIGNAL ;
    PORT
      LAYER M4 ;
        RECT  17.064 19.92 17.256 19.944 ;
    END
  END do0[359]
  PIN do0[35]
    DIRECTION OUTPUT ;
    USE SIGNAL ;
    PORT
      LAYER M4 ;
        RECT  17.064 4.368 17.256 4.392 ;
    END
  END do0[35]
  PIN do0[360]
    DIRECTION OUTPUT ;
    USE SIGNAL ;
    PORT
      LAYER M4 ;
        RECT  17.064 19.968 17.256 19.992 ;
    END
  END do0[360]
  PIN do0[361]
    DIRECTION OUTPUT ;
    USE SIGNAL ;
    PORT
      LAYER M4 ;
        RECT  17.064 20.016 17.256 20.04 ;
    END
  END do0[361]
  PIN do0[362]
    DIRECTION OUTPUT ;
    USE SIGNAL ;
    PORT
      LAYER M4 ;
        RECT  17.064 20.064 17.256 20.088 ;
    END
  END do0[362]
  PIN do0[363]
    DIRECTION OUTPUT ;
    USE SIGNAL ;
    PORT
      LAYER M4 ;
        RECT  17.064 20.112 17.256 20.136 ;
    END
  END do0[363]
  PIN do0[364]
    DIRECTION OUTPUT ;
    USE SIGNAL ;
    PORT
      LAYER M4 ;
        RECT  17.064 20.16 17.256 20.184 ;
    END
  END do0[364]
  PIN do0[365]
    DIRECTION OUTPUT ;
    USE SIGNAL ;
    PORT
      LAYER M4 ;
        RECT  17.064 20.208 17.256 20.232 ;
    END
  END do0[365]
  PIN do0[366]
    DIRECTION OUTPUT ;
    USE SIGNAL ;
    PORT
      LAYER M4 ;
        RECT  17.064 20.256 17.256 20.28 ;
    END
  END do0[366]
  PIN do0[367]
    DIRECTION OUTPUT ;
    USE SIGNAL ;
    PORT
      LAYER M4 ;
        RECT  17.064 20.304 17.256 20.328 ;
    END
  END do0[367]
  PIN do0[368]
    DIRECTION OUTPUT ;
    USE SIGNAL ;
    PORT
      LAYER M4 ;
        RECT  17.064 20.352 17.256 20.376 ;
    END
  END do0[368]
  PIN do0[369]
    DIRECTION OUTPUT ;
    USE SIGNAL ;
    PORT
      LAYER M4 ;
        RECT  17.064 20.4 17.256 20.424 ;
    END
  END do0[369]
  PIN do0[36]
    DIRECTION OUTPUT ;
    USE SIGNAL ;
    PORT
      LAYER M4 ;
        RECT  17.064 4.416 17.256 4.44 ;
    END
  END do0[36]
  PIN do0[370]
    DIRECTION OUTPUT ;
    USE SIGNAL ;
    PORT
      LAYER M4 ;
        RECT  17.064 20.448 17.256 20.472 ;
    END
  END do0[370]
  PIN do0[371]
    DIRECTION OUTPUT ;
    USE SIGNAL ;
    PORT
      LAYER M4 ;
        RECT  17.064 20.496 17.256 20.52 ;
    END
  END do0[371]
  PIN do0[372]
    DIRECTION OUTPUT ;
    USE SIGNAL ;
    PORT
      LAYER M4 ;
        RECT  17.064 20.544 17.256 20.568 ;
    END
  END do0[372]
  PIN do0[373]
    DIRECTION OUTPUT ;
    USE SIGNAL ;
    PORT
      LAYER M4 ;
        RECT  17.064 20.592 17.256 20.616 ;
    END
  END do0[373]
  PIN do0[374]
    DIRECTION OUTPUT ;
    USE SIGNAL ;
    PORT
      LAYER M4 ;
        RECT  17.064 20.64 17.256 20.664 ;
    END
  END do0[374]
  PIN do0[375]
    DIRECTION OUTPUT ;
    USE SIGNAL ;
    PORT
      LAYER M4 ;
        RECT  17.064 20.688 17.256 20.712 ;
    END
  END do0[375]
  PIN do0[376]
    DIRECTION OUTPUT ;
    USE SIGNAL ;
    PORT
      LAYER M4 ;
        RECT  17.064 20.736 17.256 20.76 ;
    END
  END do0[376]
  PIN do0[377]
    DIRECTION OUTPUT ;
    USE SIGNAL ;
    PORT
      LAYER M4 ;
        RECT  17.064 20.784 17.256 20.808 ;
    END
  END do0[377]
  PIN do0[378]
    DIRECTION OUTPUT ;
    USE SIGNAL ;
    PORT
      LAYER M4 ;
        RECT  17.064 20.832 17.256 20.856 ;
    END
  END do0[378]
  PIN do0[379]
    DIRECTION OUTPUT ;
    USE SIGNAL ;
    PORT
      LAYER M4 ;
        RECT  17.064 20.88 17.256 20.904 ;
    END
  END do0[379]
  PIN do0[37]
    DIRECTION OUTPUT ;
    USE SIGNAL ;
    PORT
      LAYER M4 ;
        RECT  17.064 4.464 17.256 4.488 ;
    END
  END do0[37]
  PIN do0[380]
    DIRECTION OUTPUT ;
    USE SIGNAL ;
    PORT
      LAYER M4 ;
        RECT  17.064 20.928 17.256 20.952 ;
    END
  END do0[380]
  PIN do0[381]
    DIRECTION OUTPUT ;
    USE SIGNAL ;
    PORT
      LAYER M4 ;
        RECT  17.064 20.976 17.256 21 ;
    END
  END do0[381]
  PIN do0[382]
    DIRECTION OUTPUT ;
    USE SIGNAL ;
    PORT
      LAYER M4 ;
        RECT  17.064 21.024 17.256 21.048 ;
    END
  END do0[382]
  PIN do0[383]
    DIRECTION OUTPUT ;
    USE SIGNAL ;
    PORT
      LAYER M4 ;
        RECT  17.064 21.072 17.256 21.096 ;
    END
  END do0[383]
  PIN do0[384]
    DIRECTION OUTPUT ;
    USE SIGNAL ;
    PORT
      LAYER M4 ;
        RECT  17.064 21.12 17.256 21.144 ;
    END
  END do0[384]
  PIN do0[385]
    DIRECTION OUTPUT ;
    USE SIGNAL ;
    PORT
      LAYER M4 ;
        RECT  17.064 21.168 17.256 21.192 ;
    END
  END do0[385]
  PIN do0[386]
    DIRECTION OUTPUT ;
    USE SIGNAL ;
    PORT
      LAYER M4 ;
        RECT  17.064 21.216 17.256 21.24 ;
    END
  END do0[386]
  PIN do0[387]
    DIRECTION OUTPUT ;
    USE SIGNAL ;
    PORT
      LAYER M4 ;
        RECT  17.064 21.264 17.256 21.288 ;
    END
  END do0[387]
  PIN do0[388]
    DIRECTION OUTPUT ;
    USE SIGNAL ;
    PORT
      LAYER M4 ;
        RECT  17.064 21.312 17.256 21.336 ;
    END
  END do0[388]
  PIN do0[389]
    DIRECTION OUTPUT ;
    USE SIGNAL ;
    PORT
      LAYER M4 ;
        RECT  17.064 21.36 17.256 21.384 ;
    END
  END do0[389]
  PIN do0[38]
    DIRECTION OUTPUT ;
    USE SIGNAL ;
    PORT
      LAYER M4 ;
        RECT  17.064 4.512 17.256 4.536 ;
    END
  END do0[38]
  PIN do0[390]
    DIRECTION OUTPUT ;
    USE SIGNAL ;
    PORT
      LAYER M4 ;
        RECT  17.064 21.408 17.256 21.432 ;
    END
  END do0[390]
  PIN do0[391]
    DIRECTION OUTPUT ;
    USE SIGNAL ;
    PORT
      LAYER M4 ;
        RECT  17.064 21.456 17.256 21.48 ;
    END
  END do0[391]
  PIN do0[392]
    DIRECTION OUTPUT ;
    USE SIGNAL ;
    PORT
      LAYER M4 ;
        RECT  17.064 21.504 17.256 21.528 ;
    END
  END do0[392]
  PIN do0[393]
    DIRECTION OUTPUT ;
    USE SIGNAL ;
    PORT
      LAYER M4 ;
        RECT  17.064 21.552 17.256 21.576 ;
    END
  END do0[393]
  PIN do0[394]
    DIRECTION OUTPUT ;
    USE SIGNAL ;
    PORT
      LAYER M4 ;
        RECT  17.064 21.6 17.256 21.624 ;
    END
  END do0[394]
  PIN do0[395]
    DIRECTION OUTPUT ;
    USE SIGNAL ;
    PORT
      LAYER M4 ;
        RECT  17.064 21.648 17.256 21.672 ;
    END
  END do0[395]
  PIN do0[396]
    DIRECTION OUTPUT ;
    USE SIGNAL ;
    PORT
      LAYER M4 ;
        RECT  17.064 21.696 17.256 21.72 ;
    END
  END do0[396]
  PIN do0[397]
    DIRECTION OUTPUT ;
    USE SIGNAL ;
    PORT
      LAYER M4 ;
        RECT  17.064 21.744 17.256 21.768 ;
    END
  END do0[397]
  PIN do0[398]
    DIRECTION OUTPUT ;
    USE SIGNAL ;
    PORT
      LAYER M4 ;
        RECT  17.064 21.792 17.256 21.816 ;
    END
  END do0[398]
  PIN do0[399]
    DIRECTION OUTPUT ;
    USE SIGNAL ;
    PORT
      LAYER M4 ;
        RECT  17.064 21.84 17.256 21.864 ;
    END
  END do0[399]
  PIN do0[39]
    DIRECTION OUTPUT ;
    USE SIGNAL ;
    PORT
      LAYER M4 ;
        RECT  17.064 4.56 17.256 4.584 ;
    END
  END do0[39]
  PIN do0[3]
    DIRECTION OUTPUT ;
    USE SIGNAL ;
    PORT
      LAYER M4 ;
        RECT  17.064 2.832 17.256 2.856 ;
    END
  END do0[3]
  PIN do0[400]
    DIRECTION OUTPUT ;
    USE SIGNAL ;
    PORT
      LAYER M4 ;
        RECT  17.064 21.888 17.256 21.912 ;
    END
  END do0[400]
  PIN do0[401]
    DIRECTION OUTPUT ;
    USE SIGNAL ;
    PORT
      LAYER M4 ;
        RECT  17.064 21.936 17.256 21.96 ;
    END
  END do0[401]
  PIN do0[402]
    DIRECTION OUTPUT ;
    USE SIGNAL ;
    PORT
      LAYER M4 ;
        RECT  17.064 21.984 17.256 22.008 ;
    END
  END do0[402]
  PIN do0[403]
    DIRECTION OUTPUT ;
    USE SIGNAL ;
    PORT
      LAYER M4 ;
        RECT  17.064 22.032 17.256 22.056 ;
    END
  END do0[403]
  PIN do0[404]
    DIRECTION OUTPUT ;
    USE SIGNAL ;
    PORT
      LAYER M4 ;
        RECT  17.064 22.08 17.256 22.104 ;
    END
  END do0[404]
  PIN do0[405]
    DIRECTION OUTPUT ;
    USE SIGNAL ;
    PORT
      LAYER M4 ;
        RECT  17.064 22.128 17.256 22.152 ;
    END
  END do0[405]
  PIN do0[406]
    DIRECTION OUTPUT ;
    USE SIGNAL ;
    PORT
      LAYER M4 ;
        RECT  17.064 22.176 17.256 22.2 ;
    END
  END do0[406]
  PIN do0[407]
    DIRECTION OUTPUT ;
    USE SIGNAL ;
    PORT
      LAYER M4 ;
        RECT  17.064 22.224 17.256 22.248 ;
    END
  END do0[407]
  PIN do0[408]
    DIRECTION OUTPUT ;
    USE SIGNAL ;
    PORT
      LAYER M4 ;
        RECT  17.064 22.272 17.256 22.296 ;
    END
  END do0[408]
  PIN do0[409]
    DIRECTION OUTPUT ;
    USE SIGNAL ;
    PORT
      LAYER M4 ;
        RECT  17.064 22.32 17.256 22.344 ;
    END
  END do0[409]
  PIN do0[40]
    DIRECTION OUTPUT ;
    USE SIGNAL ;
    PORT
      LAYER M4 ;
        RECT  17.064 4.608 17.256 4.632 ;
    END
  END do0[40]
  PIN do0[410]
    DIRECTION OUTPUT ;
    USE SIGNAL ;
    PORT
      LAYER M4 ;
        RECT  17.064 22.368 17.256 22.392 ;
    END
  END do0[410]
  PIN do0[411]
    DIRECTION OUTPUT ;
    USE SIGNAL ;
    PORT
      LAYER M4 ;
        RECT  17.064 22.416 17.256 22.44 ;
    END
  END do0[411]
  PIN do0[412]
    DIRECTION OUTPUT ;
    USE SIGNAL ;
    PORT
      LAYER M4 ;
        RECT  17.064 22.464 17.256 22.488 ;
    END
  END do0[412]
  PIN do0[413]
    DIRECTION OUTPUT ;
    USE SIGNAL ;
    PORT
      LAYER M4 ;
        RECT  17.064 22.512 17.256 22.536 ;
    END
  END do0[413]
  PIN do0[414]
    DIRECTION OUTPUT ;
    USE SIGNAL ;
    PORT
      LAYER M4 ;
        RECT  17.064 22.56 17.256 22.584 ;
    END
  END do0[414]
  PIN do0[415]
    DIRECTION OUTPUT ;
    USE SIGNAL ;
    PORT
      LAYER M4 ;
        RECT  17.064 22.608 17.256 22.632 ;
    END
  END do0[415]
  PIN do0[416]
    DIRECTION OUTPUT ;
    USE SIGNAL ;
    PORT
      LAYER M4 ;
        RECT  17.064 22.656 17.256 22.68 ;
    END
  END do0[416]
  PIN do0[417]
    DIRECTION OUTPUT ;
    USE SIGNAL ;
    PORT
      LAYER M4 ;
        RECT  17.064 22.704 17.256 22.728 ;
    END
  END do0[417]
  PIN do0[418]
    DIRECTION OUTPUT ;
    USE SIGNAL ;
    PORT
      LAYER M4 ;
        RECT  17.064 22.752 17.256 22.776 ;
    END
  END do0[418]
  PIN do0[419]
    DIRECTION OUTPUT ;
    USE SIGNAL ;
    PORT
      LAYER M4 ;
        RECT  17.064 22.8 17.256 22.824 ;
    END
  END do0[419]
  PIN do0[41]
    DIRECTION OUTPUT ;
    USE SIGNAL ;
    PORT
      LAYER M4 ;
        RECT  17.064 4.656 17.256 4.68 ;
    END
  END do0[41]
  PIN do0[420]
    DIRECTION OUTPUT ;
    USE SIGNAL ;
    PORT
      LAYER M4 ;
        RECT  17.064 22.848 17.256 22.872 ;
    END
  END do0[420]
  PIN do0[421]
    DIRECTION OUTPUT ;
    USE SIGNAL ;
    PORT
      LAYER M4 ;
        RECT  17.064 22.896 17.256 22.92 ;
    END
  END do0[421]
  PIN do0[422]
    DIRECTION OUTPUT ;
    USE SIGNAL ;
    PORT
      LAYER M4 ;
        RECT  17.064 22.944 17.256 22.968 ;
    END
  END do0[422]
  PIN do0[423]
    DIRECTION OUTPUT ;
    USE SIGNAL ;
    PORT
      LAYER M4 ;
        RECT  17.064 22.992 17.256 23.016 ;
    END
  END do0[423]
  PIN do0[424]
    DIRECTION OUTPUT ;
    USE SIGNAL ;
    PORT
      LAYER M4 ;
        RECT  17.064 23.04 17.256 23.064 ;
    END
  END do0[424]
  PIN do0[425]
    DIRECTION OUTPUT ;
    USE SIGNAL ;
    PORT
      LAYER M4 ;
        RECT  17.064 23.088 17.256 23.112 ;
    END
  END do0[425]
  PIN do0[426]
    DIRECTION OUTPUT ;
    USE SIGNAL ;
    PORT
      LAYER M4 ;
        RECT  17.064 23.136 17.256 23.16 ;
    END
  END do0[426]
  PIN do0[427]
    DIRECTION OUTPUT ;
    USE SIGNAL ;
    PORT
      LAYER M4 ;
        RECT  17.064 23.184 17.256 23.208 ;
    END
  END do0[427]
  PIN do0[428]
    DIRECTION OUTPUT ;
    USE SIGNAL ;
    PORT
      LAYER M4 ;
        RECT  17.064 23.232 17.256 23.256 ;
    END
  END do0[428]
  PIN do0[429]
    DIRECTION OUTPUT ;
    USE SIGNAL ;
    PORT
      LAYER M4 ;
        RECT  17.064 23.28 17.256 23.304 ;
    END
  END do0[429]
  PIN do0[42]
    DIRECTION OUTPUT ;
    USE SIGNAL ;
    PORT
      LAYER M4 ;
        RECT  17.064 4.704 17.256 4.728 ;
    END
  END do0[42]
  PIN do0[430]
    DIRECTION OUTPUT ;
    USE SIGNAL ;
    PORT
      LAYER M4 ;
        RECT  17.064 23.328 17.256 23.352 ;
    END
  END do0[430]
  PIN do0[431]
    DIRECTION OUTPUT ;
    USE SIGNAL ;
    PORT
      LAYER M4 ;
        RECT  17.064 23.376 17.256 23.4 ;
    END
  END do0[431]
  PIN do0[432]
    DIRECTION OUTPUT ;
    USE SIGNAL ;
    PORT
      LAYER M4 ;
        RECT  17.064 23.424 17.256 23.448 ;
    END
  END do0[432]
  PIN do0[433]
    DIRECTION OUTPUT ;
    USE SIGNAL ;
    PORT
      LAYER M4 ;
        RECT  17.064 23.472 17.256 23.496 ;
    END
  END do0[433]
  PIN do0[434]
    DIRECTION OUTPUT ;
    USE SIGNAL ;
    PORT
      LAYER M4 ;
        RECT  17.064 23.52 17.256 23.544 ;
    END
  END do0[434]
  PIN do0[435]
    DIRECTION OUTPUT ;
    USE SIGNAL ;
    PORT
      LAYER M4 ;
        RECT  17.064 23.568 17.256 23.592 ;
    END
  END do0[435]
  PIN do0[436]
    DIRECTION OUTPUT ;
    USE SIGNAL ;
    PORT
      LAYER M4 ;
        RECT  17.064 23.616 17.256 23.64 ;
    END
  END do0[436]
  PIN do0[437]
    DIRECTION OUTPUT ;
    USE SIGNAL ;
    PORT
      LAYER M4 ;
        RECT  17.064 23.664 17.256 23.688 ;
    END
  END do0[437]
  PIN do0[438]
    DIRECTION OUTPUT ;
    USE SIGNAL ;
    PORT
      LAYER M4 ;
        RECT  17.064 23.712 17.256 23.736 ;
    END
  END do0[438]
  PIN do0[439]
    DIRECTION OUTPUT ;
    USE SIGNAL ;
    PORT
      LAYER M4 ;
        RECT  17.064 23.76 17.256 23.784 ;
    END
  END do0[439]
  PIN do0[43]
    DIRECTION OUTPUT ;
    USE SIGNAL ;
    PORT
      LAYER M4 ;
        RECT  17.064 4.752 17.256 4.776 ;
    END
  END do0[43]
  PIN do0[440]
    DIRECTION OUTPUT ;
    USE SIGNAL ;
    PORT
      LAYER M4 ;
        RECT  17.064 23.808 17.256 23.832 ;
    END
  END do0[440]
  PIN do0[441]
    DIRECTION OUTPUT ;
    USE SIGNAL ;
    PORT
      LAYER M4 ;
        RECT  17.064 23.856 17.256 23.88 ;
    END
  END do0[441]
  PIN do0[442]
    DIRECTION OUTPUT ;
    USE SIGNAL ;
    PORT
      LAYER M4 ;
        RECT  17.064 23.904 17.256 23.928 ;
    END
  END do0[442]
  PIN do0[443]
    DIRECTION OUTPUT ;
    USE SIGNAL ;
    PORT
      LAYER M4 ;
        RECT  17.064 23.952 17.256 23.976 ;
    END
  END do0[443]
  PIN do0[444]
    DIRECTION OUTPUT ;
    USE SIGNAL ;
    PORT
      LAYER M4 ;
        RECT  17.064 24 17.256 24.024 ;
    END
  END do0[444]
  PIN do0[445]
    DIRECTION OUTPUT ;
    USE SIGNAL ;
    PORT
      LAYER M4 ;
        RECT  17.064 24.048 17.256 24.072 ;
    END
  END do0[445]
  PIN do0[446]
    DIRECTION OUTPUT ;
    USE SIGNAL ;
    PORT
      LAYER M4 ;
        RECT  17.064 24.096 17.256 24.12 ;
    END
  END do0[446]
  PIN do0[447]
    DIRECTION OUTPUT ;
    USE SIGNAL ;
    PORT
      LAYER M4 ;
        RECT  17.064 24.144 17.256 24.168 ;
    END
  END do0[447]
  PIN do0[448]
    DIRECTION OUTPUT ;
    USE SIGNAL ;
    PORT
      LAYER M4 ;
        RECT  17.064 24.192 17.256 24.216 ;
    END
  END do0[448]
  PIN do0[449]
    DIRECTION OUTPUT ;
    USE SIGNAL ;
    PORT
      LAYER M4 ;
        RECT  17.064 24.24 17.256 24.264 ;
    END
  END do0[449]
  PIN do0[44]
    DIRECTION OUTPUT ;
    USE SIGNAL ;
    PORT
      LAYER M4 ;
        RECT  17.064 4.8 17.256 4.824 ;
    END
  END do0[44]
  PIN do0[450]
    DIRECTION OUTPUT ;
    USE SIGNAL ;
    PORT
      LAYER M4 ;
        RECT  17.064 24.288 17.256 24.312 ;
    END
  END do0[450]
  PIN do0[451]
    DIRECTION OUTPUT ;
    USE SIGNAL ;
    PORT
      LAYER M4 ;
        RECT  17.064 24.336 17.256 24.36 ;
    END
  END do0[451]
  PIN do0[452]
    DIRECTION OUTPUT ;
    USE SIGNAL ;
    PORT
      LAYER M4 ;
        RECT  17.064 24.384 17.256 24.408 ;
    END
  END do0[452]
  PIN do0[453]
    DIRECTION OUTPUT ;
    USE SIGNAL ;
    PORT
      LAYER M4 ;
        RECT  17.064 24.432 17.256 24.456 ;
    END
  END do0[453]
  PIN do0[454]
    DIRECTION OUTPUT ;
    USE SIGNAL ;
    PORT
      LAYER M4 ;
        RECT  17.064 24.48 17.256 24.504 ;
    END
  END do0[454]
  PIN do0[455]
    DIRECTION OUTPUT ;
    USE SIGNAL ;
    PORT
      LAYER M4 ;
        RECT  17.064 24.528 17.256 24.552 ;
    END
  END do0[455]
  PIN do0[456]
    DIRECTION OUTPUT ;
    USE SIGNAL ;
    PORT
      LAYER M4 ;
        RECT  17.064 24.576 17.256 24.6 ;
    END
  END do0[456]
  PIN do0[457]
    DIRECTION OUTPUT ;
    USE SIGNAL ;
    PORT
      LAYER M4 ;
        RECT  17.064 24.624 17.256 24.648 ;
    END
  END do0[457]
  PIN do0[458]
    DIRECTION OUTPUT ;
    USE SIGNAL ;
    PORT
      LAYER M4 ;
        RECT  17.064 24.672 17.256 24.696 ;
    END
  END do0[458]
  PIN do0[459]
    DIRECTION OUTPUT ;
    USE SIGNAL ;
    PORT
      LAYER M4 ;
        RECT  17.064 24.72 17.256 24.744 ;
    END
  END do0[459]
  PIN do0[45]
    DIRECTION OUTPUT ;
    USE SIGNAL ;
    PORT
      LAYER M4 ;
        RECT  17.064 4.848 17.256 4.872 ;
    END
  END do0[45]
  PIN do0[460]
    DIRECTION OUTPUT ;
    USE SIGNAL ;
    PORT
      LAYER M4 ;
        RECT  17.064 24.768 17.256 24.792 ;
    END
  END do0[460]
  PIN do0[461]
    DIRECTION OUTPUT ;
    USE SIGNAL ;
    PORT
      LAYER M4 ;
        RECT  17.064 24.816 17.256 24.84 ;
    END
  END do0[461]
  PIN do0[462]
    DIRECTION OUTPUT ;
    USE SIGNAL ;
    PORT
      LAYER M4 ;
        RECT  17.064 24.864 17.256 24.888 ;
    END
  END do0[462]
  PIN do0[463]
    DIRECTION OUTPUT ;
    USE SIGNAL ;
    PORT
      LAYER M4 ;
        RECT  17.064 24.912 17.256 24.936 ;
    END
  END do0[463]
  PIN do0[464]
    DIRECTION OUTPUT ;
    USE SIGNAL ;
    PORT
      LAYER M4 ;
        RECT  17.064 24.96 17.256 24.984 ;
    END
  END do0[464]
  PIN do0[465]
    DIRECTION OUTPUT ;
    USE SIGNAL ;
    PORT
      LAYER M4 ;
        RECT  17.064 25.008 17.256 25.032 ;
    END
  END do0[465]
  PIN do0[466]
    DIRECTION OUTPUT ;
    USE SIGNAL ;
    PORT
      LAYER M4 ;
        RECT  17.064 25.056 17.256 25.08 ;
    END
  END do0[466]
  PIN do0[467]
    DIRECTION OUTPUT ;
    USE SIGNAL ;
    PORT
      LAYER M4 ;
        RECT  17.064 25.104 17.256 25.128 ;
    END
  END do0[467]
  PIN do0[468]
    DIRECTION OUTPUT ;
    USE SIGNAL ;
    PORT
      LAYER M4 ;
        RECT  17.064 25.152 17.256 25.176 ;
    END
  END do0[468]
  PIN do0[469]
    DIRECTION OUTPUT ;
    USE SIGNAL ;
    PORT
      LAYER M4 ;
        RECT  17.064 25.2 17.256 25.224 ;
    END
  END do0[469]
  PIN do0[46]
    DIRECTION OUTPUT ;
    USE SIGNAL ;
    PORT
      LAYER M4 ;
        RECT  17.064 4.896 17.256 4.92 ;
    END
  END do0[46]
  PIN do0[470]
    DIRECTION OUTPUT ;
    USE SIGNAL ;
    PORT
      LAYER M4 ;
        RECT  17.064 25.248 17.256 25.272 ;
    END
  END do0[470]
  PIN do0[471]
    DIRECTION OUTPUT ;
    USE SIGNAL ;
    PORT
      LAYER M4 ;
        RECT  17.064 25.296 17.256 25.32 ;
    END
  END do0[471]
  PIN do0[472]
    DIRECTION OUTPUT ;
    USE SIGNAL ;
    PORT
      LAYER M4 ;
        RECT  17.064 25.344 17.256 25.368 ;
    END
  END do0[472]
  PIN do0[473]
    DIRECTION OUTPUT ;
    USE SIGNAL ;
    PORT
      LAYER M4 ;
        RECT  17.064 25.392 17.256 25.416 ;
    END
  END do0[473]
  PIN do0[474]
    DIRECTION OUTPUT ;
    USE SIGNAL ;
    PORT
      LAYER M4 ;
        RECT  17.064 25.44 17.256 25.464 ;
    END
  END do0[474]
  PIN do0[475]
    DIRECTION OUTPUT ;
    USE SIGNAL ;
    PORT
      LAYER M4 ;
        RECT  17.064 25.488 17.256 25.512 ;
    END
  END do0[475]
  PIN do0[476]
    DIRECTION OUTPUT ;
    USE SIGNAL ;
    PORT
      LAYER M4 ;
        RECT  17.064 25.536 17.256 25.56 ;
    END
  END do0[476]
  PIN do0[477]
    DIRECTION OUTPUT ;
    USE SIGNAL ;
    PORT
      LAYER M4 ;
        RECT  17.064 25.584 17.256 25.608 ;
    END
  END do0[477]
  PIN do0[478]
    DIRECTION OUTPUT ;
    USE SIGNAL ;
    PORT
      LAYER M4 ;
        RECT  17.064 25.632 17.256 25.656 ;
    END
  END do0[478]
  PIN do0[479]
    DIRECTION OUTPUT ;
    USE SIGNAL ;
    PORT
      LAYER M4 ;
        RECT  17.064 25.68 17.256 25.704 ;
    END
  END do0[479]
  PIN do0[47]
    DIRECTION OUTPUT ;
    USE SIGNAL ;
    PORT
      LAYER M4 ;
        RECT  17.064 4.944 17.256 4.968 ;
    END
  END do0[47]
  PIN do0[480]
    DIRECTION OUTPUT ;
    USE SIGNAL ;
    PORT
      LAYER M4 ;
        RECT  17.064 25.728 17.256 25.752 ;
    END
  END do0[480]
  PIN do0[481]
    DIRECTION OUTPUT ;
    USE SIGNAL ;
    PORT
      LAYER M4 ;
        RECT  17.064 25.776 17.256 25.8 ;
    END
  END do0[481]
  PIN do0[482]
    DIRECTION OUTPUT ;
    USE SIGNAL ;
    PORT
      LAYER M4 ;
        RECT  17.064 25.824 17.256 25.848 ;
    END
  END do0[482]
  PIN do0[483]
    DIRECTION OUTPUT ;
    USE SIGNAL ;
    PORT
      LAYER M4 ;
        RECT  17.064 25.872 17.256 25.896 ;
    END
  END do0[483]
  PIN do0[484]
    DIRECTION OUTPUT ;
    USE SIGNAL ;
    PORT
      LAYER M4 ;
        RECT  17.064 25.92 17.256 25.944 ;
    END
  END do0[484]
  PIN do0[485]
    DIRECTION OUTPUT ;
    USE SIGNAL ;
    PORT
      LAYER M4 ;
        RECT  17.064 25.968 17.256 25.992 ;
    END
  END do0[485]
  PIN do0[486]
    DIRECTION OUTPUT ;
    USE SIGNAL ;
    PORT
      LAYER M4 ;
        RECT  17.064 26.016 17.256 26.04 ;
    END
  END do0[486]
  PIN do0[487]
    DIRECTION OUTPUT ;
    USE SIGNAL ;
    PORT
      LAYER M4 ;
        RECT  17.064 26.064 17.256 26.088 ;
    END
  END do0[487]
  PIN do0[488]
    DIRECTION OUTPUT ;
    USE SIGNAL ;
    PORT
      LAYER M4 ;
        RECT  17.064 26.112 17.256 26.136 ;
    END
  END do0[488]
  PIN do0[489]
    DIRECTION OUTPUT ;
    USE SIGNAL ;
    PORT
      LAYER M4 ;
        RECT  17.064 26.16 17.256 26.184 ;
    END
  END do0[489]
  PIN do0[48]
    DIRECTION OUTPUT ;
    USE SIGNAL ;
    PORT
      LAYER M4 ;
        RECT  17.064 4.992 17.256 5.016 ;
    END
  END do0[48]
  PIN do0[490]
    DIRECTION OUTPUT ;
    USE SIGNAL ;
    PORT
      LAYER M4 ;
        RECT  17.064 26.208 17.256 26.232 ;
    END
  END do0[490]
  PIN do0[491]
    DIRECTION OUTPUT ;
    USE SIGNAL ;
    PORT
      LAYER M4 ;
        RECT  17.064 26.256 17.256 26.28 ;
    END
  END do0[491]
  PIN do0[492]
    DIRECTION OUTPUT ;
    USE SIGNAL ;
    PORT
      LAYER M4 ;
        RECT  17.064 26.304 17.256 26.328 ;
    END
  END do0[492]
  PIN do0[493]
    DIRECTION OUTPUT ;
    USE SIGNAL ;
    PORT
      LAYER M4 ;
        RECT  17.064 26.352 17.256 26.376 ;
    END
  END do0[493]
  PIN do0[494]
    DIRECTION OUTPUT ;
    USE SIGNAL ;
    PORT
      LAYER M4 ;
        RECT  17.064 26.4 17.256 26.424 ;
    END
  END do0[494]
  PIN do0[495]
    DIRECTION OUTPUT ;
    USE SIGNAL ;
    PORT
      LAYER M4 ;
        RECT  17.064 26.448 17.256 26.472 ;
    END
  END do0[495]
  PIN do0[496]
    DIRECTION OUTPUT ;
    USE SIGNAL ;
    PORT
      LAYER M4 ;
        RECT  17.064 26.496 17.256 26.52 ;
    END
  END do0[496]
  PIN do0[497]
    DIRECTION OUTPUT ;
    USE SIGNAL ;
    PORT
      LAYER M4 ;
        RECT  17.064 26.544 17.256 26.568 ;
    END
  END do0[497]
  PIN do0[498]
    DIRECTION OUTPUT ;
    USE SIGNAL ;
    PORT
      LAYER M4 ;
        RECT  17.064 26.592 17.256 26.616 ;
    END
  END do0[498]
  PIN do0[499]
    DIRECTION OUTPUT ;
    USE SIGNAL ;
    PORT
      LAYER M4 ;
        RECT  17.064 26.64 17.256 26.664 ;
    END
  END do0[499]
  PIN do0[49]
    DIRECTION OUTPUT ;
    USE SIGNAL ;
    PORT
      LAYER M4 ;
        RECT  17.064 5.04 17.256 5.064 ;
    END
  END do0[49]
  PIN do0[4]
    DIRECTION OUTPUT ;
    USE SIGNAL ;
    PORT
      LAYER M4 ;
        RECT  17.064 2.88 17.256 2.904 ;
    END
  END do0[4]
  PIN do0[500]
    DIRECTION OUTPUT ;
    USE SIGNAL ;
    PORT
      LAYER M4 ;
        RECT  17.064 26.688 17.256 26.712 ;
    END
  END do0[500]
  PIN do0[501]
    DIRECTION OUTPUT ;
    USE SIGNAL ;
    PORT
      LAYER M4 ;
        RECT  17.064 26.736 17.256 26.76 ;
    END
  END do0[501]
  PIN do0[502]
    DIRECTION OUTPUT ;
    USE SIGNAL ;
    PORT
      LAYER M4 ;
        RECT  17.064 26.784 17.256 26.808 ;
    END
  END do0[502]
  PIN do0[503]
    DIRECTION OUTPUT ;
    USE SIGNAL ;
    PORT
      LAYER M4 ;
        RECT  17.064 26.832 17.256 26.856 ;
    END
  END do0[503]
  PIN do0[504]
    DIRECTION OUTPUT ;
    USE SIGNAL ;
    PORT
      LAYER M4 ;
        RECT  17.064 26.88 17.256 26.904 ;
    END
  END do0[504]
  PIN do0[505]
    DIRECTION OUTPUT ;
    USE SIGNAL ;
    PORT
      LAYER M4 ;
        RECT  17.064 26.928 17.256 26.952 ;
    END
  END do0[505]
  PIN do0[506]
    DIRECTION OUTPUT ;
    USE SIGNAL ;
    PORT
      LAYER M4 ;
        RECT  17.064 26.976 17.256 27 ;
    END
  END do0[506]
  PIN do0[507]
    DIRECTION OUTPUT ;
    USE SIGNAL ;
    PORT
      LAYER M4 ;
        RECT  17.064 27.024 17.256 27.048 ;
    END
  END do0[507]
  PIN do0[508]
    DIRECTION OUTPUT ;
    USE SIGNAL ;
    PORT
      LAYER M4 ;
        RECT  17.064 27.072 17.256 27.096 ;
    END
  END do0[508]
  PIN do0[509]
    DIRECTION OUTPUT ;
    USE SIGNAL ;
    PORT
      LAYER M4 ;
        RECT  17.064 27.12 17.256 27.144 ;
    END
  END do0[509]
  PIN do0[50]
    DIRECTION OUTPUT ;
    USE SIGNAL ;
    PORT
      LAYER M4 ;
        RECT  17.064 5.088 17.256 5.112 ;
    END
  END do0[50]
  PIN do0[510]
    DIRECTION OUTPUT ;
    USE SIGNAL ;
    PORT
      LAYER M4 ;
        RECT  17.064 27.168 17.256 27.192 ;
    END
  END do0[510]
  PIN do0[511]
    DIRECTION OUTPUT ;
    USE SIGNAL ;
    PORT
      LAYER M4 ;
        RECT  17.064 27.216 17.256 27.24 ;
    END
  END do0[511]
  PIN do0[512]
    DIRECTION OUTPUT ;
    USE SIGNAL ;
    PORT
      LAYER M4 ;
        RECT  17.064 27.264 17.256 27.288 ;
    END
  END do0[512]
  PIN do0[513]
    DIRECTION OUTPUT ;
    USE SIGNAL ;
    PORT
      LAYER M4 ;
        RECT  17.064 27.312 17.256 27.336 ;
    END
  END do0[513]
  PIN do0[514]
    DIRECTION OUTPUT ;
    USE SIGNAL ;
    PORT
      LAYER M4 ;
        RECT  17.064 27.36 17.256 27.384 ;
    END
  END do0[514]
  PIN do0[515]
    DIRECTION OUTPUT ;
    USE SIGNAL ;
    PORT
      LAYER M4 ;
        RECT  17.064 27.408 17.256 27.432 ;
    END
  END do0[515]
  PIN do0[516]
    DIRECTION OUTPUT ;
    USE SIGNAL ;
    PORT
      LAYER M4 ;
        RECT  17.064 27.456 17.256 27.48 ;
    END
  END do0[516]
  PIN do0[517]
    DIRECTION OUTPUT ;
    USE SIGNAL ;
    PORT
      LAYER M4 ;
        RECT  17.064 27.504 17.256 27.528 ;
    END
  END do0[517]
  PIN do0[518]
    DIRECTION OUTPUT ;
    USE SIGNAL ;
    PORT
      LAYER M4 ;
        RECT  17.064 27.552 17.256 27.576 ;
    END
  END do0[518]
  PIN do0[519]
    DIRECTION OUTPUT ;
    USE SIGNAL ;
    PORT
      LAYER M4 ;
        RECT  17.064 27.6 17.256 27.624 ;
    END
  END do0[519]
  PIN do0[51]
    DIRECTION OUTPUT ;
    USE SIGNAL ;
    PORT
      LAYER M4 ;
        RECT  17.064 5.136 17.256 5.16 ;
    END
  END do0[51]
  PIN do0[520]
    DIRECTION OUTPUT ;
    USE SIGNAL ;
    PORT
      LAYER M4 ;
        RECT  17.064 27.648 17.256 27.672 ;
    END
  END do0[520]
  PIN do0[521]
    DIRECTION OUTPUT ;
    USE SIGNAL ;
    PORT
      LAYER M4 ;
        RECT  17.064 27.696 17.256 27.72 ;
    END
  END do0[521]
  PIN do0[522]
    DIRECTION OUTPUT ;
    USE SIGNAL ;
    PORT
      LAYER M4 ;
        RECT  17.064 27.744 17.256 27.768 ;
    END
  END do0[522]
  PIN do0[523]
    DIRECTION OUTPUT ;
    USE SIGNAL ;
    PORT
      LAYER M4 ;
        RECT  17.064 27.792 17.256 27.816 ;
    END
  END do0[523]
  PIN do0[524]
    DIRECTION OUTPUT ;
    USE SIGNAL ;
    PORT
      LAYER M4 ;
        RECT  17.064 27.84 17.256 27.864 ;
    END
  END do0[524]
  PIN do0[525]
    DIRECTION OUTPUT ;
    USE SIGNAL ;
    PORT
      LAYER M4 ;
        RECT  17.064 27.888 17.256 27.912 ;
    END
  END do0[525]
  PIN do0[526]
    DIRECTION OUTPUT ;
    USE SIGNAL ;
    PORT
      LAYER M4 ;
        RECT  17.064 27.936 17.256 27.96 ;
    END
  END do0[526]
  PIN do0[527]
    DIRECTION OUTPUT ;
    USE SIGNAL ;
    PORT
      LAYER M4 ;
        RECT  17.064 27.984 17.256 28.008 ;
    END
  END do0[527]
  PIN do0[528]
    DIRECTION OUTPUT ;
    USE SIGNAL ;
    PORT
      LAYER M4 ;
        RECT  17.064 28.032 17.256 28.056 ;
    END
  END do0[528]
  PIN do0[529]
    DIRECTION OUTPUT ;
    USE SIGNAL ;
    PORT
      LAYER M4 ;
        RECT  17.064 28.08 17.256 28.104 ;
    END
  END do0[529]
  PIN do0[52]
    DIRECTION OUTPUT ;
    USE SIGNAL ;
    PORT
      LAYER M4 ;
        RECT  17.064 5.184 17.256 5.208 ;
    END
  END do0[52]
  PIN do0[530]
    DIRECTION OUTPUT ;
    USE SIGNAL ;
    PORT
      LAYER M4 ;
        RECT  17.064 28.128 17.256 28.152 ;
    END
  END do0[530]
  PIN do0[531]
    DIRECTION OUTPUT ;
    USE SIGNAL ;
    PORT
      LAYER M4 ;
        RECT  17.064 28.176 17.256 28.2 ;
    END
  END do0[531]
  PIN do0[532]
    DIRECTION OUTPUT ;
    USE SIGNAL ;
    PORT
      LAYER M4 ;
        RECT  17.064 28.224 17.256 28.248 ;
    END
  END do0[532]
  PIN do0[533]
    DIRECTION OUTPUT ;
    USE SIGNAL ;
    PORT
      LAYER M4 ;
        RECT  17.064 28.272 17.256 28.296 ;
    END
  END do0[533]
  PIN do0[534]
    DIRECTION OUTPUT ;
    USE SIGNAL ;
    PORT
      LAYER M4 ;
        RECT  17.064 28.32 17.256 28.344 ;
    END
  END do0[534]
  PIN do0[535]
    DIRECTION OUTPUT ;
    USE SIGNAL ;
    PORT
      LAYER M4 ;
        RECT  17.064 28.368 17.256 28.392 ;
    END
  END do0[535]
  PIN do0[536]
    DIRECTION OUTPUT ;
    USE SIGNAL ;
    PORT
      LAYER M4 ;
        RECT  17.064 28.416 17.256 28.44 ;
    END
  END do0[536]
  PIN do0[537]
    DIRECTION OUTPUT ;
    USE SIGNAL ;
    PORT
      LAYER M4 ;
        RECT  17.064 28.464 17.256 28.488 ;
    END
  END do0[537]
  PIN do0[538]
    DIRECTION OUTPUT ;
    USE SIGNAL ;
    PORT
      LAYER M4 ;
        RECT  17.064 28.512 17.256 28.536 ;
    END
  END do0[538]
  PIN do0[539]
    DIRECTION OUTPUT ;
    USE SIGNAL ;
    PORT
      LAYER M4 ;
        RECT  17.064 28.56 17.256 28.584 ;
    END
  END do0[539]
  PIN do0[53]
    DIRECTION OUTPUT ;
    USE SIGNAL ;
    PORT
      LAYER M4 ;
        RECT  17.064 5.232 17.256 5.256 ;
    END
  END do0[53]
  PIN do0[540]
    DIRECTION OUTPUT ;
    USE SIGNAL ;
    PORT
      LAYER M4 ;
        RECT  17.064 28.608 17.256 28.632 ;
    END
  END do0[540]
  PIN do0[541]
    DIRECTION OUTPUT ;
    USE SIGNAL ;
    PORT
      LAYER M4 ;
        RECT  17.064 28.656 17.256 28.68 ;
    END
  END do0[541]
  PIN do0[542]
    DIRECTION OUTPUT ;
    USE SIGNAL ;
    PORT
      LAYER M4 ;
        RECT  17.064 28.704 17.256 28.728 ;
    END
  END do0[542]
  PIN do0[543]
    DIRECTION OUTPUT ;
    USE SIGNAL ;
    PORT
      LAYER M4 ;
        RECT  17.064 28.752 17.256 28.776 ;
    END
  END do0[543]
  PIN do0[544]
    DIRECTION OUTPUT ;
    USE SIGNAL ;
    PORT
      LAYER M4 ;
        RECT  17.064 28.8 17.256 28.824 ;
    END
  END do0[544]
  PIN do0[545]
    DIRECTION OUTPUT ;
    USE SIGNAL ;
    PORT
      LAYER M4 ;
        RECT  17.064 28.848 17.256 28.872 ;
    END
  END do0[545]
  PIN do0[546]
    DIRECTION OUTPUT ;
    USE SIGNAL ;
    PORT
      LAYER M4 ;
        RECT  17.064 28.896 17.256 28.92 ;
    END
  END do0[546]
  PIN do0[547]
    DIRECTION OUTPUT ;
    USE SIGNAL ;
    PORT
      LAYER M4 ;
        RECT  17.064 28.944 17.256 28.968 ;
    END
  END do0[547]
  PIN do0[548]
    DIRECTION OUTPUT ;
    USE SIGNAL ;
    PORT
      LAYER M4 ;
        RECT  17.064 28.992 17.256 29.016 ;
    END
  END do0[548]
  PIN do0[549]
    DIRECTION OUTPUT ;
    USE SIGNAL ;
    PORT
      LAYER M4 ;
        RECT  17.064 29.04 17.256 29.064 ;
    END
  END do0[549]
  PIN do0[54]
    DIRECTION OUTPUT ;
    USE SIGNAL ;
    PORT
      LAYER M4 ;
        RECT  17.064 5.28 17.256 5.304 ;
    END
  END do0[54]
  PIN do0[550]
    DIRECTION OUTPUT ;
    USE SIGNAL ;
    PORT
      LAYER M4 ;
        RECT  17.064 29.088 17.256 29.112 ;
    END
  END do0[550]
  PIN do0[551]
    DIRECTION OUTPUT ;
    USE SIGNAL ;
    PORT
      LAYER M4 ;
        RECT  17.064 29.136 17.256 29.16 ;
    END
  END do0[551]
  PIN do0[552]
    DIRECTION OUTPUT ;
    USE SIGNAL ;
    PORT
      LAYER M4 ;
        RECT  17.064 29.184 17.256 29.208 ;
    END
  END do0[552]
  PIN do0[553]
    DIRECTION OUTPUT ;
    USE SIGNAL ;
    PORT
      LAYER M4 ;
        RECT  17.064 29.232 17.256 29.256 ;
    END
  END do0[553]
  PIN do0[554]
    DIRECTION OUTPUT ;
    USE SIGNAL ;
    PORT
      LAYER M4 ;
        RECT  17.064 29.28 17.256 29.304 ;
    END
  END do0[554]
  PIN do0[555]
    DIRECTION OUTPUT ;
    USE SIGNAL ;
    PORT
      LAYER M4 ;
        RECT  17.064 29.328 17.256 29.352 ;
    END
  END do0[555]
  PIN do0[556]
    DIRECTION OUTPUT ;
    USE SIGNAL ;
    PORT
      LAYER M4 ;
        RECT  17.064 29.376 17.256 29.4 ;
    END
  END do0[556]
  PIN do0[557]
    DIRECTION OUTPUT ;
    USE SIGNAL ;
    PORT
      LAYER M4 ;
        RECT  17.064 29.424 17.256 29.448 ;
    END
  END do0[557]
  PIN do0[558]
    DIRECTION OUTPUT ;
    USE SIGNAL ;
    PORT
      LAYER M4 ;
        RECT  17.064 29.472 17.256 29.496 ;
    END
  END do0[558]
  PIN do0[559]
    DIRECTION OUTPUT ;
    USE SIGNAL ;
    PORT
      LAYER M4 ;
        RECT  17.064 29.52 17.256 29.544 ;
    END
  END do0[559]
  PIN do0[55]
    DIRECTION OUTPUT ;
    USE SIGNAL ;
    PORT
      LAYER M4 ;
        RECT  17.064 5.328 17.256 5.352 ;
    END
  END do0[55]
  PIN do0[560]
    DIRECTION OUTPUT ;
    USE SIGNAL ;
    PORT
      LAYER M4 ;
        RECT  17.064 29.568 17.256 29.592 ;
    END
  END do0[560]
  PIN do0[561]
    DIRECTION OUTPUT ;
    USE SIGNAL ;
    PORT
      LAYER M4 ;
        RECT  17.064 29.616 17.256 29.64 ;
    END
  END do0[561]
  PIN do0[562]
    DIRECTION OUTPUT ;
    USE SIGNAL ;
    PORT
      LAYER M4 ;
        RECT  17.064 29.664 17.256 29.688 ;
    END
  END do0[562]
  PIN do0[563]
    DIRECTION OUTPUT ;
    USE SIGNAL ;
    PORT
      LAYER M4 ;
        RECT  17.064 29.712 17.256 29.736 ;
    END
  END do0[563]
  PIN do0[564]
    DIRECTION OUTPUT ;
    USE SIGNAL ;
    PORT
      LAYER M4 ;
        RECT  17.064 29.76 17.256 29.784 ;
    END
  END do0[564]
  PIN do0[565]
    DIRECTION OUTPUT ;
    USE SIGNAL ;
    PORT
      LAYER M4 ;
        RECT  17.064 29.808 17.256 29.832 ;
    END
  END do0[565]
  PIN do0[56]
    DIRECTION OUTPUT ;
    USE SIGNAL ;
    PORT
      LAYER M4 ;
        RECT  17.064 5.376 17.256 5.4 ;
    END
  END do0[56]
  PIN do0[57]
    DIRECTION OUTPUT ;
    USE SIGNAL ;
    PORT
      LAYER M4 ;
        RECT  17.064 5.424 17.256 5.448 ;
    END
  END do0[57]
  PIN do0[58]
    DIRECTION OUTPUT ;
    USE SIGNAL ;
    PORT
      LAYER M4 ;
        RECT  17.064 5.472 17.256 5.496 ;
    END
  END do0[58]
  PIN do0[59]
    DIRECTION OUTPUT ;
    USE SIGNAL ;
    PORT
      LAYER M4 ;
        RECT  17.064 5.52 17.256 5.544 ;
    END
  END do0[59]
  PIN do0[5]
    DIRECTION OUTPUT ;
    USE SIGNAL ;
    PORT
      LAYER M4 ;
        RECT  17.064 2.928 17.256 2.952 ;
    END
  END do0[5]
  PIN do0[60]
    DIRECTION OUTPUT ;
    USE SIGNAL ;
    PORT
      LAYER M4 ;
        RECT  17.064 5.568 17.256 5.592 ;
    END
  END do0[60]
  PIN do0[61]
    DIRECTION OUTPUT ;
    USE SIGNAL ;
    PORT
      LAYER M4 ;
        RECT  17.064 5.616 17.256 5.64 ;
    END
  END do0[61]
  PIN do0[62]
    DIRECTION OUTPUT ;
    USE SIGNAL ;
    PORT
      LAYER M4 ;
        RECT  17.064 5.664 17.256 5.688 ;
    END
  END do0[62]
  PIN do0[63]
    DIRECTION OUTPUT ;
    USE SIGNAL ;
    PORT
      LAYER M4 ;
        RECT  17.064 5.712 17.256 5.736 ;
    END
  END do0[63]
  PIN do0[64]
    DIRECTION OUTPUT ;
    USE SIGNAL ;
    PORT
      LAYER M4 ;
        RECT  17.064 5.76 17.256 5.784 ;
    END
  END do0[64]
  PIN do0[65]
    DIRECTION OUTPUT ;
    USE SIGNAL ;
    PORT
      LAYER M4 ;
        RECT  17.064 5.808 17.256 5.832 ;
    END
  END do0[65]
  PIN do0[66]
    DIRECTION OUTPUT ;
    USE SIGNAL ;
    PORT
      LAYER M4 ;
        RECT  17.064 5.856 17.256 5.88 ;
    END
  END do0[66]
  PIN do0[67]
    DIRECTION OUTPUT ;
    USE SIGNAL ;
    PORT
      LAYER M4 ;
        RECT  17.064 5.904 17.256 5.928 ;
    END
  END do0[67]
  PIN do0[68]
    DIRECTION OUTPUT ;
    USE SIGNAL ;
    PORT
      LAYER M4 ;
        RECT  17.064 5.952 17.256 5.976 ;
    END
  END do0[68]
  PIN do0[69]
    DIRECTION OUTPUT ;
    USE SIGNAL ;
    PORT
      LAYER M4 ;
        RECT  17.064 6 17.256 6.024 ;
    END
  END do0[69]
  PIN do0[6]
    DIRECTION OUTPUT ;
    USE SIGNAL ;
    PORT
      LAYER M4 ;
        RECT  17.064 2.976 17.256 3 ;
    END
  END do0[6]
  PIN do0[70]
    DIRECTION OUTPUT ;
    USE SIGNAL ;
    PORT
      LAYER M4 ;
        RECT  17.064 6.048 17.256 6.072 ;
    END
  END do0[70]
  PIN do0[71]
    DIRECTION OUTPUT ;
    USE SIGNAL ;
    PORT
      LAYER M4 ;
        RECT  17.064 6.096 17.256 6.12 ;
    END
  END do0[71]
  PIN do0[72]
    DIRECTION OUTPUT ;
    USE SIGNAL ;
    PORT
      LAYER M4 ;
        RECT  17.064 6.144 17.256 6.168 ;
    END
  END do0[72]
  PIN do0[73]
    DIRECTION OUTPUT ;
    USE SIGNAL ;
    PORT
      LAYER M4 ;
        RECT  17.064 6.192 17.256 6.216 ;
    END
  END do0[73]
  PIN do0[74]
    DIRECTION OUTPUT ;
    USE SIGNAL ;
    PORT
      LAYER M4 ;
        RECT  17.064 6.24 17.256 6.264 ;
    END
  END do0[74]
  PIN do0[75]
    DIRECTION OUTPUT ;
    USE SIGNAL ;
    PORT
      LAYER M4 ;
        RECT  17.064 6.288 17.256 6.312 ;
    END
  END do0[75]
  PIN do0[76]
    DIRECTION OUTPUT ;
    USE SIGNAL ;
    PORT
      LAYER M4 ;
        RECT  17.064 6.336 17.256 6.36 ;
    END
  END do0[76]
  PIN do0[77]
    DIRECTION OUTPUT ;
    USE SIGNAL ;
    PORT
      LAYER M4 ;
        RECT  17.064 6.384 17.256 6.408 ;
    END
  END do0[77]
  PIN do0[78]
    DIRECTION OUTPUT ;
    USE SIGNAL ;
    PORT
      LAYER M4 ;
        RECT  17.064 6.432 17.256 6.456 ;
    END
  END do0[78]
  PIN do0[79]
    DIRECTION OUTPUT ;
    USE SIGNAL ;
    PORT
      LAYER M4 ;
        RECT  17.064 6.48 17.256 6.504 ;
    END
  END do0[79]
  PIN do0[7]
    DIRECTION OUTPUT ;
    USE SIGNAL ;
    PORT
      LAYER M4 ;
        RECT  17.064 3.024 17.256 3.048 ;
    END
  END do0[7]
  PIN do0[80]
    DIRECTION OUTPUT ;
    USE SIGNAL ;
    PORT
      LAYER M4 ;
        RECT  17.064 6.528 17.256 6.552 ;
    END
  END do0[80]
  PIN do0[81]
    DIRECTION OUTPUT ;
    USE SIGNAL ;
    PORT
      LAYER M4 ;
        RECT  17.064 6.576 17.256 6.6 ;
    END
  END do0[81]
  PIN do0[82]
    DIRECTION OUTPUT ;
    USE SIGNAL ;
    PORT
      LAYER M4 ;
        RECT  17.064 6.624 17.256 6.648 ;
    END
  END do0[82]
  PIN do0[83]
    DIRECTION OUTPUT ;
    USE SIGNAL ;
    PORT
      LAYER M4 ;
        RECT  17.064 6.672 17.256 6.696 ;
    END
  END do0[83]
  PIN do0[84]
    DIRECTION OUTPUT ;
    USE SIGNAL ;
    PORT
      LAYER M4 ;
        RECT  17.064 6.72 17.256 6.744 ;
    END
  END do0[84]
  PIN do0[85]
    DIRECTION OUTPUT ;
    USE SIGNAL ;
    PORT
      LAYER M4 ;
        RECT  17.064 6.768 17.256 6.792 ;
    END
  END do0[85]
  PIN do0[86]
    DIRECTION OUTPUT ;
    USE SIGNAL ;
    PORT
      LAYER M4 ;
        RECT  17.064 6.816 17.256 6.84 ;
    END
  END do0[86]
  PIN do0[87]
    DIRECTION OUTPUT ;
    USE SIGNAL ;
    PORT
      LAYER M4 ;
        RECT  17.064 6.864 17.256 6.888 ;
    END
  END do0[87]
  PIN do0[88]
    DIRECTION OUTPUT ;
    USE SIGNAL ;
    PORT
      LAYER M4 ;
        RECT  17.064 6.912 17.256 6.936 ;
    END
  END do0[88]
  PIN do0[89]
    DIRECTION OUTPUT ;
    USE SIGNAL ;
    PORT
      LAYER M4 ;
        RECT  17.064 6.96 17.256 6.984 ;
    END
  END do0[89]
  PIN do0[8]
    DIRECTION OUTPUT ;
    USE SIGNAL ;
    PORT
      LAYER M4 ;
        RECT  17.064 3.072 17.256 3.096 ;
    END
  END do0[8]
  PIN do0[90]
    DIRECTION OUTPUT ;
    USE SIGNAL ;
    PORT
      LAYER M4 ;
        RECT  17.064 7.008 17.256 7.032 ;
    END
  END do0[90]
  PIN do0[91]
    DIRECTION OUTPUT ;
    USE SIGNAL ;
    PORT
      LAYER M4 ;
        RECT  17.064 7.056 17.256 7.08 ;
    END
  END do0[91]
  PIN do0[92]
    DIRECTION OUTPUT ;
    USE SIGNAL ;
    PORT
      LAYER M4 ;
        RECT  17.064 7.104 17.256 7.128 ;
    END
  END do0[92]
  PIN do0[93]
    DIRECTION OUTPUT ;
    USE SIGNAL ;
    PORT
      LAYER M4 ;
        RECT  17.064 7.152 17.256 7.176 ;
    END
  END do0[93]
  PIN do0[94]
    DIRECTION OUTPUT ;
    USE SIGNAL ;
    PORT
      LAYER M4 ;
        RECT  17.064 7.2 17.256 7.224 ;
    END
  END do0[94]
  PIN do0[95]
    DIRECTION OUTPUT ;
    USE SIGNAL ;
    PORT
      LAYER M4 ;
        RECT  17.064 7.248 17.256 7.272 ;
    END
  END do0[95]
  PIN do0[96]
    DIRECTION OUTPUT ;
    USE SIGNAL ;
    PORT
      LAYER M4 ;
        RECT  17.064 7.296 17.256 7.32 ;
    END
  END do0[96]
  PIN do0[97]
    DIRECTION OUTPUT ;
    USE SIGNAL ;
    PORT
      LAYER M4 ;
        RECT  17.064 7.344 17.256 7.368 ;
    END
  END do0[97]
  PIN do0[98]
    DIRECTION OUTPUT ;
    USE SIGNAL ;
    PORT
      LAYER M4 ;
        RECT  17.064 7.392 17.256 7.416 ;
    END
  END do0[98]
  PIN do0[99]
    DIRECTION OUTPUT ;
    USE SIGNAL ;
    PORT
      LAYER M4 ;
        RECT  17.064 7.44 17.256 7.464 ;
    END
  END do0[99]
  PIN do0[9]
    DIRECTION OUTPUT ;
    USE SIGNAL ;
    PORT
      LAYER M4 ;
        RECT  17.064 3.12 17.256 3.144 ;
    END
  END do0[9]
  PIN fi0[0]
    DIRECTION INPUT ;
    USE SIGNAL ;
    PORT
      LAYER M4 ;
        RECT  0 2.496 0.192 2.52 ;
    END
  END fi0[0]
  PIN fo0[0]
    DIRECTION OUTPUT ;
    USE SIGNAL ;
    PORT
      LAYER M4 ;
        RECT  17.064 2.496 17.256 2.52 ;
    END
  END fo0[0]
  PIN VDD
    DIRECTION INOUT ;
    USE POWER ;
    PORT
      LAYER M7 ;
        RECT  6.256 0.531 6.544 31.599 ;
      LAYER M6 ;
        RECT  0 28.572 0.032 28.86 ;
        RECT  0 23.172 0.032 23.46 ;
        RECT  0 17.772 0.032 18.06 ;
        RECT  0 12.372 0.032 12.66 ;
        RECT  0 6.972 0.032 7.26 ;
        RECT  0 1.572 0.032 1.86 ;
      LAYER M2 ;
        RECT  0 31.581 0.018 31.599 ;
        RECT  0 31.041 0.018 31.059 ;
        RECT  0 30.501 0.018 30.519 ;
        RECT  0 29.961 0.018 29.979 ;
        RECT  0 29.421 0.018 29.439 ;
        RECT  0 28.881 0.018 28.899 ;
        RECT  0 28.341 0.018 28.359 ;
        RECT  0 27.801 0.018 27.819 ;
        RECT  0 27.261 0.018 27.279 ;
        RECT  0 26.721 0.018 26.739 ;
        RECT  0 26.181 0.018 26.199 ;
        RECT  0 25.641 0.018 25.659 ;
        RECT  0 25.101 0.018 25.119 ;
        RECT  0 24.561 0.018 24.579 ;
        RECT  0 24.021 0.018 24.039 ;
        RECT  0 23.481 0.018 23.499 ;
        RECT  0 22.941 0.018 22.959 ;
        RECT  0 22.401 0.018 22.419 ;
        RECT  0 21.861 0.018 21.879 ;
        RECT  0 21.321 0.018 21.339 ;
        RECT  0 20.781 0.018 20.799 ;
        RECT  0 20.241 0.018 20.259 ;
        RECT  0 19.701 0.018 19.719 ;
        RECT  0 19.161 0.018 19.179 ;
        RECT  0 18.621 0.018 18.639 ;
        RECT  0 18.081 0.018 18.099 ;
        RECT  0 17.541 0.018 17.559 ;
        RECT  0 17.001 0.018 17.019 ;
        RECT  0 16.461 0.018 16.479 ;
        RECT  0 15.921 0.018 15.939 ;
        RECT  0 15.381 0.018 15.399 ;
        RECT  0 14.841 0.018 14.859 ;
        RECT  0 14.301 0.018 14.319 ;
        RECT  0 13.761 0.018 13.779 ;
        RECT  0 13.221 0.018 13.239 ;
        RECT  0 12.681 0.018 12.699 ;
        RECT  0 12.141 0.018 12.159 ;
        RECT  0 11.601 0.018 11.619 ;
        RECT  0 11.061 0.018 11.079 ;
        RECT  0 10.521 0.018 10.539 ;
        RECT  0 9.981 0.018 9.999 ;
        RECT  0 9.441 0.018 9.459 ;
        RECT  0 8.901 0.018 8.919 ;
        RECT  0 8.361 0.018 8.379 ;
        RECT  0 7.821 0.018 7.839 ;
        RECT  0 7.281 0.018 7.299 ;
        RECT  0 6.741 0.018 6.759 ;
        RECT  0 6.201 0.018 6.219 ;
        RECT  0 5.661 0.018 5.679 ;
        RECT  0 5.121 0.018 5.139 ;
        RECT  0 4.581 0.018 4.599 ;
        RECT  0 4.041 0.018 4.059 ;
        RECT  0 3.501 0.018 3.519 ;
        RECT  0 2.961 0.018 2.979 ;
        RECT  0 2.421 0.018 2.439 ;
        RECT  0 1.881 0.018 1.899 ;
        RECT  0 1.341 0.018 1.359 ;
        RECT  0 0.801 0.018 0.819 ;
      LAYER M1 ;
        RECT  0 31.581 0.018 31.599 ;
        RECT  0 31.041 0.018 31.059 ;
        RECT  0 30.501 0.018 30.519 ;
        RECT  0 29.961 0.018 29.979 ;
        RECT  0 29.421 0.018 29.439 ;
        RECT  0 28.881 0.018 28.899 ;
        RECT  0 28.341 0.018 28.359 ;
        RECT  0 27.801 0.018 27.819 ;
        RECT  0 27.261 0.018 27.279 ;
        RECT  0 26.721 0.018 26.739 ;
        RECT  0 26.181 0.018 26.199 ;
        RECT  0 25.641 0.018 25.659 ;
        RECT  0 25.101 0.018 25.119 ;
        RECT  0 24.561 0.018 24.579 ;
        RECT  0 24.021 0.018 24.039 ;
        RECT  0 23.481 0.018 23.499 ;
        RECT  0 22.941 0.018 22.959 ;
        RECT  0 22.401 0.018 22.419 ;
        RECT  0 21.861 0.018 21.879 ;
        RECT  0 21.321 0.018 21.339 ;
        RECT  0 20.781 0.018 20.799 ;
        RECT  0 20.241 0.018 20.259 ;
        RECT  0 19.701 0.018 19.719 ;
        RECT  0 19.161 0.018 19.179 ;
        RECT  0 18.621 0.018 18.639 ;
        RECT  0 18.081 0.018 18.099 ;
        RECT  0 17.541 0.018 17.559 ;
        RECT  0 17.001 0.018 17.019 ;
        RECT  0 16.461 0.018 16.479 ;
        RECT  0 15.921 0.018 15.939 ;
        RECT  0 15.381 0.018 15.399 ;
        RECT  0 14.841 0.018 14.859 ;
        RECT  0 14.301 0.018 14.319 ;
        RECT  0 13.761 0.018 13.779 ;
        RECT  0 13.221 0.018 13.239 ;
        RECT  0 12.681 0.018 12.699 ;
        RECT  0 12.141 0.018 12.159 ;
        RECT  0 11.601 0.018 11.619 ;
        RECT  0 11.061 0.018 11.079 ;
        RECT  0 10.521 0.018 10.539 ;
        RECT  0 9.981 0.018 9.999 ;
        RECT  0 9.441 0.018 9.459 ;
        RECT  0 8.901 0.018 8.919 ;
        RECT  0 8.361 0.018 8.379 ;
        RECT  0 7.821 0.018 7.839 ;
        RECT  0 7.281 0.018 7.299 ;
        RECT  0 6.741 0.018 6.759 ;
        RECT  0 6.201 0.018 6.219 ;
        RECT  0 5.661 0.018 5.679 ;
        RECT  0 5.121 0.018 5.139 ;
        RECT  0 4.581 0.018 4.599 ;
        RECT  0 4.041 0.018 4.059 ;
        RECT  0 3.501 0.018 3.519 ;
        RECT  0 2.961 0.018 2.979 ;
        RECT  0 2.421 0.018 2.439 ;
        RECT  0 1.881 0.018 1.899 ;
        RECT  0 1.341 0.018 1.359 ;
        RECT  0 0.801 0.018 0.819 ;
    END
  END VDD
  PIN VSS
    DIRECTION INOUT ;
    USE GROUND ;
    PORT
      LAYER M7 ;
        RECT  11.656 0.531 11.944 31.599 ;
        RECT  0.856 0.531 1.144 31.599 ;
      LAYER M6 ;
        RECT  0 27.996 0.032 28.284 ;
        RECT  0 22.596 0.032 22.884 ;
        RECT  0 17.196 0.032 17.484 ;
        RECT  0 11.796 0.032 12.084 ;
        RECT  0 6.396 0.032 6.684 ;
        RECT  0 0.996 0.032 1.284 ;
      LAYER M2 ;
        RECT  0 31.311 0.018 31.329 ;
        RECT  0 30.771 0.018 30.789 ;
        RECT  0 30.231 0.018 30.249 ;
        RECT  0 29.691 0.018 29.709 ;
        RECT  0 29.151 0.018 29.169 ;
        RECT  0 28.611 0.018 28.629 ;
        RECT  0 28.071 0.018 28.089 ;
        RECT  0 27.531 0.018 27.549 ;
        RECT  0 26.991 0.018 27.009 ;
        RECT  0 26.451 0.018 26.469 ;
        RECT  0 25.911 0.018 25.929 ;
        RECT  0 25.371 0.018 25.389 ;
        RECT  0 24.831 0.018 24.849 ;
        RECT  0 24.291 0.018 24.309 ;
        RECT  0 23.751 0.018 23.769 ;
        RECT  0 23.211 0.018 23.229 ;
        RECT  0 22.671 0.018 22.689 ;
        RECT  0 22.131 0.018 22.149 ;
        RECT  0 21.591 0.018 21.609 ;
        RECT  0 21.051 0.018 21.069 ;
        RECT  0 20.511 0.018 20.529 ;
        RECT  0 19.971 0.018 19.989 ;
        RECT  0 19.431 0.018 19.449 ;
        RECT  0 18.891 0.018 18.909 ;
        RECT  0 18.351 0.018 18.369 ;
        RECT  0 17.811 0.018 17.829 ;
        RECT  0 17.271 0.018 17.289 ;
        RECT  0 16.731 0.018 16.749 ;
        RECT  0 16.191 0.018 16.209 ;
        RECT  0 15.651 0.018 15.669 ;
        RECT  0 15.111 0.018 15.129 ;
        RECT  0 14.571 0.018 14.589 ;
        RECT  0 14.031 0.018 14.049 ;
        RECT  0 13.491 0.018 13.509 ;
        RECT  0 12.951 0.018 12.969 ;
        RECT  0 12.411 0.018 12.429 ;
        RECT  0 11.871 0.018 11.889 ;
        RECT  0 11.331 0.018 11.349 ;
        RECT  0 10.791 0.018 10.809 ;
        RECT  0 10.251 0.018 10.269 ;
        RECT  0 9.711 0.018 9.729 ;
        RECT  0 9.171 0.018 9.189 ;
        RECT  0 8.631 0.018 8.649 ;
        RECT  0 8.091 0.018 8.109 ;
        RECT  0 7.551 0.018 7.569 ;
        RECT  0 7.011 0.018 7.029 ;
        RECT  0 6.471 0.018 6.489 ;
        RECT  0 5.931 0.018 5.949 ;
        RECT  0 5.391 0.018 5.409 ;
        RECT  0 4.851 0.018 4.869 ;
        RECT  0 4.311 0.018 4.329 ;
        RECT  0 3.771 0.018 3.789 ;
        RECT  0 3.231 0.018 3.249 ;
        RECT  0 2.691 0.018 2.709 ;
        RECT  0 2.151 0.018 2.169 ;
        RECT  0 1.611 0.018 1.629 ;
        RECT  0 1.071 0.018 1.089 ;
        RECT  0 0.531 0.018 0.549 ;
      LAYER M1 ;
        RECT  0 31.311 0.018 31.329 ;
        RECT  0 30.771 0.018 30.789 ;
        RECT  0 30.231 0.018 30.249 ;
        RECT  0 29.691 0.018 29.709 ;
        RECT  0 29.151 0.018 29.169 ;
        RECT  0 28.611 0.018 28.629 ;
        RECT  0 28.071 0.018 28.089 ;
        RECT  0 27.531 0.018 27.549 ;
        RECT  0 26.991 0.018 27.009 ;
        RECT  0 26.451 0.018 26.469 ;
        RECT  0 25.911 0.018 25.929 ;
        RECT  0 25.371 0.018 25.389 ;
        RECT  0 24.831 0.018 24.849 ;
        RECT  0 24.291 0.018 24.309 ;
        RECT  0 23.751 0.018 23.769 ;
        RECT  0 23.211 0.018 23.229 ;
        RECT  0 22.671 0.018 22.689 ;
        RECT  0 22.131 0.018 22.149 ;
        RECT  0 21.591 0.018 21.609 ;
        RECT  0 21.051 0.018 21.069 ;
        RECT  0 20.511 0.018 20.529 ;
        RECT  0 19.971 0.018 19.989 ;
        RECT  0 19.431 0.018 19.449 ;
        RECT  0 18.891 0.018 18.909 ;
        RECT  0 18.351 0.018 18.369 ;
        RECT  0 17.811 0.018 17.829 ;
        RECT  0 17.271 0.018 17.289 ;
        RECT  0 16.731 0.018 16.749 ;
        RECT  0 16.191 0.018 16.209 ;
        RECT  0 15.651 0.018 15.669 ;
        RECT  0 15.111 0.018 15.129 ;
        RECT  0 14.571 0.018 14.589 ;
        RECT  0 14.031 0.018 14.049 ;
        RECT  0 13.491 0.018 13.509 ;
        RECT  0 12.951 0.018 12.969 ;
        RECT  0 12.411 0.018 12.429 ;
        RECT  0 11.871 0.018 11.889 ;
        RECT  0 11.331 0.018 11.349 ;
        RECT  0 10.791 0.018 10.809 ;
        RECT  0 10.251 0.018 10.269 ;
        RECT  0 9.711 0.018 9.729 ;
        RECT  0 9.171 0.018 9.189 ;
        RECT  0 8.631 0.018 8.649 ;
        RECT  0 8.091 0.018 8.109 ;
        RECT  0 7.551 0.018 7.569 ;
        RECT  0 7.011 0.018 7.029 ;
        RECT  0 6.471 0.018 6.489 ;
        RECT  0 5.931 0.018 5.949 ;
        RECT  0 5.391 0.018 5.409 ;
        RECT  0 4.851 0.018 4.869 ;
        RECT  0 4.311 0.018 4.329 ;
        RECT  0 3.771 0.018 3.789 ;
        RECT  0 3.231 0.018 3.249 ;
        RECT  0 2.691 0.018 2.709 ;
        RECT  0 2.151 0.018 2.169 ;
        RECT  0 1.611 0.018 1.629 ;
        RECT  0 1.071 0.018 1.089 ;
        RECT  0 0.531 0.018 0.549 ;
    END
  END VSS
  OBS
    LAYER RVTN ;
     RECT  0 0.54 17.226 0.675 ;
     RECT  0 0.945 17.226 1.215 ;
     RECT  0 1.485 17.226 1.755 ;
     RECT  0 2.025 17.226 2.295 ;
     RECT  0 2.565 17.226 2.835 ;
     RECT  0 3.105 17.226 3.375 ;
     RECT  0 3.645 17.226 3.915 ;
     RECT  0 4.185 17.226 4.455 ;
     RECT  0 4.725 17.226 4.995 ;
     RECT  0 5.265 17.226 5.535 ;
     RECT  0 5.805 17.226 6.075 ;
     RECT  0 6.345 17.226 6.615 ;
     RECT  0 6.885 17.226 7.155 ;
     RECT  0 7.425 17.226 7.695 ;
     RECT  0 7.965 17.226 8.235 ;
     RECT  0 8.505 17.226 8.775 ;
     RECT  0 9.045 17.226 9.315 ;
     RECT  0 9.585 17.226 9.855 ;
     RECT  0 10.125 17.226 10.395 ;
     RECT  0 10.665 17.226 10.935 ;
     RECT  0 11.205 17.226 11.475 ;
     RECT  0 11.745 17.226 12.015 ;
     RECT  0 12.285 17.226 12.555 ;
     RECT  0 12.825 17.226 13.095 ;
     RECT  0 13.365 17.226 13.635 ;
     RECT  0 13.905 17.226 14.175 ;
     RECT  0 14.445 17.226 14.715 ;
     RECT  0 14.985 17.226 15.255 ;
     RECT  0 15.525 17.226 15.795 ;
     RECT  0 16.065 17.226 16.335 ;
     RECT  0 16.605 17.226 16.875 ;
     RECT  0 17.145 17.226 17.415 ;
     RECT  0 17.685 17.226 17.955 ;
     RECT  0 18.225 17.226 18.495 ;
     RECT  0 18.765 17.226 19.035 ;
     RECT  0 19.305 17.226 19.575 ;
     RECT  0 19.845 17.226 20.115 ;
     RECT  0 20.385 17.226 20.655 ;
     RECT  0 20.925 17.226 21.195 ;
     RECT  0 21.465 17.226 21.735 ;
     RECT  0 22.005 17.226 22.275 ;
     RECT  0 22.545 17.226 22.815 ;
     RECT  0 23.085 17.226 23.355 ;
     RECT  0 23.625 17.226 23.895 ;
     RECT  0 24.165 17.226 24.435 ;
     RECT  0 24.705 17.226 24.975 ;
     RECT  0 25.245 17.226 25.515 ;
     RECT  0 25.785 17.226 26.055 ;
     RECT  0 26.325 17.226 26.595 ;
     RECT  0 26.865 17.226 27.135 ;
     RECT  0 27.405 17.226 27.675 ;
     RECT  0 27.945 17.226 28.215 ;
     RECT  0 28.485 17.226 28.755 ;
     RECT  0 29.025 17.226 29.295 ;
     RECT  0 29.565 17.226 29.835 ;
     RECT  0 30.105 17.226 30.375 ;
     RECT  0 30.645 17.226 30.915 ;
     RECT  0 31.185 17.226 31.455 ;
    LAYER RVTP ;
     RECT  0 0.675 17.226 0.945 ;
     RECT  0 1.215 17.226 1.485 ;
     RECT  0 1.755 17.226 2.025 ;
     RECT  0 2.295 17.226 2.565 ;
     RECT  0 2.835 17.226 3.105 ;
     RECT  0 3.375 17.226 3.645 ;
     RECT  0 3.915 17.226 4.185 ;
     RECT  0 4.455 17.226 4.725 ;
     RECT  0 4.995 17.226 5.265 ;
     RECT  0 5.535 17.226 5.805 ;
     RECT  0 6.075 17.226 6.345 ;
     RECT  0 6.615 17.226 6.885 ;
     RECT  0 7.155 17.226 7.425 ;
     RECT  0 7.695 17.226 7.965 ;
     RECT  0 8.235 17.226 8.505 ;
     RECT  0 8.775 17.226 9.045 ;
     RECT  0 9.315 17.226 9.585 ;
     RECT  0 9.855 17.226 10.125 ;
     RECT  0 10.395 17.226 10.665 ;
     RECT  0 10.935 17.226 11.205 ;
     RECT  0 11.475 17.226 11.745 ;
     RECT  0 12.015 17.226 12.285 ;
     RECT  0 12.555 17.226 12.825 ;
     RECT  0 13.095 17.226 13.365 ;
     RECT  0 13.635 17.226 13.905 ;
     RECT  0 14.175 17.226 14.445 ;
     RECT  0 14.715 17.226 14.985 ;
     RECT  0 15.255 17.226 15.525 ;
     RECT  0 15.795 17.226 16.065 ;
     RECT  0 16.335 17.226 16.605 ;
     RECT  0 16.875 17.226 17.145 ;
     RECT  0 17.415 17.226 17.685 ;
     RECT  0 17.955 17.226 18.225 ;
     RECT  0 18.495 17.226 18.765 ;
     RECT  0 19.035 17.226 19.305 ;
     RECT  0 19.575 17.226 19.845 ;
     RECT  0 20.115 17.226 20.385 ;
     RECT  0 20.655 17.226 20.925 ;
     RECT  0 21.195 17.226 21.465 ;
     RECT  0 21.735 17.226 22.005 ;
     RECT  0 22.275 17.226 22.545 ;
     RECT  0 22.815 17.226 23.085 ;
     RECT  0 23.355 17.226 23.625 ;
     RECT  0 23.895 17.226 24.165 ;
     RECT  0 24.435 17.226 24.705 ;
     RECT  0 24.975 17.226 25.245 ;
     RECT  0 25.515 17.226 25.785 ;
     RECT  0 26.055 17.226 26.325 ;
     RECT  0 26.595 17.226 26.865 ;
     RECT  0 27.135 17.226 27.405 ;
     RECT  0 27.675 17.226 27.945 ;
     RECT  0 28.215 17.226 28.485 ;
     RECT  0 28.755 17.226 29.025 ;
     RECT  0 29.295 17.226 29.565 ;
     RECT  0 29.835 17.226 30.105 ;
     RECT  0 30.375 17.226 30.645 ;
     RECT  0 30.915 17.226 31.185 ;
     RECT  0 31.455 17.226 31.59 ;
    LAYER M1 ;
     RECT  0 0.531 17.226 31.599 ;
    LAYER M2 ;
     RECT  0 0.531 17.226 31.599 ;
    LAYER M3 ;
     RECT  0.255 0.523 0.345 0.793 ;
     RECT  5.655 0.523 5.745 0.793 ;
     RECT  11.055 0.523 11.145 0.793 ;
     RECT  16.455 0.523 16.545 0.793 ;
     RECT  0.255 0.793 0.537 1.111 ;
     RECT  0.108 1.111 0.537 1.147 ;
     RECT  0.036 1.147 0.537 1.561 ;
     RECT  1.692 1.381 1.71 1.561 ;
     RECT  11.055 0.793 11.337 1.687 ;
     RECT  16.455 0.793 16.737 1.921 ;
     RECT  14.724 1.561 14.742 1.993 ;
     RECT  2.448 1.993 2.466 2.029 ;
     RECT  16.416 1.921 16.737 2.029 ;
     RECT  5.655 0.793 5.937 2.065 ;
     RECT  14.724 1.993 15.39 2.065 ;
     RECT  8.172 1.831 8.19 2.101 ;
     RECT  14.724 2.065 15.426 2.101 ;
     RECT  16.344 2.029 16.737 2.101 ;
     RECT  14.724 2.101 16.866 2.191 ;
     RECT  6.768 2.191 6.786 2.227 ;
     RECT  11.055 1.687 11.934 2.227 ;
     RECT  5.256 2.065 5.937 2.299 ;
     RECT  6.768 2.227 6.966 2.299 ;
     RECT  10.08 1.921 10.098 2.299 ;
     RECT  11.055 2.227 11.97 2.299 ;
     RECT  4.104 2.227 4.122 2.347 ;
     RECT  5.256 2.299 6.966 2.347 ;
     RECT  7.884 2.101 8.19 2.347 ;
     RECT  4.104 2.347 4.194 2.371 ;
     RECT  5.256 2.347 8.19 2.371 ;
     RECT  11.016 2.299 12.33 2.371 ;
     RECT  13.428 2.335 13.446 2.371 ;
     RECT  0.036 1.561 1.71 2.443 ;
     RECT  2.448 2.029 2.862 2.443 ;
     RECT  10.008 2.299 10.098 2.461 ;
     RECT  11.016 2.371 13.446 2.461 ;
     RECT  14.724 2.191 16.974 2.461 ;
     RECT  4.104 2.371 4.266 2.491 ;
     RECT  9.828 2.461 13.446 2.497 ;
     RECT  14.724 2.461 17.046 2.525 ;
     RECT  14.724 2.525 16.974 2.533 ;
     RECT  3.672 2.491 4.266 2.569 ;
     RECT  5.184 2.371 8.19 2.605 ;
     RECT  9.828 2.497 13.518 2.605 ;
     RECT  3.636 2.569 4.266 2.725 ;
     RECT  5.184 2.605 13.518 2.725 ;
     RECT  3.636 2.725 13.518 2.767 ;
     RECT  14.544 2.533 16.974 2.767 ;
     RECT  0.036 2.443 2.862 2.869 ;
     RECT  3.636 2.767 16.974 2.869 ;
     RECT  0.036 2.869 16.974 3.137 ;
     RECT  0.036 3.137 4.554 3.443 ;
     RECT  5.364 3.137 16.974 3.811 ;
     RECT  5.364 3.811 17.046 3.947 ;
     RECT  1.872 3.443 4.554 4.117 ;
     RECT  5.364 3.947 16.974 4.117 ;
     RECT  1.872 4.117 16.974 4.205 ;
     RECT  0.036 3.443 1.026 4.261 ;
     RECT  1.872 4.205 2.97 4.261 ;
     RECT  3.888 4.205 16.974 4.699 ;
     RECT  3.888 4.699 17.046 4.919 ;
     RECT  0.036 4.261 2.97 4.927 ;
     RECT  3.888 4.919 14.994 4.927 ;
     RECT  0.036 4.927 14.994 4.928 ;
     RECT  15.804 4.919 17.046 4.955 ;
     RECT  0.036 4.928 14.958 5.189 ;
     RECT  9.756 5.189 14.958 5.773 ;
     RECT  15.84 4.955 17.046 5.773 ;
     RECT  2.232 5.189 9.018 5.971 ;
     RECT  9.756 5.773 17.046 5.971 ;
     RECT  2.232 5.971 17.046 5.981 ;
     RECT  0.036 5.189 1.494 5.995 ;
     RECT  2.232 5.981 7.866 5.995 ;
     RECT  8.604 5.981 17.046 6.305 ;
     RECT  0.036 5.995 7.866 6.859 ;
     RECT  8.604 6.305 17.01 6.859 ;
     RECT  0.036 6.859 17.01 7.187 ;
     RECT  0.036 7.187 16.974 7.949 ;
     RECT  2.268 7.949 16.974 8.195 ;
     RECT  2.268 8.195 3.978 8.237 ;
     RECT  4.896 8.195 16.974 8.491 ;
     RECT  4.896 8.491 17.046 8.581 ;
     RECT  0.036 7.949 1.494 8.707 ;
     RECT  2.268 8.237 3.834 8.707 ;
     RECT  0.036 8.707 3.834 9.013 ;
     RECT  0.036 9.013 3.942 9.085 ;
     RECT  4.896 8.581 17.082 9.085 ;
     RECT  0.036 9.085 17.082 9.113 ;
     RECT  0.036 9.113 17.01 9.869 ;
     RECT  0.036 9.869 13.23 9.959 ;
     RECT  14.004 9.869 17.01 9.959 ;
     RECT  15.588 9.959 17.01 10.123 ;
     RECT  15.588 10.123 17.046 10.229 ;
     RECT  9.036 9.959 13.23 10.696 ;
     RECT  14.004 9.959 14.85 10.696 ;
     RECT  15.588 10.229 16.974 10.696 ;
     RECT  9.036 10.696 13.266 10.705 ;
     RECT  14.004 10.696 16.974 10.705 ;
     RECT  0.036 9.959 8.154 10.741 ;
     RECT  9.036 10.705 16.974 10.741 ;
     RECT  0.036 10.741 16.974 11.069 ;
     RECT  0.036 11.069 16.938 11.435 ;
     RECT  3.924 11.435 16.938 11.669 ;
     RECT  9.54 11.669 16.938 11.939 ;
     RECT  12.312 11.939 16.938 11.947 ;
     RECT  12.312 11.947 16.974 12.077 ;
     RECT  12.312 12.077 14.094 12.209 ;
     RECT  0.036 11.435 3.15 12.253 ;
     RECT  3.924 11.669 8.73 12.253 ;
     RECT  0.036 12.253 8.73 12.475 ;
     RECT  14.832 12.077 16.974 12.523 ;
     RECT  12.312 12.209 13.95 12.587 ;
     RECT  0.036 12.475 8.91 12.715 ;
     RECT  9.648 11.939 11.538 12.715 ;
     RECT  0.036 12.715 11.538 12.721 ;
     RECT  12.312 12.587 13.878 12.721 ;
     RECT  14.832 12.523 17.046 12.797 ;
     RECT  14.832 12.797 16.974 12.941 ;
     RECT  14.832 12.941 16.938 13.027 ;
     RECT  0.036 12.721 13.878 13.289 ;
     RECT  13.284 13.289 13.878 13.441 ;
     RECT  14.652 13.027 16.938 13.441 ;
     RECT  0.036 13.289 12.474 13.667 ;
     RECT  13.284 13.441 16.938 13.711 ;
     RECT  13.284 13.711 17.01 13.829 ;
     RECT  9.36 13.667 12.474 14.059 ;
     RECT  13.284 13.829 16.974 14.059 ;
     RECT  0.036 13.667 8.622 14.099 ;
     RECT  7.92 14.099 8.622 14.485 ;
     RECT  9.36 14.059 16.974 14.485 ;
     RECT  0.036 14.099 7.182 14.819 ;
     RECT  1.476 14.819 7.182 14.827 ;
     RECT  7.92 14.485 16.974 14.827 ;
     RECT  1.476 14.827 16.974 14.945 ;
     RECT  10.584 14.945 16.974 15.025 ;
     RECT  10.584 15.025 17.046 15.089 ;
     RECT  1.476 14.945 9.774 15.101 ;
     RECT  10.728 15.089 17.046 15.215 ;
     RECT  14.256 15.215 17.046 15.293 ;
     RECT  10.728 15.215 13.41 15.359 ;
     RECT  1.476 15.101 9.738 15.581 ;
     RECT  0.036 14.819 0.702 15.601 ;
     RECT  10.872 15.359 13.41 15.961 ;
     RECT  14.256 15.293 16.974 15.961 ;
     RECT  1.584 15.581 9.738 16.069 ;
     RECT  1.584 16.069 10.098 16.105 ;
     RECT  10.872 15.961 16.974 16.105 ;
     RECT  0.036 15.601 0.846 16.315 ;
     RECT  1.584 16.105 16.974 16.315 ;
     RECT  0.036 16.315 16.974 17.069 ;
     RECT  12.492 17.069 16.974 17.491 ;
     RECT  0.036 17.069 11.754 17.851 ;
     RECT  12.492 17.491 17.046 17.851 ;
     RECT  0.036 17.851 17.046 18.257 ;
     RECT  0.036 18.257 12.294 18.293 ;
     RECT  2.196 18.293 12.294 18.464 ;
     RECT  13.176 18.257 17.046 18.599 ;
     RECT  13.176 18.599 16.974 18.689 ;
     RECT  2.196 18.464 12.006 18.833 ;
     RECT  13.5 18.689 16.974 18.959 ;
     RECT  0.036 18.293 1.386 19.192 ;
     RECT  2.196 18.833 8.226 19.192 ;
     RECT  9 18.833 12.006 19.237 ;
     RECT  12.744 19.111 12.762 19.237 ;
     RECT  9 19.237 12.762 19.507 ;
     RECT  9 19.507 13.086 19.607 ;
     RECT  9 19.607 9.594 19.615 ;
     RECT  0.036 19.192 8.226 19.651 ;
     RECT  8.964 19.615 9.594 19.651 ;
     RECT  10.44 19.607 13.086 19.768 ;
     RECT  13.932 18.959 16.974 19.768 ;
     RECT  0.036 19.651 9.594 19.877 ;
     RECT  0.036 19.877 9.522 19.913 ;
     RECT  10.44 19.768 16.974 20.039 ;
     RECT  10.44 20.039 13.986 20.219 ;
     RECT  14.832 20.039 16.974 20.395 ;
     RECT  10.44 20.219 13.95 20.551 ;
     RECT  10.368 20.551 13.95 20.683 ;
     RECT  0.036 19.913 9.45 20.731 ;
     RECT  10.332 20.683 13.95 20.731 ;
     RECT  0.036 20.731 13.95 20.971 ;
     RECT  14.832 20.395 17.046 20.971 ;
     RECT  0.036 20.971 17.046 21.485 ;
     RECT  14.004 21.485 17.046 21.497 ;
     RECT  14.004 21.497 16.974 22.199 ;
     RECT  14.004 22.199 14.058 22.235 ;
     RECT  0.036 21.485 13.086 22.279 ;
     RECT  0.036 22.279 13.194 22.459 ;
     RECT  0.036 22.459 13.266 22.505 ;
     RECT  1.62 22.505 13.266 22.621 ;
     RECT  14.004 22.235 14.022 22.621 ;
     RECT  14.94 22.199 15.102 22.939 ;
     RECT  15.84 22.199 16.974 22.939 ;
     RECT  14.94 22.939 16.974 23.017 ;
     RECT  1.62 22.621 14.022 23.089 ;
     RECT  14.904 23.017 16.974 23.089 ;
     RECT  1.62 23.089 16.974 23.189 ;
     RECT  0.036 22.505 0.774 23.287 ;
     RECT  1.62 23.189 11.718 23.287 ;
     RECT  0.036 23.287 11.718 23.357 ;
     RECT  2.124 23.357 11.718 23.549 ;
     RECT  2.124 23.549 11.682 23.585 ;
     RECT  9.432 23.585 11.682 23.729 ;
     RECT  12.492 23.189 16.974 23.971 ;
     RECT  0.036 23.357 1.062 24.187 ;
     RECT  0.036 24.187 1.314 24.205 ;
     RECT  2.124 23.585 8.55 24.205 ;
     RECT  0.036 24.205 8.55 24.233 ;
     RECT  0.036 24.233 8.082 24.359 ;
     RECT  9.468 23.729 11.682 24.475 ;
     RECT  8.964 24.475 11.682 24.539 ;
     RECT  9.144 24.539 11.682 24.701 ;
     RECT  10.8 24.701 11.682 24.781 ;
     RECT  12.42 23.971 16.974 24.781 ;
     RECT  9.144 24.701 10.026 24.809 ;
     RECT  10.8 24.781 16.974 24.907 ;
     RECT  10.8 24.907 17.046 24.941 ;
     RECT  10.908 24.941 17.046 24.971 ;
     RECT  5.292 24.359 8.082 25.141 ;
     RECT  0.036 24.359 4.554 25.213 ;
     RECT  5.292 25.141 8.154 25.213 ;
     RECT  10.908 24.971 16.974 25.439 ;
     RECT  0.036 25.213 8.154 25.447 ;
     RECT  9.144 24.809 9.99 25.447 ;
     RECT  13.428 25.439 16.974 25.469 ;
     RECT  0.036 25.447 9.99 25.675 ;
     RECT  10.908 25.439 12.618 25.675 ;
     RECT  0.036 25.675 12.618 25.949 ;
     RECT  0.036 25.949 4.626 26.015 ;
     RECT  5.364 25.949 12.618 26.123 ;
     RECT  10.98 26.123 12.618 26.365 ;
     RECT  13.5 25.469 16.974 26.365 ;
     RECT  0.036 26.015 3.078 26.761 ;
     RECT  3.852 26.015 4.626 26.761 ;
     RECT  0.036 26.761 4.626 26.833 ;
     RECT  5.364 26.123 10.242 26.833 ;
     RECT  0.036 26.833 10.242 26.869 ;
     RECT  10.98 26.365 16.974 26.869 ;
     RECT  0.036 26.869 16.974 27.751 ;
     RECT  0.036 27.751 17.01 27.835 ;
     RECT  0.036 27.835 17.046 28.139 ;
     RECT  0.036 28.139 17.01 28.409 ;
     RECT  0.036 28.409 16.974 29.057 ;
     RECT  0.036 29.057 14.994 29.291 ;
     RECT  14.436 29.291 14.994 29.363 ;
     RECT  0.036 29.291 13.59 29.399 ;
     RECT  15.804 29.057 16.974 29.497 ;
     RECT  3.996 29.399 13.59 29.525 ;
     RECT  8.748 29.525 13.59 29.597 ;
     RECT  8.784 29.597 13.482 29.633 ;
     RECT  14.652 29.363 14.994 29.84 ;
     RECT  3.996 29.525 7.902 29.903 ;
     RECT  0.036 29.399 2.934 29.933 ;
     RECT  0.108 29.933 2.934 29.939 ;
     RECT  8.784 29.633 13.374 29.939 ;
     RECT  14.724 29.84 14.994 30.029 ;
     RECT  0.108 29.939 2.826 30.065 ;
     RECT  3.996 29.903 4.086 30.065 ;
     RECT  8.784 29.939 12.834 30.065 ;
     RECT  14.76 30.029 14.994 30.077 ;
     RECT  15.804 29.497 17.01 30.091 ;
     RECT  8.784 30.065 11.394 30.101 ;
     RECT  12.204 30.065 12.834 30.101 ;
     RECT  0.255 30.065 2.826 30.137 ;
     RECT  3.996 30.065 4.014 30.137 ;
     RECT  12.204 30.101 12.222 30.137 ;
     RECT  5.004 29.903 7.902 30.173 ;
     RECT  8.784 30.101 9.126 30.173 ;
     RECT  10.224 30.101 11.394 30.173 ;
     RECT  14.76 30.077 14.778 30.173 ;
     RECT  10.8 30.173 11.394 30.209 ;
     RECT  15.588 30.091 17.01 30.209 ;
     RECT  0.255 30.137 2.25 30.299 ;
     RECT  5.004 30.173 7.362 30.299 ;
     RECT  9.108 30.173 9.126 30.299 ;
     RECT  5.004 30.299 7.11 30.365 ;
     RECT  5.655 30.365 7.11 30.479 ;
     RECT  15.84 30.209 17.01 30.479 ;
     RECT  0.255 30.299 1.494 30.569 ;
     RECT  2.232 30.299 2.25 30.569 ;
     RECT  5.655 30.479 6.246 30.569 ;
     RECT  7.02 30.479 7.11 30.569 ;
     RECT  15.84 30.479 16.737 30.605 ;
     RECT  10.8 30.209 11.337 30.713 ;
     RECT  0.255 30.569 1.314 31.109 ;
     RECT  1.26 31.109 1.278 31.253 ;
     RECT  0.255 31.109 0.537 31.337 ;
     RECT  5.655 30.569 5.937 31.337 ;
     RECT  11.055 30.713 11.337 31.337 ;
     RECT  16.455 30.605 16.737 31.337 ;
     RECT  0.447 31.337 0.537 31.607 ;
     RECT  5.847 31.337 5.937 31.607 ;
     RECT  11.247 31.337 11.337 31.607 ;
     RECT  16.647 31.337 16.737 31.607 ;
    LAYER M4 ;
     RECT  0.025 2.304 0.133 29.928 ;
     RECT  0.133 2.304 0.248 30.072 ;
     RECT  0.248 0.528 0.352 31.332 ;
     RECT  0.352 0.798 0.44 31.332 ;
     RECT  0.44 0.798 0.544 31.602 ;
     RECT  0.544 2.064 1.505 30.264 ;
     RECT  1.505 2.448 2.297 29.88 ;
     RECT  2.297 2.592 2.797 29.88 ;
     RECT  2.797 2.592 3.661 30.12 ;
     RECT  3.661 2.496 4.165 30.12 ;
     RECT  4.165 2.352 4.993 30.12 ;
     RECT  4.993 2.352 5.648 30.36 ;
     RECT  5.648 0.528 5.752 31.332 ;
     RECT  5.752 0.798 5.84 31.332 ;
     RECT  5.84 0.798 5.944 31.602 ;
     RECT  5.944 2.592 6.257 30.36 ;
     RECT  6.257 2.592 7.049 30.216 ;
     RECT  7.049 2.592 7.333 30.12 ;
     RECT  7.333 2.352 7.985 30.12 ;
     RECT  7.985 2.592 9.997 30.12 ;
     RECT  9.997 2.304 11.048 30.12 ;
     RECT  11.048 0.528 11.152 31.332 ;
     RECT  11.152 0.798 11.24 31.332 ;
     RECT  11.24 0.798 11.344 31.602 ;
     RECT  11.344 2.304 11.981 30.12 ;
     RECT  11.981 2.544 12.449 30.12 ;
     RECT  12.449 2.592 16.448 30.12 ;
     RECT  16.448 0.528 16.552 31.332 ;
     RECT  16.552 0.798 16.64 31.332 ;
     RECT  16.64 0.798 16.744 31.602 ;
     RECT  16.744 2.496 16.979 30.072 ;
     RECT  16.979 2.496 17.1 29.832 ;
    LAYER M5 ;
     RECT  0.24 0.517 0.36 0.787 ;
     RECT  5.64 0.517 5.76 0.787 ;
     RECT  11.04 0.517 11.16 0.787 ;
     RECT  16.44 0.517 16.56 0.787 ;
     RECT  11.04 0.787 11.352 2.293 ;
     RECT  0.24 0.787 0.552 2.389 ;
     RECT  16.44 0.787 16.752 2.965 ;
     RECT  16.32 2.965 16.752 2.975 ;
     RECT  0.096 2.389 0.552 3.179 ;
     RECT  0.144 3.179 0.552 3.253 ;
     RECT  16.32 2.975 16.968 3.411 ;
     RECT  11.04 2.293 11.88 3.443 ;
     RECT  15.984 3.411 16.968 3.499 ;
     RECT  0.144 3.253 0.648 3.701 ;
     RECT  0.144 3.701 0.984 3.923 ;
     RECT  9.072 3.925 9.096 4.117 ;
     RECT  9.072 4.117 9.72 4.203 ;
     RECT  4.464 3.445 4.488 4.331 ;
     RECT  0.144 3.923 0.792 4.405 ;
     RECT  16.32 3.499 16.968 4.533 ;
     RECT  16.32 4.533 17.064 4.587 ;
     RECT  9.072 4.203 9.096 4.691 ;
     RECT  16.44 4.587 17.064 5.075 ;
     RECT  2.688 4.261 2.712 5.123 ;
     RECT  0.096 4.405 0.792 5.125 ;
     RECT  11.04 3.443 11.352 5.221 ;
     RECT  0.096 5.125 1.224 5.291 ;
     RECT  11.04 5.221 11.928 5.317 ;
     RECT  13.104 4.405 13.128 5.317 ;
     RECT  3.408 5.125 3.528 5.355 ;
     RECT  0.144 5.291 1.224 5.365 ;
     RECT  11.04 5.317 13.128 5.365 ;
     RECT  10.608 5.365 13.128 5.411 ;
     RECT  10.608 5.411 12.504 5.419 ;
     RECT  3.408 5.355 3.432 5.449 ;
     RECT  10.608 5.419 11.976 5.507 ;
     RECT  5.64 0.787 5.952 5.701 ;
     RECT  5.64 5.701 6.072 5.845 ;
     RECT  8.544 5.845 8.856 5.931 ;
     RECT  15.408 5.989 15.432 6.073 ;
     RECT  0.144 5.365 2.28 6.187 ;
     RECT  16.44 5.075 16.752 6.197 ;
     RECT  4.512 6.191 4.536 6.275 ;
     RECT  9.6 6.767 9.624 6.851 ;
     RECT  8.544 5.931 8.568 6.899 ;
     RECT  11.04 5.507 11.976 6.899 ;
     RECT  16.44 6.197 16.872 7.237 ;
     RECT  5.64 5.845 6.36 7.333 ;
     RECT  16.32 7.237 16.872 7.416 ;
     RECT  5.64 7.333 6.888 7.417 ;
     RECT  9.888 7.285 9.912 7.427 ;
     RECT  16.32 7.416 16.92 7.531 ;
     RECT  16.32 7.531 16.872 7.571 ;
     RECT  0.144 6.187 1.512 7.619 ;
     RECT  13.104 7.669 13.128 7.753 ;
     RECT  11.04 6.899 11.448 7.811 ;
     RECT  1.68 7.765 1.704 7.861 ;
     RECT  1.68 7.861 2.376 7.979 ;
     RECT  0.144 7.619 0.648 8.003 ;
     RECT  14.352 6.805 14.376 8.003 ;
     RECT  1.968 7.979 2.376 8.099 ;
     RECT  2.064 8.099 2.376 8.483 ;
     RECT  2.208 8.483 2.376 8.581 ;
     RECT  5.64 7.417 5.952 8.595 ;
     RECT  5.52 8.595 5.952 8.629 ;
     RECT  2.208 8.581 2.808 8.683 ;
     RECT  5.52 8.629 6.072 8.683 ;
     RECT  0.144 8.003 0.552 8.713 ;
     RECT  5.64 8.683 6.072 8.713 ;
     RECT  2.208 8.683 2.28 8.771 ;
     RECT  16.44 7.571 16.872 8.773 ;
     RECT  16.44 8.773 16.92 9.011 ;
     RECT  9.744 8.869 9.768 9.195 ;
     RECT  2.256 8.771 2.28 9.203 ;
     RECT  0.24 8.713 0.552 9.301 ;
     RECT  0.24 9.301 0.648 9.717 ;
     RECT  2.832 9.685 2.856 9.771 ;
     RECT  16.44 9.011 16.872 10.003 ;
     RECT  16.32 10.003 16.872 10.037 ;
     RECT  0.144 9.717 0.648 10.229 ;
     RECT  14.304 10.195 14.328 10.283 ;
     RECT  7.44 10.293 7.464 10.381 ;
     RECT  0.144 10.229 0.696 10.403 ;
     RECT  14.496 10.501 14.52 10.603 ;
     RECT  16.32 10.037 16.968 10.655 ;
     RECT  16.32 10.655 17.064 10.739 ;
     RECT  5.64 8.713 5.952 10.805 ;
     RECT  0.144 10.403 0.648 10.825 ;
     RECT  5.52 10.805 6.312 10.893 ;
     RECT  2.928 10.885 3.336 11.231 ;
     RECT  16.32 10.739 16.872 11.253 ;
     RECT  2.832 11.231 3.336 11.267 ;
     RECT  2.832 11.267 2.856 11.315 ;
     RECT  7.296 10.741 7.32 11.411 ;
     RECT  15.984 11.253 16.872 11.459 ;
     RECT  14.928 11.413 14.952 11.499 ;
     RECT  5.64 10.893 6.312 11.509 ;
     RECT  9.696 11.605 9.72 11.691 ;
     RECT  5.64 11.509 6.888 11.699 ;
     RECT  13.104 11.077 13.128 12.083 ;
     RECT  16.32 11.459 16.872 12.083 ;
     RECT  0.144 10.825 0.552 12.213 ;
     RECT  1.824 11.077 1.848 12.213 ;
     RECT  16.44 12.083 16.872 12.275 ;
     RECT  5.64 11.699 5.952 12.517 ;
     RECT  0.144 12.213 1.848 12.719 ;
     RECT  0.144 12.719 2.04 12.803 ;
     RECT  0.144 12.803 1.464 12.971 ;
     RECT  0.144 12.971 0.792 13.005 ;
     RECT  12.48 13.109 12.504 13.235 ;
     RECT  14.688 13.429 14.712 13.523 ;
     RECT  11.04 7.811 11.352 13.535 ;
     RECT  5.136 12.517 5.952 13.571 ;
     RECT  10.848 13.535 11.352 13.619 ;
     RECT  11.04 13.619 11.352 13.621 ;
     RECT  11.04 13.621 11.448 13.705 ;
     RECT  1.968 13.813 1.992 13.861 ;
     RECT  1.968 13.861 2.136 13.957 ;
     RECT  0.24 13.005 0.792 14.005 ;
     RECT  0.144 14.005 0.792 14.059 ;
     RECT  16.44 12.275 16.752 14.163 ;
     RECT  16.176 14.163 16.752 14.197 ;
     RECT  1.968 13.957 2.232 14.243 ;
     RECT  2.256 14.533 3 14.675 ;
     RECT  11.04 13.705 11.352 14.773 ;
     RECT  16.176 14.197 16.92 14.917 ;
     RECT  16.176 14.917 16.968 15.019 ;
     RECT  16.176 15.019 16.752 15.061 ;
     RECT  0.144 14.059 0.648 15.107 ;
     RECT  13.104 14.917 13.128 15.107 ;
     RECT  0.144 15.107 0.552 15.117 ;
     RECT  15.504 15.061 16.752 15.251 ;
     RECT  5.64 13.571 5.952 15.379 ;
     RECT  8.016 14.533 8.04 15.443 ;
     RECT  10.944 14.773 11.352 15.443 ;
     RECT  5.52 15.379 5.952 15.477 ;
     RECT  2.256 14.675 2.904 15.685 ;
     RECT  5.52 15.477 6.888 15.685 ;
     RECT  5.52 15.685 7.56 15.731 ;
     RECT  2.016 15.685 2.904 15.787 ;
     RECT  5.52 15.731 5.952 15.787 ;
     RECT  9.696 15.733 9.72 15.817 ;
     RECT  2.016 15.787 2.04 15.827 ;
     RECT  7.536 15.731 7.56 15.979 ;
     RECT  16.44 15.251 16.752 16.069 ;
     RECT  0.24 15.117 0.552 16.213 ;
     RECT  12.528 16.223 12.552 16.307 ;
     RECT  0.144 16.213 0.552 16.693 ;
     RECT  11.04 15.443 11.352 16.693 ;
     RECT  3.264 16.645 3.288 16.789 ;
     RECT  8.88 16.645 8.904 16.835 ;
     RECT  10.944 16.693 11.352 16.835 ;
     RECT  5.64 15.787 5.952 16.933 ;
     RECT  0.144 16.693 0.648 16.949 ;
     RECT  16.44 16.069 16.872 17.047 ;
     RECT  2.688 16.789 3.288 17.077 ;
     RECT  13.104 16.693 13.128 17.123 ;
     RECT  14.832 16.949 14.856 17.131 ;
     RECT  16.44 17.047 16.968 17.161 ;
     RECT  0.144 16.949 0.744 17.267 ;
     RECT  0.24 17.267 0.744 17.363 ;
     RECT  2.688 17.077 3.432 17.411 ;
     RECT  14.256 17.317 14.28 17.555 ;
     RECT  2.688 17.411 2.712 17.603 ;
     RECT  5.136 16.933 5.952 17.699 ;
     RECT  16.44 17.161 16.872 17.699 ;
     RECT  11.04 16.835 11.352 18.277 ;
     RECT  0.24 17.363 0.552 18.335 ;
     RECT  0.24 18.335 0.648 18.357 ;
     RECT  16.44 17.699 16.752 18.643 ;
     RECT  16.32 18.643 16.752 18.661 ;
     RECT  16.32 18.661 16.872 18.671 ;
     RECT  3.504 18.565 3.528 18.709 ;
     RECT  16.32 18.671 16.968 18.731 ;
     RECT  3.504 18.709 3.672 18.755 ;
     RECT  16.44 18.731 16.968 18.755 ;
     RECT  3.648 18.755 3.672 18.795 ;
     RECT  16.44 18.755 16.872 18.803 ;
     RECT  11.04 18.277 11.928 18.851 ;
     RECT  2.256 19.347 2.28 19.435 ;
     RECT  0.144 18.357 0.648 19.475 ;
     RECT  14.832 19.525 14.856 19.667 ;
     RECT  11.04 18.851 11.352 19.701 ;
     RECT  0.24 19.475 0.648 19.754 ;
     RECT  10.944 19.701 11.352 19.811 ;
     RECT  13.68 19.765 13.704 19.849 ;
     RECT  0.24 19.754 0.696 20.051 ;
     RECT  16.44 18.803 16.752 20.197 ;
     RECT  0.24 20.051 0.552 20.499 ;
     RECT  12.768 20.437 12.792 20.523 ;
     RECT  11.04 19.811 11.352 20.533 ;
     RECT  11.04 20.533 11.448 20.627 ;
     RECT  0.144 20.499 0.552 21.023 ;
     RECT  2.256 21.109 2.28 21.251 ;
     RECT  13.488 21.237 13.512 21.301 ;
     RECT  13.488 21.301 14.184 21.325 ;
     RECT  16.44 20.197 16.872 21.397 ;
     RECT  16.44 21.397 16.968 21.429 ;
     RECT  16.176 21.429 16.968 21.483 ;
     RECT  5.64 17.699 5.952 21.493 ;
     RECT  7.056 21.109 7.08 21.493 ;
     RECT  16.176 21.483 16.872 21.517 ;
     RECT  2.88 21.349 2.904 21.539 ;
     RECT  16.32 21.517 16.872 21.645 ;
     RECT  9.696 21.557 9.72 21.683 ;
     RECT  0.144 21.023 0.648 21.685 ;
     RECT  5.64 21.493 7.08 21.779 ;
     RECT  7.296 21.877 7.32 22.059 ;
     RECT  0.144 21.685 1.08 22.309 ;
     RECT  0.144 22.309 1.416 22.507 ;
     RECT  14.16 21.325 14.184 22.691 ;
     RECT  2.256 22.693 2.28 22.883 ;
     RECT  16.44 21.645 16.872 22.933 ;
     RECT  16.32 22.933 16.872 22.965 ;
     RECT  16.32 22.965 16.968 23.019 ;
     RECT  8.784 22.069 8.808 23.123 ;
     RECT  16.44 23.019 16.968 23.123 ;
     RECT  0.144 22.507 0.648 23.723 ;
     RECT  0.144 23.723 0.552 23.757 ;
     RECT  16.44 23.123 16.872 24.085 ;
     RECT  5.64 21.779 5.952 24.277 ;
     RECT  9.504 23.925 9.528 24.363 ;
     RECT  16.44 24.085 16.968 24.613 ;
     RECT  15.696 24.613 16.968 24.671 ;
     RECT  0.24 23.757 0.552 24.709 ;
     RECT  15.696 24.671 17.064 24.755 ;
     RECT  11.04 20.627 11.352 24.757 ;
     RECT  0.24 24.709 0.648 24.805 ;
     RECT  11.04 24.757 12.024 24.851 ;
     RECT  5.64 24.277 6.168 24.947 ;
     RECT  15.696 24.755 16.872 24.995 ;
     RECT  13.68 25.055 13.704 25.139 ;
     RECT  16.44 24.995 16.872 25.235 ;
     RECT  4.464 24.757 4.488 25.381 ;
     RECT  5.64 24.947 6.072 25.381 ;
     RECT  0.144 24.805 0.696 25.492 ;
     RECT  4.464 25.381 6.072 25.523 ;
     RECT  14.88 25.237 14.904 25.523 ;
     RECT  11.04 24.851 11.352 25.525 ;
     RECT  5.52 25.523 6.072 25.667 ;
     RECT  10.272 25.525 11.352 25.715 ;
     RECT  0.144 25.492 0.648 25.963 ;
     RECT  2.4 25.909 2.424 26.051 ;
     RECT  16.44 25.235 16.752 26.197 ;
     RECT  1.872 26.053 1.896 26.339 ;
     RECT  10.848 25.715 11.352 26.579 ;
     RECT  5.52 25.667 5.952 26.684 ;
     RECT  0.24 25.963 0.648 26.997 ;
     RECT  16.44 26.197 16.872 27.251 ;
     RECT  14.256 26.197 14.28 27.443 ;
     RECT  14.832 27.541 14.856 27.779 ;
     RECT  0.144 26.997 0.648 27.826 ;
     RECT  5.52 26.684 6.312 27.883 ;
     RECT  0.144 27.826 0.696 27.971 ;
     RECT  5.52 27.883 5.952 28.019 ;
     RECT  0.144 27.971 0.552 28.067 ;
     RECT  11.04 26.579 11.352 28.309 ;
     RECT  3.024 27.829 3.048 28.355 ;
     RECT  11.04 28.309 12.024 28.405 ;
     RECT  10.56 28.405 12.024 28.489 ;
     RECT  0.24 28.067 0.552 29.029 ;
     RECT  0.24 29.029 0.648 29.109 ;
     RECT  0.144 29.109 0.648 29.163 ;
     RECT  11.04 28.489 12.024 29.171 ;
     RECT  16.44 27.251 16.752 29.797 ;
     RECT  0.144 29.163 0.552 30.083 ;
     RECT  16.44 29.797 16.968 30.083 ;
     RECT  0.24 30.083 0.552 31.343 ;
     RECT  5.64 28.019 5.952 31.343 ;
     RECT  11.04 29.171 11.352 31.343 ;
     RECT  16.44 30.083 16.752 31.343 ;
     RECT  0.432 31.343 0.552 31.613 ;
     RECT  5.832 31.343 5.952 31.613 ;
     RECT  11.232 31.343 11.352 31.613 ;
     RECT  16.632 31.343 16.752 31.613 ;
    LAYER M6 ;
     RECT  0 0.996 0.053 1.86 ;
     RECT  0 6.396 0.053 7.26 ;
     RECT  0.053 0.996 0.131 7.26 ;
     RECT  0.131 3.264 0.133 7.26 ;
     RECT  0 11.796 0.133 12.66 ;
     RECT  0.053 15.744 0.133 15.776 ;
     RECT  0 17.196 0.133 18.06 ;
     RECT  0 22.596 0.133 23.46 ;
     RECT  0 27.996 0.133 28.86 ;
     RECT  0.133 3.264 0.659 29.152 ;
     RECT  0.659 5.824 0.707 10.272 ;
     RECT  0.659 27.84 0.707 28.86 ;
     RECT  0.659 11.648 0.803 14.048 ;
     RECT  0.659 3.712 0.995 4.448 ;
     RECT  0.995 4.16 2.149 4.448 ;
     RECT  0.707 5.824 2.149 9.76 ;
     RECT  0.659 15.744 2.245 18.06 ;
     RECT  0.659 19.392 2.291 23.46 ;
     RECT  0.803 11.648 2.773 13.664 ;
     RECT  2.245 15.168 2.773 18.06 ;
     RECT  2.149 4.16 2.819 9.76 ;
     RECT  2.773 11.648 2.821 18.06 ;
     RECT  2.821 11.264 2.859 18.06 ;
     RECT  2.819 9.152 2.867 9.76 ;
     RECT  0.707 27.996 3.013 28.86 ;
     RECT  2.859 15.168 3.637 18.06 ;
     RECT  2.291 19.712 3.637 23.46 ;
     RECT  3.637 15.168 3.706 23.46 ;
     RECT  2.819 4.16 5.509 7.712 ;
     RECT  2.867 9.152 5.509 9.184 ;
     RECT  2.859 11.264 5.509 13.664 ;
     RECT  5.509 4.16 6.083 9.184 ;
     RECT  0.659 24.768 6.277 26.4 ;
     RECT  3.013 27.84 6.277 28.86 ;
     RECT  3.706 19.712 6.645 23.46 ;
     RECT  6.277 24.768 6.645 28.86 ;
     RECT  6.645 19.712 6.699 28.86 ;
     RECT  6.083 9.152 6.837 9.184 ;
     RECT  5.509 10.816 6.837 13.664 ;
     RECT  6.837 9.152 7.475 13.664 ;
     RECT  6.083 4.16 9.731 7.712 ;
     RECT  6.699 19.712 9.731 26.4 ;
     RECT  7.475 9.152 10.229 9.184 ;
     RECT  10.229 9.152 10.283 9.76 ;
     RECT  9.731 22.596 10.603 26.4 ;
     RECT  10.603 24.768 10.883 26.4 ;
     RECT  9.731 19.712 10.979 21.28 ;
     RECT  9.731 4.416 11.413 7.712 ;
     RECT  7.475 11.264 11.459 13.664 ;
     RECT  10.979 19.776 11.459 21.28 ;
     RECT  11.413 4.416 11.563 7.776 ;
     RECT  10.883 24.768 12.035 25.12 ;
     RECT  10.283 9.728 12.469 9.76 ;
     RECT  11.459 11.264 12.469 13.152 ;
     RECT  11.563 4.416 12.523 7.712 ;
     RECT  12.469 9.728 12.523 13.152 ;
     RECT  12.523 10.24 12.538 13.152 ;
     RECT  3.706 15.168 12.563 18.06 ;
     RECT  11.459 19.776 12.757 19.808 ;
     RECT  11.459 21.248 12.757 21.28 ;
     RECT  12.757 19.776 12.843 21.28 ;
     RECT  12.523 4.416 13.139 4.448 ;
     RECT  12.523 6.016 13.139 7.712 ;
     RECT  12.843 21.248 13.523 21.28 ;
     RECT  12.843 19.776 13.715 19.808 ;
     RECT  12.035 25.088 13.715 25.12 ;
     RECT  12.538 10.24 14.339 12.66 ;
     RECT  14.339 10.56 14.677 12.66 ;
     RECT  14.677 10.56 14.763 13.472 ;
     RECT  12.563 16.96 14.867 18.06 ;
     RECT  13.139 6.016 15.443 7.26 ;
     RECT  12.563 15.168 16.019 15.2 ;
     RECT  10.603 22.596 16.165 23.46 ;
     RECT  0.131 0.996 16.309 1.86 ;
     RECT  15.973 3.456 16.309 3.488 ;
     RECT  15.443 6.208 16.309 7.26 ;
     RECT  14.763 11.264 16.309 12.66 ;
     RECT  14.867 17.088 16.309 18.06 ;
     RECT  16.165 21.44 16.309 23.46 ;
     RECT  16.309 0.996 16.56 4.576 ;
     RECT  16.309 21.44 16.56 24.736 ;
     RECT  6.699 27.996 16.56 28.86 ;
     RECT  16.56 1.572 16.752 4.576 ;
     RECT  16.309 10.048 16.752 12.66 ;
     RECT  16.309 17.088 16.752 18.72 ;
     RECT  16.56 28.572 16.752 28.86 ;
     RECT  16.309 6.208 16.883 7.52 ;
     RECT  16.752 10.048 16.883 11.68 ;
     RECT  16.56 21.44 16.883 21.6 ;
     RECT  16.883 7.488 16.931 7.52 ;
     RECT  16.165 14.208 16.931 15.008 ;
     RECT  16.752 3.008 16.979 4.576 ;
     RECT  16.883 10.048 16.979 10.72 ;
     RECT  16.931 14.976 16.979 15.008 ;
     RECT  16.752 17.088 16.979 17.12 ;
     RECT  16.752 18.688 16.979 18.72 ;
     RECT  16.883 21.44 16.979 21.472 ;
     RECT  16.56 22.976 16.979 24.736 ;
     RECT  16.979 4.544 17.075 4.576 ;
     RECT  16.979 10.688 17.075 10.72 ;
     RECT  16.979 24.704 17.075 24.736 ;
    LAYER M7 ;
     RECT  0.856 0.531 1.144 3.125 ;
     RECT  11.656 0.531 11.944 5.365 ;
     RECT  11.656 5.365 12.512 6.773 ;
     RECT  6.256 0.531 6.544 7.349 ;
     RECT  11.52 6.773 12.512 7.787 ;
     RECT  3.136 5.365 3.168 9.195 ;
     RECT  10.24 9.141 10.272 9.771 ;
     RECT  6.256 7.349 6.88 10.741 ;
     RECT  11.656 7.787 12.512 13.163 ;
     RECT  14.72 10.549 14.752 13.483 ;
     RECT  2.816 14.773 2.848 15.467 ;
     RECT  0.064 3.125 1.144 15.787 ;
     RECT  6.256 10.741 7.328 15.979 ;
     RECT  11.656 13.163 11.944 20.469 ;
     RECT  3.648 18.741 3.68 21.163 ;
     RECT  6.256 15.979 7.136 22.059 ;
     RECT  6.256 22.059 7.008 23.979 ;
     RECT  11.656 20.469 12.832 24.309 ;
     RECT  10.56 24.309 12.832 25.131 ;
     RECT  6.256 23.979 6.688 26.795 ;
     RECT  10.56 25.131 11.944 28.459 ;
     RECT  0.856 15.787 1.144 31.599 ;
     RECT  6.256 26.795 6.544 31.599 ;
     RECT  11.656 28.459 11.944 31.599 ;
  END
END dsfd_stnh_566x1
END LIBRARY
